VERSION 5.8 ;
BUSBITCHARS "[]" ;
DIVIDERCHAR "/" ;
UNITS
    DATABASE MICRONS 1000 ;
END UNITS

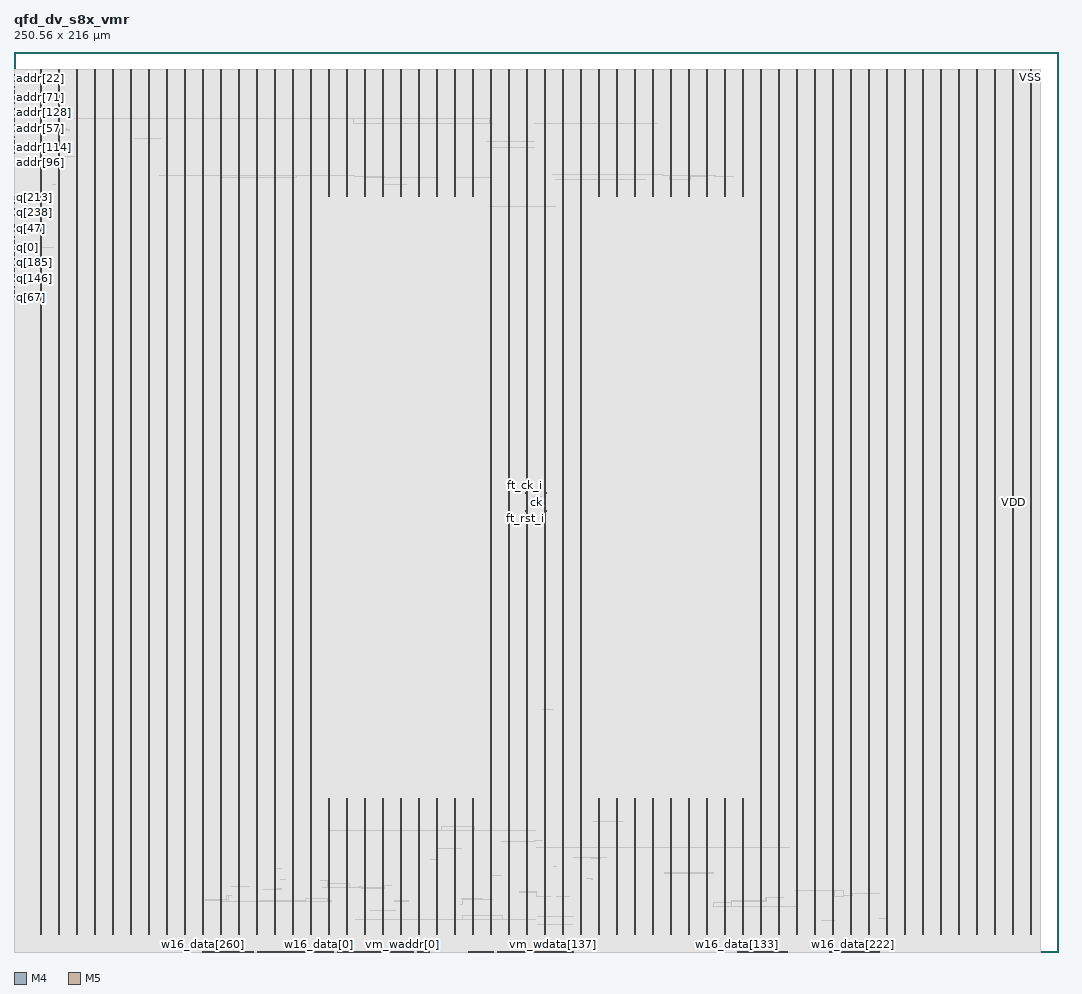
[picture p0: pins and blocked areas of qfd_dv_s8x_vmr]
MACRO qfd_dv_s8x_vmr
  FOREIGN qfd_dv_s8x_vmr 0 0 ;
  CLASS BLOCK ;
  SIZE 250.56 BY 216 ;
  PIN addr[0]
    DIRECTION INPUT ;
    USE SIGNAL ;
    PORT
      LAYER M4 ;
        RECT  0 207.504 0.084 207.528 ;
    END
  END addr[0]
  PIN addr[100]
    DIRECTION INPUT ;
    USE SIGNAL ;
    PORT
      LAYER M4 ;
        RECT  0 191.76 0.084 191.784 ;
    END
  END addr[100]
  PIN addr[101]
    DIRECTION INPUT ;
    USE SIGNAL ;
    PORT
      LAYER M4 ;
        RECT  0 191.856 0.084 191.88 ;
    END
  END addr[101]
  PIN addr[102]
    DIRECTION INPUT ;
    USE SIGNAL ;
    PORT
      LAYER M4 ;
        RECT  0 191.952 0.084 191.976 ;
    END
  END addr[102]
  PIN addr[103]
    DIRECTION INPUT ;
    USE SIGNAL ;
    PORT
      LAYER M4 ;
        RECT  0 192.048 0.084 192.072 ;
    END
  END addr[103]
  PIN addr[104]
    DIRECTION INPUT ;
    USE SIGNAL ;
    PORT
      LAYER M4 ;
        RECT  0 192.144 0.084 192.168 ;
    END
  END addr[104]
  PIN addr[105]
    DIRECTION INPUT ;
    USE SIGNAL ;
    PORT
      LAYER M4 ;
        RECT  0 192.24 0.084 192.264 ;
    END
  END addr[105]
  PIN addr[106]
    DIRECTION INPUT ;
    USE SIGNAL ;
    PORT
      LAYER M4 ;
        RECT  0 192.336 0.084 192.36 ;
    END
  END addr[106]
  PIN addr[107]
    DIRECTION INPUT ;
    USE SIGNAL ;
    PORT
      LAYER M4 ;
        RECT  0 192.432 0.084 192.456 ;
    END
  END addr[107]
  PIN addr[108]
    DIRECTION INPUT ;
    USE SIGNAL ;
    PORT
      LAYER M4 ;
        RECT  0 192.528 0.084 192.552 ;
    END
  END addr[108]
  PIN addr[109]
    DIRECTION INPUT ;
    USE SIGNAL ;
    PORT
      LAYER M4 ;
        RECT  0 192.624 0.084 192.648 ;
    END
  END addr[109]
  PIN addr[10]
    DIRECTION INPUT ;
    USE SIGNAL ;
    PORT
      LAYER M4 ;
        RECT  0 208.464 0.084 208.488 ;
    END
  END addr[10]
  PIN addr[110]
    DIRECTION INPUT ;
    USE SIGNAL ;
    PORT
      LAYER M4 ;
        RECT  0 192.72 0.084 192.744 ;
    END
  END addr[110]
  PIN addr[111]
    DIRECTION INPUT ;
    USE SIGNAL ;
    PORT
      LAYER M4 ;
        RECT  0 192.816 0.084 192.84 ;
    END
  END addr[111]
  PIN addr[112]
    DIRECTION INPUT ;
    USE SIGNAL ;
    PORT
      LAYER M4 ;
        RECT  0 192.912 0.084 192.936 ;
    END
  END addr[112]
  PIN addr[113]
    DIRECTION INPUT ;
    USE SIGNAL ;
    PORT
      LAYER M4 ;
        RECT  0 193.008 0.084 193.032 ;
    END
  END addr[113]
  PIN addr[114]
    DIRECTION INPUT ;
    USE SIGNAL ;
    PORT
      LAYER M4 ;
        RECT  0 193.104 0.084 193.128 ;
    END
  END addr[114]
  PIN addr[115]
    DIRECTION INPUT ;
    USE SIGNAL ;
    PORT
      LAYER M4 ;
        RECT  0 193.2 0.084 193.224 ;
    END
  END addr[115]
  PIN addr[116]
    DIRECTION INPUT ;
    USE SIGNAL ;
    PORT
      LAYER M4 ;
        RECT  0 193.296 0.084 193.32 ;
    END
  END addr[116]
  PIN addr[117]
    DIRECTION INPUT ;
    USE SIGNAL ;
    PORT
      LAYER M4 ;
        RECT  0 193.392 0.084 193.416 ;
    END
  END addr[117]
  PIN addr[118]
    DIRECTION INPUT ;
    USE SIGNAL ;
    PORT
      LAYER M4 ;
        RECT  0 193.488 0.084 193.512 ;
    END
  END addr[118]
  PIN addr[119]
    DIRECTION INPUT ;
    USE SIGNAL ;
    PORT
      LAYER M4 ;
        RECT  0 193.584 0.084 193.608 ;
    END
  END addr[119]
  PIN addr[11]
    DIRECTION INPUT ;
    USE SIGNAL ;
    PORT
      LAYER M4 ;
        RECT  0 208.56 0.084 208.584 ;
    END
  END addr[11]
  PIN addr[120]
    DIRECTION INPUT ;
    USE SIGNAL ;
    PORT
      LAYER M4 ;
        RECT  0 193.68 0.084 193.704 ;
    END
  END addr[120]
  PIN addr[121]
    DIRECTION INPUT ;
    USE SIGNAL ;
    PORT
      LAYER M4 ;
        RECT  0 193.776 0.084 193.8 ;
    END
  END addr[121]
  PIN addr[122]
    DIRECTION INPUT ;
    USE SIGNAL ;
    PORT
      LAYER M4 ;
        RECT  0 193.872 0.084 193.896 ;
    END
  END addr[122]
  PIN addr[123]
    DIRECTION INPUT ;
    USE SIGNAL ;
    PORT
      LAYER M4 ;
        RECT  0 193.968 0.084 193.992 ;
    END
  END addr[123]
  PIN addr[124]
    DIRECTION INPUT ;
    USE SIGNAL ;
    PORT
      LAYER M4 ;
        RECT  0 194.064 0.084 194.088 ;
    END
  END addr[124]
  PIN addr[125]
    DIRECTION INPUT ;
    USE SIGNAL ;
    PORT
      LAYER M4 ;
        RECT  0 194.16 0.084 194.184 ;
    END
  END addr[125]
  PIN addr[126]
    DIRECTION INPUT ;
    USE SIGNAL ;
    PORT
      LAYER M4 ;
        RECT  0 194.256 0.084 194.28 ;
    END
  END addr[126]
  PIN addr[127]
    DIRECTION INPUT ;
    USE SIGNAL ;
    PORT
      LAYER M4 ;
        RECT  0 194.352 0.084 194.376 ;
    END
  END addr[127]
  PIN addr[128]
    DIRECTION INPUT ;
    USE SIGNAL ;
    PORT
      LAYER M4 ;
        RECT  0 201.36 0.084 201.384 ;
    END
  END addr[128]
  PIN addr[129]
    DIRECTION INPUT ;
    USE SIGNAL ;
    PORT
      LAYER M4 ;
        RECT  0 201.456 0.084 201.48 ;
    END
  END addr[129]
  PIN addr[12]
    DIRECTION INPUT ;
    USE SIGNAL ;
    PORT
      LAYER M4 ;
        RECT  0 208.656 0.084 208.68 ;
    END
  END addr[12]
  PIN addr[130]
    DIRECTION INPUT ;
    USE SIGNAL ;
    PORT
      LAYER M4 ;
        RECT  0 201.552 0.084 201.576 ;
    END
  END addr[130]
  PIN addr[131]
    DIRECTION INPUT ;
    USE SIGNAL ;
    PORT
      LAYER M4 ;
        RECT  0 201.648 0.084 201.672 ;
    END
  END addr[131]
  PIN addr[132]
    DIRECTION INPUT ;
    USE SIGNAL ;
    PORT
      LAYER M4 ;
        RECT  0 201.744 0.084 201.768 ;
    END
  END addr[132]
  PIN addr[133]
    DIRECTION INPUT ;
    USE SIGNAL ;
    PORT
      LAYER M4 ;
        RECT  0 201.84 0.084 201.864 ;
    END
  END addr[133]
  PIN addr[134]
    DIRECTION INPUT ;
    USE SIGNAL ;
    PORT
      LAYER M4 ;
        RECT  0 201.936 0.084 201.96 ;
    END
  END addr[134]
  PIN addr[135]
    DIRECTION INPUT ;
    USE SIGNAL ;
    PORT
      LAYER M4 ;
        RECT  0 202.032 0.084 202.056 ;
    END
  END addr[135]
  PIN addr[136]
    DIRECTION INPUT ;
    USE SIGNAL ;
    PORT
      LAYER M4 ;
        RECT  0 202.128 0.084 202.152 ;
    END
  END addr[136]
  PIN addr[137]
    DIRECTION INPUT ;
    USE SIGNAL ;
    PORT
      LAYER M4 ;
        RECT  0 202.224 0.084 202.248 ;
    END
  END addr[137]
  PIN addr[138]
    DIRECTION INPUT ;
    USE SIGNAL ;
    PORT
      LAYER M4 ;
        RECT  0 202.32 0.084 202.344 ;
    END
  END addr[138]
  PIN addr[139]
    DIRECTION INPUT ;
    USE SIGNAL ;
    PORT
      LAYER M4 ;
        RECT  0 202.416 0.084 202.44 ;
    END
  END addr[139]
  PIN addr[13]
    DIRECTION INPUT ;
    USE SIGNAL ;
    PORT
      LAYER M4 ;
        RECT  0 208.752 0.084 208.776 ;
    END
  END addr[13]
  PIN addr[140]
    DIRECTION INPUT ;
    USE SIGNAL ;
    PORT
      LAYER M4 ;
        RECT  0 202.512 0.084 202.536 ;
    END
  END addr[140]
  PIN addr[141]
    DIRECTION INPUT ;
    USE SIGNAL ;
    PORT
      LAYER M4 ;
        RECT  0 202.608 0.084 202.632 ;
    END
  END addr[141]
  PIN addr[142]
    DIRECTION INPUT ;
    USE SIGNAL ;
    PORT
      LAYER M4 ;
        RECT  0 202.704 0.084 202.728 ;
    END
  END addr[142]
  PIN addr[143]
    DIRECTION INPUT ;
    USE SIGNAL ;
    PORT
      LAYER M4 ;
        RECT  0 202.8 0.084 202.824 ;
    END
  END addr[143]
  PIN addr[144]
    DIRECTION INPUT ;
    USE SIGNAL ;
    PORT
      LAYER M4 ;
        RECT  0 202.896 0.084 202.92 ;
    END
  END addr[144]
  PIN addr[145]
    DIRECTION INPUT ;
    USE SIGNAL ;
    PORT
      LAYER M4 ;
        RECT  0 202.992 0.084 203.016 ;
    END
  END addr[145]
  PIN addr[146]
    DIRECTION INPUT ;
    USE SIGNAL ;
    PORT
      LAYER M4 ;
        RECT  0 203.088 0.084 203.112 ;
    END
  END addr[146]
  PIN addr[147]
    DIRECTION INPUT ;
    USE SIGNAL ;
    PORT
      LAYER M4 ;
        RECT  0 203.184 0.084 203.208 ;
    END
  END addr[147]
  PIN addr[148]
    DIRECTION INPUT ;
    USE SIGNAL ;
    PORT
      LAYER M4 ;
        RECT  0 203.28 0.084 203.304 ;
    END
  END addr[148]
  PIN addr[149]
    DIRECTION INPUT ;
    USE SIGNAL ;
    PORT
      LAYER M4 ;
        RECT  0 203.376 0.084 203.4 ;
    END
  END addr[149]
  PIN addr[14]
    DIRECTION INPUT ;
    USE SIGNAL ;
    PORT
      LAYER M4 ;
        RECT  0 208.848 0.084 208.872 ;
    END
  END addr[14]
  PIN addr[150]
    DIRECTION INPUT ;
    USE SIGNAL ;
    PORT
      LAYER M4 ;
        RECT  0 203.472 0.084 203.496 ;
    END
  END addr[150]
  PIN addr[151]
    DIRECTION INPUT ;
    USE SIGNAL ;
    PORT
      LAYER M4 ;
        RECT  0 203.568 0.084 203.592 ;
    END
  END addr[151]
  PIN addr[152]
    DIRECTION INPUT ;
    USE SIGNAL ;
    PORT
      LAYER M4 ;
        RECT  0 203.664 0.084 203.688 ;
    END
  END addr[152]
  PIN addr[153]
    DIRECTION INPUT ;
    USE SIGNAL ;
    PORT
      LAYER M4 ;
        RECT  0 203.76 0.084 203.784 ;
    END
  END addr[153]
  PIN addr[154]
    DIRECTION INPUT ;
    USE SIGNAL ;
    PORT
      LAYER M4 ;
        RECT  0 203.856 0.084 203.88 ;
    END
  END addr[154]
  PIN addr[155]
    DIRECTION INPUT ;
    USE SIGNAL ;
    PORT
      LAYER M4 ;
        RECT  0 203.952 0.084 203.976 ;
    END
  END addr[155]
  PIN addr[156]
    DIRECTION INPUT ;
    USE SIGNAL ;
    PORT
      LAYER M4 ;
        RECT  0 204.048 0.084 204.072 ;
    END
  END addr[156]
  PIN addr[157]
    DIRECTION INPUT ;
    USE SIGNAL ;
    PORT
      LAYER M4 ;
        RECT  0 204.144 0.084 204.168 ;
    END
  END addr[157]
  PIN addr[158]
    DIRECTION INPUT ;
    USE SIGNAL ;
    PORT
      LAYER M4 ;
        RECT  0 204.24 0.084 204.264 ;
    END
  END addr[158]
  PIN addr[159]
    DIRECTION INPUT ;
    USE SIGNAL ;
    PORT
      LAYER M4 ;
        RECT  0 204.336 0.084 204.36 ;
    END
  END addr[159]
  PIN addr[15]
    DIRECTION INPUT ;
    USE SIGNAL ;
    PORT
      LAYER M4 ;
        RECT  0 208.944 0.084 208.968 ;
    END
  END addr[15]
  PIN addr[160]
    DIRECTION INPUT ;
    USE SIGNAL ;
    PORT
      LAYER M4 ;
        RECT  0 198.288 0.084 198.312 ;
    END
  END addr[160]
  PIN addr[161]
    DIRECTION INPUT ;
    USE SIGNAL ;
    PORT
      LAYER M4 ;
        RECT  0 198.384 0.084 198.408 ;
    END
  END addr[161]
  PIN addr[162]
    DIRECTION INPUT ;
    USE SIGNAL ;
    PORT
      LAYER M4 ;
        RECT  0 198.48 0.084 198.504 ;
    END
  END addr[162]
  PIN addr[163]
    DIRECTION INPUT ;
    USE SIGNAL ;
    PORT
      LAYER M4 ;
        RECT  0 198.576 0.084 198.6 ;
    END
  END addr[163]
  PIN addr[164]
    DIRECTION INPUT ;
    USE SIGNAL ;
    PORT
      LAYER M4 ;
        RECT  0 198.672 0.084 198.696 ;
    END
  END addr[164]
  PIN addr[165]
    DIRECTION INPUT ;
    USE SIGNAL ;
    PORT
      LAYER M4 ;
        RECT  0 198.768 0.084 198.792 ;
    END
  END addr[165]
  PIN addr[166]
    DIRECTION INPUT ;
    USE SIGNAL ;
    PORT
      LAYER M4 ;
        RECT  0 198.864 0.084 198.888 ;
    END
  END addr[166]
  PIN addr[167]
    DIRECTION INPUT ;
    USE SIGNAL ;
    PORT
      LAYER M4 ;
        RECT  0 198.96 0.084 198.984 ;
    END
  END addr[167]
  PIN addr[168]
    DIRECTION INPUT ;
    USE SIGNAL ;
    PORT
      LAYER M4 ;
        RECT  0 199.056 0.084 199.08 ;
    END
  END addr[168]
  PIN addr[169]
    DIRECTION INPUT ;
    USE SIGNAL ;
    PORT
      LAYER M4 ;
        RECT  0 199.152 0.084 199.176 ;
    END
  END addr[169]
  PIN addr[16]
    DIRECTION INPUT ;
    USE SIGNAL ;
    PORT
      LAYER M4 ;
        RECT  0 209.04 0.084 209.064 ;
    END
  END addr[16]
  PIN addr[170]
    DIRECTION INPUT ;
    USE SIGNAL ;
    PORT
      LAYER M4 ;
        RECT  0 199.248 0.084 199.272 ;
    END
  END addr[170]
  PIN addr[171]
    DIRECTION INPUT ;
    USE SIGNAL ;
    PORT
      LAYER M4 ;
        RECT  0 199.344 0.084 199.368 ;
    END
  END addr[171]
  PIN addr[172]
    DIRECTION INPUT ;
    USE SIGNAL ;
    PORT
      LAYER M4 ;
        RECT  0 199.44 0.084 199.464 ;
    END
  END addr[172]
  PIN addr[173]
    DIRECTION INPUT ;
    USE SIGNAL ;
    PORT
      LAYER M4 ;
        RECT  0 199.536 0.084 199.56 ;
    END
  END addr[173]
  PIN addr[174]
    DIRECTION INPUT ;
    USE SIGNAL ;
    PORT
      LAYER M4 ;
        RECT  0 199.632 0.084 199.656 ;
    END
  END addr[174]
  PIN addr[175]
    DIRECTION INPUT ;
    USE SIGNAL ;
    PORT
      LAYER M4 ;
        RECT  0 199.728 0.084 199.752 ;
    END
  END addr[175]
  PIN addr[176]
    DIRECTION INPUT ;
    USE SIGNAL ;
    PORT
      LAYER M4 ;
        RECT  0 199.824 0.084 199.848 ;
    END
  END addr[176]
  PIN addr[177]
    DIRECTION INPUT ;
    USE SIGNAL ;
    PORT
      LAYER M4 ;
        RECT  0 199.92 0.084 199.944 ;
    END
  END addr[177]
  PIN addr[178]
    DIRECTION INPUT ;
    USE SIGNAL ;
    PORT
      LAYER M4 ;
        RECT  0 200.016 0.084 200.04 ;
    END
  END addr[178]
  PIN addr[179]
    DIRECTION INPUT ;
    USE SIGNAL ;
    PORT
      LAYER M4 ;
        RECT  0 200.112 0.084 200.136 ;
    END
  END addr[179]
  PIN addr[17]
    DIRECTION INPUT ;
    USE SIGNAL ;
    PORT
      LAYER M4 ;
        RECT  0 209.136 0.084 209.16 ;
    END
  END addr[17]
  PIN addr[180]
    DIRECTION INPUT ;
    USE SIGNAL ;
    PORT
      LAYER M4 ;
        RECT  0 200.208 0.084 200.232 ;
    END
  END addr[180]
  PIN addr[181]
    DIRECTION INPUT ;
    USE SIGNAL ;
    PORT
      LAYER M4 ;
        RECT  0 200.304 0.084 200.328 ;
    END
  END addr[181]
  PIN addr[182]
    DIRECTION INPUT ;
    USE SIGNAL ;
    PORT
      LAYER M4 ;
        RECT  0 200.4 0.084 200.424 ;
    END
  END addr[182]
  PIN addr[183]
    DIRECTION INPUT ;
    USE SIGNAL ;
    PORT
      LAYER M4 ;
        RECT  0 200.496 0.084 200.52 ;
    END
  END addr[183]
  PIN addr[184]
    DIRECTION INPUT ;
    USE SIGNAL ;
    PORT
      LAYER M4 ;
        RECT  0 200.592 0.084 200.616 ;
    END
  END addr[184]
  PIN addr[185]
    DIRECTION INPUT ;
    USE SIGNAL ;
    PORT
      LAYER M4 ;
        RECT  0 200.688 0.084 200.712 ;
    END
  END addr[185]
  PIN addr[186]
    DIRECTION INPUT ;
    USE SIGNAL ;
    PORT
      LAYER M4 ;
        RECT  0 200.784 0.084 200.808 ;
    END
  END addr[186]
  PIN addr[187]
    DIRECTION INPUT ;
    USE SIGNAL ;
    PORT
      LAYER M4 ;
        RECT  0 200.88 0.084 200.904 ;
    END
  END addr[187]
  PIN addr[188]
    DIRECTION INPUT ;
    USE SIGNAL ;
    PORT
      LAYER M4 ;
        RECT  0 200.976 0.084 201 ;
    END
  END addr[188]
  PIN addr[189]
    DIRECTION INPUT ;
    USE SIGNAL ;
    PORT
      LAYER M4 ;
        RECT  0 201.072 0.084 201.096 ;
    END
  END addr[189]
  PIN addr[18]
    DIRECTION INPUT ;
    USE SIGNAL ;
    PORT
      LAYER M4 ;
        RECT  0 209.232 0.084 209.256 ;
    END
  END addr[18]
  PIN addr[190]
    DIRECTION INPUT ;
    USE SIGNAL ;
    PORT
      LAYER M4 ;
        RECT  0 201.168 0.084 201.192 ;
    END
  END addr[190]
  PIN addr[191]
    DIRECTION INPUT ;
    USE SIGNAL ;
    PORT
      LAYER M4 ;
        RECT  0 201.264 0.084 201.288 ;
    END
  END addr[191]
  PIN addr[19]
    DIRECTION INPUT ;
    USE SIGNAL ;
    PORT
      LAYER M4 ;
        RECT  0 209.328 0.084 209.352 ;
    END
  END addr[19]
  PIN addr[1]
    DIRECTION INPUT ;
    USE SIGNAL ;
    PORT
      LAYER M4 ;
        RECT  0 207.6 0.084 207.624 ;
    END
  END addr[1]
  PIN addr[20]
    DIRECTION INPUT ;
    USE SIGNAL ;
    PORT
      LAYER M4 ;
        RECT  0 209.424 0.084 209.448 ;
    END
  END addr[20]
  PIN addr[21]
    DIRECTION INPUT ;
    USE SIGNAL ;
    PORT
      LAYER M4 ;
        RECT  0 209.52 0.084 209.544 ;
    END
  END addr[21]
  PIN addr[22]
    DIRECTION INPUT ;
    USE SIGNAL ;
    PORT
      LAYER M4 ;
        RECT  0 209.616 0.084 209.64 ;
    END
  END addr[22]
  PIN addr[23]
    DIRECTION INPUT ;
    USE SIGNAL ;
    PORT
      LAYER M4 ;
        RECT  0 209.712 0.084 209.736 ;
    END
  END addr[23]
  PIN addr[24]
    DIRECTION INPUT ;
    USE SIGNAL ;
    PORT
      LAYER M4 ;
        RECT  0 209.808 0.084 209.832 ;
    END
  END addr[24]
  PIN addr[25]
    DIRECTION INPUT ;
    USE SIGNAL ;
    PORT
      LAYER M4 ;
        RECT  0 209.904 0.084 209.928 ;
    END
  END addr[25]
  PIN addr[26]
    DIRECTION INPUT ;
    USE SIGNAL ;
    PORT
      LAYER M4 ;
        RECT  0 210 0.084 210.024 ;
    END
  END addr[26]
  PIN addr[27]
    DIRECTION INPUT ;
    USE SIGNAL ;
    PORT
      LAYER M4 ;
        RECT  0 210.096 0.084 210.12 ;
    END
  END addr[27]
  PIN addr[28]
    DIRECTION INPUT ;
    USE SIGNAL ;
    PORT
      LAYER M4 ;
        RECT  0 210.192 0.084 210.216 ;
    END
  END addr[28]
  PIN addr[29]
    DIRECTION INPUT ;
    USE SIGNAL ;
    PORT
      LAYER M4 ;
        RECT  0 210.288 0.084 210.312 ;
    END
  END addr[29]
  PIN addr[2]
    DIRECTION INPUT ;
    USE SIGNAL ;
    PORT
      LAYER M4 ;
        RECT  0 207.696 0.084 207.72 ;
    END
  END addr[2]
  PIN addr[30]
    DIRECTION INPUT ;
    USE SIGNAL ;
    PORT
      LAYER M4 ;
        RECT  0 210.384 0.084 210.408 ;
    END
  END addr[30]
  PIN addr[31]
    DIRECTION INPUT ;
    USE SIGNAL ;
    PORT
      LAYER M4 ;
        RECT  0 210.48 0.084 210.504 ;
    END
  END addr[31]
  PIN addr[32]
    DIRECTION INPUT ;
    USE SIGNAL ;
    PORT
      LAYER M4 ;
        RECT  0 195.216 0.084 195.24 ;
    END
  END addr[32]
  PIN addr[33]
    DIRECTION INPUT ;
    USE SIGNAL ;
    PORT
      LAYER M4 ;
        RECT  0 195.312 0.084 195.336 ;
    END
  END addr[33]
  PIN addr[34]
    DIRECTION INPUT ;
    USE SIGNAL ;
    PORT
      LAYER M4 ;
        RECT  0 195.408 0.084 195.432 ;
    END
  END addr[34]
  PIN addr[35]
    DIRECTION INPUT ;
    USE SIGNAL ;
    PORT
      LAYER M4 ;
        RECT  0 195.504 0.084 195.528 ;
    END
  END addr[35]
  PIN addr[36]
    DIRECTION INPUT ;
    USE SIGNAL ;
    PORT
      LAYER M4 ;
        RECT  0 195.6 0.084 195.624 ;
    END
  END addr[36]
  PIN addr[37]
    DIRECTION INPUT ;
    USE SIGNAL ;
    PORT
      LAYER M4 ;
        RECT  0 195.696 0.084 195.72 ;
    END
  END addr[37]
  PIN addr[38]
    DIRECTION INPUT ;
    USE SIGNAL ;
    PORT
      LAYER M4 ;
        RECT  0 195.792 0.084 195.816 ;
    END
  END addr[38]
  PIN addr[39]
    DIRECTION INPUT ;
    USE SIGNAL ;
    PORT
      LAYER M4 ;
        RECT  0 195.888 0.084 195.912 ;
    END
  END addr[39]
  PIN addr[3]
    DIRECTION INPUT ;
    USE SIGNAL ;
    PORT
      LAYER M4 ;
        RECT  0 207.792 0.084 207.816 ;
    END
  END addr[3]
  PIN addr[40]
    DIRECTION INPUT ;
    USE SIGNAL ;
    PORT
      LAYER M4 ;
        RECT  0 195.984 0.084 196.008 ;
    END
  END addr[40]
  PIN addr[41]
    DIRECTION INPUT ;
    USE SIGNAL ;
    PORT
      LAYER M4 ;
        RECT  0 196.08 0.084 196.104 ;
    END
  END addr[41]
  PIN addr[42]
    DIRECTION INPUT ;
    USE SIGNAL ;
    PORT
      LAYER M4 ;
        RECT  0 196.176 0.084 196.2 ;
    END
  END addr[42]
  PIN addr[43]
    DIRECTION INPUT ;
    USE SIGNAL ;
    PORT
      LAYER M4 ;
        RECT  0 196.272 0.084 196.296 ;
    END
  END addr[43]
  PIN addr[44]
    DIRECTION INPUT ;
    USE SIGNAL ;
    PORT
      LAYER M4 ;
        RECT  0 196.368 0.084 196.392 ;
    END
  END addr[44]
  PIN addr[45]
    DIRECTION INPUT ;
    USE SIGNAL ;
    PORT
      LAYER M4 ;
        RECT  0 196.464 0.084 196.488 ;
    END
  END addr[45]
  PIN addr[46]
    DIRECTION INPUT ;
    USE SIGNAL ;
    PORT
      LAYER M4 ;
        RECT  0 196.56 0.084 196.584 ;
    END
  END addr[46]
  PIN addr[47]
    DIRECTION INPUT ;
    USE SIGNAL ;
    PORT
      LAYER M4 ;
        RECT  0 196.656 0.084 196.68 ;
    END
  END addr[47]
  PIN addr[48]
    DIRECTION INPUT ;
    USE SIGNAL ;
    PORT
      LAYER M4 ;
        RECT  0 196.752 0.084 196.776 ;
    END
  END addr[48]
  PIN addr[49]
    DIRECTION INPUT ;
    USE SIGNAL ;
    PORT
      LAYER M4 ;
        RECT  0 196.848 0.084 196.872 ;
    END
  END addr[49]
  PIN addr[4]
    DIRECTION INPUT ;
    USE SIGNAL ;
    PORT
      LAYER M4 ;
        RECT  0 207.888 0.084 207.912 ;
    END
  END addr[4]
  PIN addr[50]
    DIRECTION INPUT ;
    USE SIGNAL ;
    PORT
      LAYER M4 ;
        RECT  0 196.944 0.084 196.968 ;
    END
  END addr[50]
  PIN addr[51]
    DIRECTION INPUT ;
    USE SIGNAL ;
    PORT
      LAYER M4 ;
        RECT  0 197.04 0.084 197.064 ;
    END
  END addr[51]
  PIN addr[52]
    DIRECTION INPUT ;
    USE SIGNAL ;
    PORT
      LAYER M4 ;
        RECT  0 197.136 0.084 197.16 ;
    END
  END addr[52]
  PIN addr[53]
    DIRECTION INPUT ;
    USE SIGNAL ;
    PORT
      LAYER M4 ;
        RECT  0 197.232 0.084 197.256 ;
    END
  END addr[53]
  PIN addr[54]
    DIRECTION INPUT ;
    USE SIGNAL ;
    PORT
      LAYER M4 ;
        RECT  0 197.328 0.084 197.352 ;
    END
  END addr[54]
  PIN addr[55]
    DIRECTION INPUT ;
    USE SIGNAL ;
    PORT
      LAYER M4 ;
        RECT  0 197.424 0.084 197.448 ;
    END
  END addr[55]
  PIN addr[56]
    DIRECTION INPUT ;
    USE SIGNAL ;
    PORT
      LAYER M4 ;
        RECT  0 197.52 0.084 197.544 ;
    END
  END addr[56]
  PIN addr[57]
    DIRECTION INPUT ;
    USE SIGNAL ;
    PORT
      LAYER M4 ;
        RECT  0 197.616 0.084 197.64 ;
    END
  END addr[57]
  PIN addr[58]
    DIRECTION INPUT ;
    USE SIGNAL ;
    PORT
      LAYER M4 ;
        RECT  0 197.712 0.084 197.736 ;
    END
  END addr[58]
  PIN addr[59]
    DIRECTION INPUT ;
    USE SIGNAL ;
    PORT
      LAYER M4 ;
        RECT  0 197.808 0.084 197.832 ;
    END
  END addr[59]
  PIN addr[5]
    DIRECTION INPUT ;
    USE SIGNAL ;
    PORT
      LAYER M4 ;
        RECT  0 207.984 0.084 208.008 ;
    END
  END addr[5]
  PIN addr[60]
    DIRECTION INPUT ;
    USE SIGNAL ;
    PORT
      LAYER M4 ;
        RECT  0 197.904 0.084 197.928 ;
    END
  END addr[60]
  PIN addr[61]
    DIRECTION INPUT ;
    USE SIGNAL ;
    PORT
      LAYER M4 ;
        RECT  0 198 0.084 198.024 ;
    END
  END addr[61]
  PIN addr[62]
    DIRECTION INPUT ;
    USE SIGNAL ;
    PORT
      LAYER M4 ;
        RECT  0 198.096 0.084 198.12 ;
    END
  END addr[62]
  PIN addr[63]
    DIRECTION INPUT ;
    USE SIGNAL ;
    PORT
      LAYER M4 ;
        RECT  0 198.192 0.084 198.216 ;
    END
  END addr[63]
  PIN addr[64]
    DIRECTION INPUT ;
    USE SIGNAL ;
    PORT
      LAYER M4 ;
        RECT  0 204.432 0.084 204.456 ;
    END
  END addr[64]
  PIN addr[65]
    DIRECTION INPUT ;
    USE SIGNAL ;
    PORT
      LAYER M4 ;
        RECT  0 204.528 0.084 204.552 ;
    END
  END addr[65]
  PIN addr[66]
    DIRECTION INPUT ;
    USE SIGNAL ;
    PORT
      LAYER M4 ;
        RECT  0 204.624 0.084 204.648 ;
    END
  END addr[66]
  PIN addr[67]
    DIRECTION INPUT ;
    USE SIGNAL ;
    PORT
      LAYER M4 ;
        RECT  0 204.72 0.084 204.744 ;
    END
  END addr[67]
  PIN addr[68]
    DIRECTION INPUT ;
    USE SIGNAL ;
    PORT
      LAYER M4 ;
        RECT  0 204.816 0.084 204.84 ;
    END
  END addr[68]
  PIN addr[69]
    DIRECTION INPUT ;
    USE SIGNAL ;
    PORT
      LAYER M4 ;
        RECT  0 204.912 0.084 204.936 ;
    END
  END addr[69]
  PIN addr[6]
    DIRECTION INPUT ;
    USE SIGNAL ;
    PORT
      LAYER M4 ;
        RECT  0 208.08 0.084 208.104 ;
    END
  END addr[6]
  PIN addr[70]
    DIRECTION INPUT ;
    USE SIGNAL ;
    PORT
      LAYER M4 ;
        RECT  0 205.008 0.084 205.032 ;
    END
  END addr[70]
  PIN addr[71]
    DIRECTION INPUT ;
    USE SIGNAL ;
    PORT
      LAYER M4 ;
        RECT  0 205.104 0.084 205.128 ;
    END
  END addr[71]
  PIN addr[72]
    DIRECTION INPUT ;
    USE SIGNAL ;
    PORT
      LAYER M4 ;
        RECT  0 205.2 0.084 205.224 ;
    END
  END addr[72]
  PIN addr[73]
    DIRECTION INPUT ;
    USE SIGNAL ;
    PORT
      LAYER M4 ;
        RECT  0 205.296 0.084 205.32 ;
    END
  END addr[73]
  PIN addr[74]
    DIRECTION INPUT ;
    USE SIGNAL ;
    PORT
      LAYER M4 ;
        RECT  0 205.392 0.084 205.416 ;
    END
  END addr[74]
  PIN addr[75]
    DIRECTION INPUT ;
    USE SIGNAL ;
    PORT
      LAYER M4 ;
        RECT  0 205.488 0.084 205.512 ;
    END
  END addr[75]
  PIN addr[76]
    DIRECTION INPUT ;
    USE SIGNAL ;
    PORT
      LAYER M4 ;
        RECT  0 205.584 0.084 205.608 ;
    END
  END addr[76]
  PIN addr[77]
    DIRECTION INPUT ;
    USE SIGNAL ;
    PORT
      LAYER M4 ;
        RECT  0 205.68 0.084 205.704 ;
    END
  END addr[77]
  PIN addr[78]
    DIRECTION INPUT ;
    USE SIGNAL ;
    PORT
      LAYER M4 ;
        RECT  0 205.776 0.084 205.8 ;
    END
  END addr[78]
  PIN addr[79]
    DIRECTION INPUT ;
    USE SIGNAL ;
    PORT
      LAYER M4 ;
        RECT  0 205.872 0.084 205.896 ;
    END
  END addr[79]
  PIN addr[7]
    DIRECTION INPUT ;
    USE SIGNAL ;
    PORT
      LAYER M4 ;
        RECT  0 208.176 0.084 208.2 ;
    END
  END addr[7]
  PIN addr[80]
    DIRECTION INPUT ;
    USE SIGNAL ;
    PORT
      LAYER M4 ;
        RECT  0 205.968 0.084 205.992 ;
    END
  END addr[80]
  PIN addr[81]
    DIRECTION INPUT ;
    USE SIGNAL ;
    PORT
      LAYER M4 ;
        RECT  0 206.064 0.084 206.088 ;
    END
  END addr[81]
  PIN addr[82]
    DIRECTION INPUT ;
    USE SIGNAL ;
    PORT
      LAYER M4 ;
        RECT  0 206.16 0.084 206.184 ;
    END
  END addr[82]
  PIN addr[83]
    DIRECTION INPUT ;
    USE SIGNAL ;
    PORT
      LAYER M4 ;
        RECT  0 206.256 0.084 206.28 ;
    END
  END addr[83]
  PIN addr[84]
    DIRECTION INPUT ;
    USE SIGNAL ;
    PORT
      LAYER M4 ;
        RECT  0 206.352 0.084 206.376 ;
    END
  END addr[84]
  PIN addr[85]
    DIRECTION INPUT ;
    USE SIGNAL ;
    PORT
      LAYER M4 ;
        RECT  0 206.448 0.084 206.472 ;
    END
  END addr[85]
  PIN addr[86]
    DIRECTION INPUT ;
    USE SIGNAL ;
    PORT
      LAYER M4 ;
        RECT  0 206.544 0.084 206.568 ;
    END
  END addr[86]
  PIN addr[87]
    DIRECTION INPUT ;
    USE SIGNAL ;
    PORT
      LAYER M4 ;
        RECT  0 206.64 0.084 206.664 ;
    END
  END addr[87]
  PIN addr[88]
    DIRECTION INPUT ;
    USE SIGNAL ;
    PORT
      LAYER M4 ;
        RECT  0 206.736 0.084 206.76 ;
    END
  END addr[88]
  PIN addr[89]
    DIRECTION INPUT ;
    USE SIGNAL ;
    PORT
      LAYER M4 ;
        RECT  0 206.832 0.084 206.856 ;
    END
  END addr[89]
  PIN addr[8]
    DIRECTION INPUT ;
    USE SIGNAL ;
    PORT
      LAYER M4 ;
        RECT  0 208.272 0.084 208.296 ;
    END
  END addr[8]
  PIN addr[90]
    DIRECTION INPUT ;
    USE SIGNAL ;
    PORT
      LAYER M4 ;
        RECT  0 206.928 0.084 206.952 ;
    END
  END addr[90]
  PIN addr[91]
    DIRECTION INPUT ;
    USE SIGNAL ;
    PORT
      LAYER M4 ;
        RECT  0 207.024 0.084 207.048 ;
    END
  END addr[91]
  PIN addr[92]
    DIRECTION INPUT ;
    USE SIGNAL ;
    PORT
      LAYER M4 ;
        RECT  0 207.12 0.084 207.144 ;
    END
  END addr[92]
  PIN addr[93]
    DIRECTION INPUT ;
    USE SIGNAL ;
    PORT
      LAYER M4 ;
        RECT  0 207.216 0.084 207.24 ;
    END
  END addr[93]
  PIN addr[94]
    DIRECTION INPUT ;
    USE SIGNAL ;
    PORT
      LAYER M4 ;
        RECT  0 207.312 0.084 207.336 ;
    END
  END addr[94]
  PIN addr[95]
    DIRECTION INPUT ;
    USE SIGNAL ;
    PORT
      LAYER M4 ;
        RECT  0 207.408 0.084 207.432 ;
    END
  END addr[95]
  PIN addr[96]
    DIRECTION INPUT ;
    USE SIGNAL ;
    PORT
      LAYER M4 ;
        RECT  0 191.376 0.084 191.4 ;
    END
  END addr[96]
  PIN addr[97]
    DIRECTION INPUT ;
    USE SIGNAL ;
    PORT
      LAYER M4 ;
        RECT  0 191.472 0.084 191.496 ;
    END
  END addr[97]
  PIN addr[98]
    DIRECTION INPUT ;
    USE SIGNAL ;
    PORT
      LAYER M4 ;
        RECT  0 191.568 0.084 191.592 ;
    END
  END addr[98]
  PIN addr[99]
    DIRECTION INPUT ;
    USE SIGNAL ;
    PORT
      LAYER M4 ;
        RECT  0 191.664 0.084 191.688 ;
    END
  END addr[99]
  PIN addr[9]
    DIRECTION INPUT ;
    USE SIGNAL ;
    PORT
      LAYER M4 ;
        RECT  0 208.368 0.084 208.392 ;
    END
  END addr[9]
  PIN ck
    DIRECTION INPUT ;
    USE SIGNAL ;
    PORT
      LAYER M5 ;
        RECT  125.28 107.808 125.304 108.192 ;
    END
  END ck
  PIN fault
    DIRECTION OUTPUT ;
    USE SIGNAL ;
    PORT
      LAYER M5 ;
        RECT  92.976 0 93 0.084 ;
    END
  END fault
  PIN q[0]
    DIRECTION OUTPUT ;
    USE SIGNAL ;
    PORT
      LAYER M4 ;
        RECT  0 169.104 0.084 169.128 ;
    END
  END q[0]
  PIN q[100]
    DIRECTION OUTPUT ;
    USE SIGNAL ;
    PORT
      LAYER M4 ;
        RECT  0 166.416 0.084 166.44 ;
    END
  END q[100]
  PIN q[101]
    DIRECTION OUTPUT ;
    USE SIGNAL ;
    PORT
      LAYER M4 ;
        RECT  0 166.512 0.084 166.536 ;
    END
  END q[101]
  PIN q[102]
    DIRECTION OUTPUT ;
    USE SIGNAL ;
    PORT
      LAYER M4 ;
        RECT  0 166.608 0.084 166.632 ;
    END
  END q[102]
  PIN q[103]
    DIRECTION OUTPUT ;
    USE SIGNAL ;
    PORT
      LAYER M4 ;
        RECT  0 166.704 0.084 166.728 ;
    END
  END q[103]
  PIN q[104]
    DIRECTION OUTPUT ;
    USE SIGNAL ;
    PORT
      LAYER M4 ;
        RECT  0 166.8 0.084 166.824 ;
    END
  END q[104]
  PIN q[105]
    DIRECTION OUTPUT ;
    USE SIGNAL ;
    PORT
      LAYER M4 ;
        RECT  0 166.896 0.084 166.92 ;
    END
  END q[105]
  PIN q[106]
    DIRECTION OUTPUT ;
    USE SIGNAL ;
    PORT
      LAYER M4 ;
        RECT  0 166.992 0.084 167.016 ;
    END
  END q[106]
  PIN q[107]
    DIRECTION OUTPUT ;
    USE SIGNAL ;
    PORT
      LAYER M4 ;
        RECT  0 167.088 0.084 167.112 ;
    END
  END q[107]
  PIN q[108]
    DIRECTION OUTPUT ;
    USE SIGNAL ;
    PORT
      LAYER M4 ;
        RECT  0 167.184 0.084 167.208 ;
    END
  END q[108]
  PIN q[109]
    DIRECTION OUTPUT ;
    USE SIGNAL ;
    PORT
      LAYER M4 ;
        RECT  0 167.28 0.084 167.304 ;
    END
  END q[109]
  PIN q[10]
    DIRECTION OUTPUT ;
    USE SIGNAL ;
    PORT
      LAYER M4 ;
        RECT  0 170.064 0.084 170.088 ;
    END
  END q[10]
  PIN q[110]
    DIRECTION OUTPUT ;
    USE SIGNAL ;
    PORT
      LAYER M4 ;
        RECT  0 167.376 0.084 167.4 ;
    END
  END q[110]
  PIN q[111]
    DIRECTION OUTPUT ;
    USE SIGNAL ;
    PORT
      LAYER M4 ;
        RECT  0 167.472 0.084 167.496 ;
    END
  END q[111]
  PIN q[112]
    DIRECTION OUTPUT ;
    USE SIGNAL ;
    PORT
      LAYER M4 ;
        RECT  0 167.568 0.084 167.592 ;
    END
  END q[112]
  PIN q[113]
    DIRECTION OUTPUT ;
    USE SIGNAL ;
    PORT
      LAYER M4 ;
        RECT  0 167.664 0.084 167.688 ;
    END
  END q[113]
  PIN q[114]
    DIRECTION OUTPUT ;
    USE SIGNAL ;
    PORT
      LAYER M4 ;
        RECT  0 167.76 0.084 167.784 ;
    END
  END q[114]
  PIN q[115]
    DIRECTION OUTPUT ;
    USE SIGNAL ;
    PORT
      LAYER M4 ;
        RECT  0 167.856 0.084 167.88 ;
    END
  END q[115]
  PIN q[116]
    DIRECTION OUTPUT ;
    USE SIGNAL ;
    PORT
      LAYER M4 ;
        RECT  0 167.952 0.084 167.976 ;
    END
  END q[116]
  PIN q[117]
    DIRECTION OUTPUT ;
    USE SIGNAL ;
    PORT
      LAYER M4 ;
        RECT  0 168.048 0.084 168.072 ;
    END
  END q[117]
  PIN q[118]
    DIRECTION OUTPUT ;
    USE SIGNAL ;
    PORT
      LAYER M4 ;
        RECT  0 168.144 0.084 168.168 ;
    END
  END q[118]
  PIN q[119]
    DIRECTION OUTPUT ;
    USE SIGNAL ;
    PORT
      LAYER M4 ;
        RECT  0 168.24 0.084 168.264 ;
    END
  END q[119]
  PIN q[11]
    DIRECTION OUTPUT ;
    USE SIGNAL ;
    PORT
      LAYER M4 ;
        RECT  0 170.16 0.084 170.184 ;
    END
  END q[11]
  PIN q[120]
    DIRECTION OUTPUT ;
    USE SIGNAL ;
    PORT
      LAYER M4 ;
        RECT  0 168.336 0.084 168.36 ;
    END
  END q[120]
  PIN q[121]
    DIRECTION OUTPUT ;
    USE SIGNAL ;
    PORT
      LAYER M4 ;
        RECT  0 168.432 0.084 168.456 ;
    END
  END q[121]
  PIN q[122]
    DIRECTION OUTPUT ;
    USE SIGNAL ;
    PORT
      LAYER M4 ;
        RECT  0 168.528 0.084 168.552 ;
    END
  END q[122]
  PIN q[123]
    DIRECTION OUTPUT ;
    USE SIGNAL ;
    PORT
      LAYER M4 ;
        RECT  0 168.624 0.084 168.648 ;
    END
  END q[123]
  PIN q[124]
    DIRECTION OUTPUT ;
    USE SIGNAL ;
    PORT
      LAYER M4 ;
        RECT  0 168.72 0.084 168.744 ;
    END
  END q[124]
  PIN q[125]
    DIRECTION OUTPUT ;
    USE SIGNAL ;
    PORT
      LAYER M4 ;
        RECT  0 168.816 0.084 168.84 ;
    END
  END q[125]
  PIN q[126]
    DIRECTION OUTPUT ;
    USE SIGNAL ;
    PORT
      LAYER M4 ;
        RECT  0 168.912 0.084 168.936 ;
    END
  END q[126]
  PIN q[127]
    DIRECTION OUTPUT ;
    USE SIGNAL ;
    PORT
      LAYER M4 ;
        RECT  0 169.008 0.084 169.032 ;
    END
  END q[127]
  PIN q[128]
    DIRECTION OUTPUT ;
    USE SIGNAL ;
    PORT
      LAYER M4 ;
        RECT  0 159.888 0.084 159.912 ;
    END
  END q[128]
  PIN q[129]
    DIRECTION OUTPUT ;
    USE SIGNAL ;
    PORT
      LAYER M4 ;
        RECT  0 159.984 0.084 160.008 ;
    END
  END q[129]
  PIN q[12]
    DIRECTION OUTPUT ;
    USE SIGNAL ;
    PORT
      LAYER M4 ;
        RECT  0 170.256 0.084 170.28 ;
    END
  END q[12]
  PIN q[130]
    DIRECTION OUTPUT ;
    USE SIGNAL ;
    PORT
      LAYER M4 ;
        RECT  0 160.08 0.084 160.104 ;
    END
  END q[130]
  PIN q[131]
    DIRECTION OUTPUT ;
    USE SIGNAL ;
    PORT
      LAYER M4 ;
        RECT  0 160.176 0.084 160.2 ;
    END
  END q[131]
  PIN q[132]
    DIRECTION OUTPUT ;
    USE SIGNAL ;
    PORT
      LAYER M4 ;
        RECT  0 160.272 0.084 160.296 ;
    END
  END q[132]
  PIN q[133]
    DIRECTION OUTPUT ;
    USE SIGNAL ;
    PORT
      LAYER M4 ;
        RECT  0 160.368 0.084 160.392 ;
    END
  END q[133]
  PIN q[134]
    DIRECTION OUTPUT ;
    USE SIGNAL ;
    PORT
      LAYER M4 ;
        RECT  0 160.464 0.084 160.488 ;
    END
  END q[134]
  PIN q[135]
    DIRECTION OUTPUT ;
    USE SIGNAL ;
    PORT
      LAYER M4 ;
        RECT  0 160.56 0.084 160.584 ;
    END
  END q[135]
  PIN q[136]
    DIRECTION OUTPUT ;
    USE SIGNAL ;
    PORT
      LAYER M4 ;
        RECT  0 160.656 0.084 160.68 ;
    END
  END q[136]
  PIN q[137]
    DIRECTION OUTPUT ;
    USE SIGNAL ;
    PORT
      LAYER M4 ;
        RECT  0 160.752 0.084 160.776 ;
    END
  END q[137]
  PIN q[138]
    DIRECTION OUTPUT ;
    USE SIGNAL ;
    PORT
      LAYER M4 ;
        RECT  0 160.848 0.084 160.872 ;
    END
  END q[138]
  PIN q[139]
    DIRECTION OUTPUT ;
    USE SIGNAL ;
    PORT
      LAYER M4 ;
        RECT  0 160.944 0.084 160.968 ;
    END
  END q[139]
  PIN q[13]
    DIRECTION OUTPUT ;
    USE SIGNAL ;
    PORT
      LAYER M4 ;
        RECT  0 170.352 0.084 170.376 ;
    END
  END q[13]
  PIN q[140]
    DIRECTION OUTPUT ;
    USE SIGNAL ;
    PORT
      LAYER M4 ;
        RECT  0 161.04 0.084 161.064 ;
    END
  END q[140]
  PIN q[141]
    DIRECTION OUTPUT ;
    USE SIGNAL ;
    PORT
      LAYER M4 ;
        RECT  0 161.136 0.084 161.16 ;
    END
  END q[141]
  PIN q[142]
    DIRECTION OUTPUT ;
    USE SIGNAL ;
    PORT
      LAYER M4 ;
        RECT  0 161.232 0.084 161.256 ;
    END
  END q[142]
  PIN q[143]
    DIRECTION OUTPUT ;
    USE SIGNAL ;
    PORT
      LAYER M4 ;
        RECT  0 161.328 0.084 161.352 ;
    END
  END q[143]
  PIN q[144]
    DIRECTION OUTPUT ;
    USE SIGNAL ;
    PORT
      LAYER M4 ;
        RECT  0 161.424 0.084 161.448 ;
    END
  END q[144]
  PIN q[145]
    DIRECTION OUTPUT ;
    USE SIGNAL ;
    PORT
      LAYER M4 ;
        RECT  0 161.52 0.084 161.544 ;
    END
  END q[145]
  PIN q[146]
    DIRECTION OUTPUT ;
    USE SIGNAL ;
    PORT
      LAYER M4 ;
        RECT  0 161.616 0.084 161.64 ;
    END
  END q[146]
  PIN q[147]
    DIRECTION OUTPUT ;
    USE SIGNAL ;
    PORT
      LAYER M4 ;
        RECT  0 161.712 0.084 161.736 ;
    END
  END q[147]
  PIN q[148]
    DIRECTION OUTPUT ;
    USE SIGNAL ;
    PORT
      LAYER M4 ;
        RECT  0 161.808 0.084 161.832 ;
    END
  END q[148]
  PIN q[149]
    DIRECTION OUTPUT ;
    USE SIGNAL ;
    PORT
      LAYER M4 ;
        RECT  0 161.904 0.084 161.928 ;
    END
  END q[149]
  PIN q[14]
    DIRECTION OUTPUT ;
    USE SIGNAL ;
    PORT
      LAYER M4 ;
        RECT  0 170.448 0.084 170.472 ;
    END
  END q[14]
  PIN q[150]
    DIRECTION OUTPUT ;
    USE SIGNAL ;
    PORT
      LAYER M4 ;
        RECT  0 162 0.084 162.024 ;
    END
  END q[150]
  PIN q[151]
    DIRECTION OUTPUT ;
    USE SIGNAL ;
    PORT
      LAYER M4 ;
        RECT  0 162.096 0.084 162.12 ;
    END
  END q[151]
  PIN q[152]
    DIRECTION OUTPUT ;
    USE SIGNAL ;
    PORT
      LAYER M4 ;
        RECT  0 162.192 0.084 162.216 ;
    END
  END q[152]
  PIN q[153]
    DIRECTION OUTPUT ;
    USE SIGNAL ;
    PORT
      LAYER M4 ;
        RECT  0 162.288 0.084 162.312 ;
    END
  END q[153]
  PIN q[154]
    DIRECTION OUTPUT ;
    USE SIGNAL ;
    PORT
      LAYER M4 ;
        RECT  0 162.384 0.084 162.408 ;
    END
  END q[154]
  PIN q[155]
    DIRECTION OUTPUT ;
    USE SIGNAL ;
    PORT
      LAYER M4 ;
        RECT  0 162.48 0.084 162.504 ;
    END
  END q[155]
  PIN q[156]
    DIRECTION OUTPUT ;
    USE SIGNAL ;
    PORT
      LAYER M4 ;
        RECT  0 162.576 0.084 162.6 ;
    END
  END q[156]
  PIN q[157]
    DIRECTION OUTPUT ;
    USE SIGNAL ;
    PORT
      LAYER M4 ;
        RECT  0 162.672 0.084 162.696 ;
    END
  END q[157]
  PIN q[158]
    DIRECTION OUTPUT ;
    USE SIGNAL ;
    PORT
      LAYER M4 ;
        RECT  0 162.768 0.084 162.792 ;
    END
  END q[158]
  PIN q[159]
    DIRECTION OUTPUT ;
    USE SIGNAL ;
    PORT
      LAYER M4 ;
        RECT  0 162.864 0.084 162.888 ;
    END
  END q[159]
  PIN q[15]
    DIRECTION OUTPUT ;
    USE SIGNAL ;
    PORT
      LAYER M4 ;
        RECT  0 170.544 0.084 170.568 ;
    END
  END q[15]
  PIN q[160]
    DIRECTION OUTPUT ;
    USE SIGNAL ;
    PORT
      LAYER M4 ;
        RECT  0 162.96 0.084 162.984 ;
    END
  END q[160]
  PIN q[161]
    DIRECTION OUTPUT ;
    USE SIGNAL ;
    PORT
      LAYER M4 ;
        RECT  0 163.056 0.084 163.08 ;
    END
  END q[161]
  PIN q[162]
    DIRECTION OUTPUT ;
    USE SIGNAL ;
    PORT
      LAYER M4 ;
        RECT  0 163.152 0.084 163.176 ;
    END
  END q[162]
  PIN q[163]
    DIRECTION OUTPUT ;
    USE SIGNAL ;
    PORT
      LAYER M4 ;
        RECT  0 163.248 0.084 163.272 ;
    END
  END q[163]
  PIN q[164]
    DIRECTION OUTPUT ;
    USE SIGNAL ;
    PORT
      LAYER M4 ;
        RECT  0 163.344 0.084 163.368 ;
    END
  END q[164]
  PIN q[165]
    DIRECTION OUTPUT ;
    USE SIGNAL ;
    PORT
      LAYER M4 ;
        RECT  0 163.44 0.084 163.464 ;
    END
  END q[165]
  PIN q[166]
    DIRECTION OUTPUT ;
    USE SIGNAL ;
    PORT
      LAYER M4 ;
        RECT  0 163.536 0.084 163.56 ;
    END
  END q[166]
  PIN q[167]
    DIRECTION OUTPUT ;
    USE SIGNAL ;
    PORT
      LAYER M4 ;
        RECT  0 163.632 0.084 163.656 ;
    END
  END q[167]
  PIN q[168]
    DIRECTION OUTPUT ;
    USE SIGNAL ;
    PORT
      LAYER M4 ;
        RECT  0 163.728 0.084 163.752 ;
    END
  END q[168]
  PIN q[169]
    DIRECTION OUTPUT ;
    USE SIGNAL ;
    PORT
      LAYER M4 ;
        RECT  0 163.824 0.084 163.848 ;
    END
  END q[169]
  PIN q[16]
    DIRECTION OUTPUT ;
    USE SIGNAL ;
    PORT
      LAYER M4 ;
        RECT  0 170.64 0.084 170.664 ;
    END
  END q[16]
  PIN q[170]
    DIRECTION OUTPUT ;
    USE SIGNAL ;
    PORT
      LAYER M4 ;
        RECT  0 163.92 0.084 163.944 ;
    END
  END q[170]
  PIN q[171]
    DIRECTION OUTPUT ;
    USE SIGNAL ;
    PORT
      LAYER M4 ;
        RECT  0 164.016 0.084 164.04 ;
    END
  END q[171]
  PIN q[172]
    DIRECTION OUTPUT ;
    USE SIGNAL ;
    PORT
      LAYER M4 ;
        RECT  0 164.112 0.084 164.136 ;
    END
  END q[172]
  PIN q[173]
    DIRECTION OUTPUT ;
    USE SIGNAL ;
    PORT
      LAYER M4 ;
        RECT  0 164.208 0.084 164.232 ;
    END
  END q[173]
  PIN q[174]
    DIRECTION OUTPUT ;
    USE SIGNAL ;
    PORT
      LAYER M4 ;
        RECT  0 164.304 0.084 164.328 ;
    END
  END q[174]
  PIN q[175]
    DIRECTION OUTPUT ;
    USE SIGNAL ;
    PORT
      LAYER M4 ;
        RECT  0 164.4 0.084 164.424 ;
    END
  END q[175]
  PIN q[176]
    DIRECTION OUTPUT ;
    USE SIGNAL ;
    PORT
      LAYER M4 ;
        RECT  0 164.496 0.084 164.52 ;
    END
  END q[176]
  PIN q[177]
    DIRECTION OUTPUT ;
    USE SIGNAL ;
    PORT
      LAYER M4 ;
        RECT  0 164.592 0.084 164.616 ;
    END
  END q[177]
  PIN q[178]
    DIRECTION OUTPUT ;
    USE SIGNAL ;
    PORT
      LAYER M4 ;
        RECT  0 164.688 0.084 164.712 ;
    END
  END q[178]
  PIN q[179]
    DIRECTION OUTPUT ;
    USE SIGNAL ;
    PORT
      LAYER M4 ;
        RECT  0 164.784 0.084 164.808 ;
    END
  END q[179]
  PIN q[17]
    DIRECTION OUTPUT ;
    USE SIGNAL ;
    PORT
      LAYER M4 ;
        RECT  0 170.736 0.084 170.76 ;
    END
  END q[17]
  PIN q[180]
    DIRECTION OUTPUT ;
    USE SIGNAL ;
    PORT
      LAYER M4 ;
        RECT  0 164.88 0.084 164.904 ;
    END
  END q[180]
  PIN q[181]
    DIRECTION OUTPUT ;
    USE SIGNAL ;
    PORT
      LAYER M4 ;
        RECT  0 164.976 0.084 165 ;
    END
  END q[181]
  PIN q[182]
    DIRECTION OUTPUT ;
    USE SIGNAL ;
    PORT
      LAYER M4 ;
        RECT  0 165.072 0.084 165.096 ;
    END
  END q[182]
  PIN q[183]
    DIRECTION OUTPUT ;
    USE SIGNAL ;
    PORT
      LAYER M4 ;
        RECT  0 165.168 0.084 165.192 ;
    END
  END q[183]
  PIN q[184]
    DIRECTION OUTPUT ;
    USE SIGNAL ;
    PORT
      LAYER M4 ;
        RECT  0 165.264 0.084 165.288 ;
    END
  END q[184]
  PIN q[185]
    DIRECTION OUTPUT ;
    USE SIGNAL ;
    PORT
      LAYER M4 ;
        RECT  0 165.36 0.084 165.384 ;
    END
  END q[185]
  PIN q[186]
    DIRECTION OUTPUT ;
    USE SIGNAL ;
    PORT
      LAYER M4 ;
        RECT  0 165.456 0.084 165.48 ;
    END
  END q[186]
  PIN q[187]
    DIRECTION OUTPUT ;
    USE SIGNAL ;
    PORT
      LAYER M4 ;
        RECT  0 165.552 0.084 165.576 ;
    END
  END q[187]
  PIN q[188]
    DIRECTION OUTPUT ;
    USE SIGNAL ;
    PORT
      LAYER M4 ;
        RECT  0 165.648 0.084 165.672 ;
    END
  END q[188]
  PIN q[189]
    DIRECTION OUTPUT ;
    USE SIGNAL ;
    PORT
      LAYER M4 ;
        RECT  0 165.744 0.084 165.768 ;
    END
  END q[189]
  PIN q[18]
    DIRECTION OUTPUT ;
    USE SIGNAL ;
    PORT
      LAYER M4 ;
        RECT  0 170.832 0.084 170.856 ;
    END
  END q[18]
  PIN q[190]
    DIRECTION OUTPUT ;
    USE SIGNAL ;
    PORT
      LAYER M4 ;
        RECT  0 165.84 0.084 165.864 ;
    END
  END q[190]
  PIN q[191]
    DIRECTION OUTPUT ;
    USE SIGNAL ;
    PORT
      LAYER M4 ;
        RECT  0 165.936 0.084 165.96 ;
    END
  END q[191]
  PIN q[192]
    DIRECTION OUTPUT ;
    USE SIGNAL ;
    PORT
      LAYER M4 ;
        RECT  0 179.088 0.084 179.112 ;
    END
  END q[192]
  PIN q[193]
    DIRECTION OUTPUT ;
    USE SIGNAL ;
    PORT
      LAYER M4 ;
        RECT  0 179.184 0.084 179.208 ;
    END
  END q[193]
  PIN q[194]
    DIRECTION OUTPUT ;
    USE SIGNAL ;
    PORT
      LAYER M4 ;
        RECT  0 179.28 0.084 179.304 ;
    END
  END q[194]
  PIN q[195]
    DIRECTION OUTPUT ;
    USE SIGNAL ;
    PORT
      LAYER M4 ;
        RECT  0 179.376 0.084 179.4 ;
    END
  END q[195]
  PIN q[196]
    DIRECTION OUTPUT ;
    USE SIGNAL ;
    PORT
      LAYER M4 ;
        RECT  0 179.472 0.084 179.496 ;
    END
  END q[196]
  PIN q[197]
    DIRECTION OUTPUT ;
    USE SIGNAL ;
    PORT
      LAYER M4 ;
        RECT  0 179.568 0.084 179.592 ;
    END
  END q[197]
  PIN q[198]
    DIRECTION OUTPUT ;
    USE SIGNAL ;
    PORT
      LAYER M4 ;
        RECT  0 179.664 0.084 179.688 ;
    END
  END q[198]
  PIN q[199]
    DIRECTION OUTPUT ;
    USE SIGNAL ;
    PORT
      LAYER M4 ;
        RECT  0 179.76 0.084 179.784 ;
    END
  END q[199]
  PIN q[19]
    DIRECTION OUTPUT ;
    USE SIGNAL ;
    PORT
      LAYER M4 ;
        RECT  0 170.928 0.084 170.952 ;
    END
  END q[19]
  PIN q[1]
    DIRECTION OUTPUT ;
    USE SIGNAL ;
    PORT
      LAYER M4 ;
        RECT  0 169.2 0.084 169.224 ;
    END
  END q[1]
  PIN q[200]
    DIRECTION OUTPUT ;
    USE SIGNAL ;
    PORT
      LAYER M4 ;
        RECT  0 179.856 0.084 179.88 ;
    END
  END q[200]
  PIN q[201]
    DIRECTION OUTPUT ;
    USE SIGNAL ;
    PORT
      LAYER M4 ;
        RECT  0 179.952 0.084 179.976 ;
    END
  END q[201]
  PIN q[202]
    DIRECTION OUTPUT ;
    USE SIGNAL ;
    PORT
      LAYER M4 ;
        RECT  0 180.048 0.084 180.072 ;
    END
  END q[202]
  PIN q[203]
    DIRECTION OUTPUT ;
    USE SIGNAL ;
    PORT
      LAYER M4 ;
        RECT  0 180.144 0.084 180.168 ;
    END
  END q[203]
  PIN q[204]
    DIRECTION OUTPUT ;
    USE SIGNAL ;
    PORT
      LAYER M4 ;
        RECT  0 180.24 0.084 180.264 ;
    END
  END q[204]
  PIN q[205]
    DIRECTION OUTPUT ;
    USE SIGNAL ;
    PORT
      LAYER M4 ;
        RECT  0 180.336 0.084 180.36 ;
    END
  END q[205]
  PIN q[206]
    DIRECTION OUTPUT ;
    USE SIGNAL ;
    PORT
      LAYER M4 ;
        RECT  0 180.432 0.084 180.456 ;
    END
  END q[206]
  PIN q[207]
    DIRECTION OUTPUT ;
    USE SIGNAL ;
    PORT
      LAYER M4 ;
        RECT  0 180.528 0.084 180.552 ;
    END
  END q[207]
  PIN q[208]
    DIRECTION OUTPUT ;
    USE SIGNAL ;
    PORT
      LAYER M4 ;
        RECT  0 180.624 0.084 180.648 ;
    END
  END q[208]
  PIN q[209]
    DIRECTION OUTPUT ;
    USE SIGNAL ;
    PORT
      LAYER M4 ;
        RECT  0 180.72 0.084 180.744 ;
    END
  END q[209]
  PIN q[20]
    DIRECTION OUTPUT ;
    USE SIGNAL ;
    PORT
      LAYER M4 ;
        RECT  0 171.024 0.084 171.048 ;
    END
  END q[20]
  PIN q[210]
    DIRECTION OUTPUT ;
    USE SIGNAL ;
    PORT
      LAYER M4 ;
        RECT  0 180.816 0.084 180.84 ;
    END
  END q[210]
  PIN q[211]
    DIRECTION OUTPUT ;
    USE SIGNAL ;
    PORT
      LAYER M4 ;
        RECT  0 180.912 0.084 180.936 ;
    END
  END q[211]
  PIN q[212]
    DIRECTION OUTPUT ;
    USE SIGNAL ;
    PORT
      LAYER M4 ;
        RECT  0 181.008 0.084 181.032 ;
    END
  END q[212]
  PIN q[213]
    DIRECTION OUTPUT ;
    USE SIGNAL ;
    PORT
      LAYER M4 ;
        RECT  0 181.104 0.084 181.128 ;
    END
  END q[213]
  PIN q[214]
    DIRECTION OUTPUT ;
    USE SIGNAL ;
    PORT
      LAYER M4 ;
        RECT  0 181.2 0.084 181.224 ;
    END
  END q[214]
  PIN q[215]
    DIRECTION OUTPUT ;
    USE SIGNAL ;
    PORT
      LAYER M4 ;
        RECT  0 181.296 0.084 181.32 ;
    END
  END q[215]
  PIN q[216]
    DIRECTION OUTPUT ;
    USE SIGNAL ;
    PORT
      LAYER M4 ;
        RECT  0 181.392 0.084 181.416 ;
    END
  END q[216]
  PIN q[217]
    DIRECTION OUTPUT ;
    USE SIGNAL ;
    PORT
      LAYER M4 ;
        RECT  0 181.488 0.084 181.512 ;
    END
  END q[217]
  PIN q[218]
    DIRECTION OUTPUT ;
    USE SIGNAL ;
    PORT
      LAYER M4 ;
        RECT  0 181.584 0.084 181.608 ;
    END
  END q[218]
  PIN q[219]
    DIRECTION OUTPUT ;
    USE SIGNAL ;
    PORT
      LAYER M4 ;
        RECT  0 181.68 0.084 181.704 ;
    END
  END q[219]
  PIN q[21]
    DIRECTION OUTPUT ;
    USE SIGNAL ;
    PORT
      LAYER M4 ;
        RECT  0 171.12 0.084 171.144 ;
    END
  END q[21]
  PIN q[220]
    DIRECTION OUTPUT ;
    USE SIGNAL ;
    PORT
      LAYER M4 ;
        RECT  0 181.776 0.084 181.8 ;
    END
  END q[220]
  PIN q[221]
    DIRECTION OUTPUT ;
    USE SIGNAL ;
    PORT
      LAYER M4 ;
        RECT  0 181.872 0.084 181.896 ;
    END
  END q[221]
  PIN q[222]
    DIRECTION OUTPUT ;
    USE SIGNAL ;
    PORT
      LAYER M4 ;
        RECT  0 181.968 0.084 181.992 ;
    END
  END q[222]
  PIN q[223]
    DIRECTION OUTPUT ;
    USE SIGNAL ;
    PORT
      LAYER M4 ;
        RECT  0 182.064 0.084 182.088 ;
    END
  END q[223]
  PIN q[224]
    DIRECTION OUTPUT ;
    USE SIGNAL ;
    PORT
      LAYER M4 ;
        RECT  0 176.016 0.084 176.04 ;
    END
  END q[224]
  PIN q[225]
    DIRECTION OUTPUT ;
    USE SIGNAL ;
    PORT
      LAYER M4 ;
        RECT  0 176.112 0.084 176.136 ;
    END
  END q[225]
  PIN q[226]
    DIRECTION OUTPUT ;
    USE SIGNAL ;
    PORT
      LAYER M4 ;
        RECT  0 176.208 0.084 176.232 ;
    END
  END q[226]
  PIN q[227]
    DIRECTION OUTPUT ;
    USE SIGNAL ;
    PORT
      LAYER M4 ;
        RECT  0 176.304 0.084 176.328 ;
    END
  END q[227]
  PIN q[228]
    DIRECTION OUTPUT ;
    USE SIGNAL ;
    PORT
      LAYER M4 ;
        RECT  0 176.4 0.084 176.424 ;
    END
  END q[228]
  PIN q[229]
    DIRECTION OUTPUT ;
    USE SIGNAL ;
    PORT
      LAYER M4 ;
        RECT  0 176.496 0.084 176.52 ;
    END
  END q[229]
  PIN q[22]
    DIRECTION OUTPUT ;
    USE SIGNAL ;
    PORT
      LAYER M4 ;
        RECT  0 171.216 0.084 171.24 ;
    END
  END q[22]
  PIN q[230]
    DIRECTION OUTPUT ;
    USE SIGNAL ;
    PORT
      LAYER M4 ;
        RECT  0 176.592 0.084 176.616 ;
    END
  END q[230]
  PIN q[231]
    DIRECTION OUTPUT ;
    USE SIGNAL ;
    PORT
      LAYER M4 ;
        RECT  0 176.688 0.084 176.712 ;
    END
  END q[231]
  PIN q[232]
    DIRECTION OUTPUT ;
    USE SIGNAL ;
    PORT
      LAYER M4 ;
        RECT  0 176.784 0.084 176.808 ;
    END
  END q[232]
  PIN q[233]
    DIRECTION OUTPUT ;
    USE SIGNAL ;
    PORT
      LAYER M4 ;
        RECT  0 176.88 0.084 176.904 ;
    END
  END q[233]
  PIN q[234]
    DIRECTION OUTPUT ;
    USE SIGNAL ;
    PORT
      LAYER M4 ;
        RECT  0 176.976 0.084 177 ;
    END
  END q[234]
  PIN q[235]
    DIRECTION OUTPUT ;
    USE SIGNAL ;
    PORT
      LAYER M4 ;
        RECT  0 177.072 0.084 177.096 ;
    END
  END q[235]
  PIN q[236]
    DIRECTION OUTPUT ;
    USE SIGNAL ;
    PORT
      LAYER M4 ;
        RECT  0 177.168 0.084 177.192 ;
    END
  END q[236]
  PIN q[237]
    DIRECTION OUTPUT ;
    USE SIGNAL ;
    PORT
      LAYER M4 ;
        RECT  0 177.264 0.084 177.288 ;
    END
  END q[237]
  PIN q[238]
    DIRECTION OUTPUT ;
    USE SIGNAL ;
    PORT
      LAYER M4 ;
        RECT  0 177.36 0.084 177.384 ;
    END
  END q[238]
  PIN q[239]
    DIRECTION OUTPUT ;
    USE SIGNAL ;
    PORT
      LAYER M4 ;
        RECT  0 177.456 0.084 177.48 ;
    END
  END q[239]
  PIN q[23]
    DIRECTION OUTPUT ;
    USE SIGNAL ;
    PORT
      LAYER M4 ;
        RECT  0 171.312 0.084 171.336 ;
    END
  END q[23]
  PIN q[240]
    DIRECTION OUTPUT ;
    USE SIGNAL ;
    PORT
      LAYER M4 ;
        RECT  0 177.552 0.084 177.576 ;
    END
  END q[240]
  PIN q[241]
    DIRECTION OUTPUT ;
    USE SIGNAL ;
    PORT
      LAYER M4 ;
        RECT  0 177.648 0.084 177.672 ;
    END
  END q[241]
  PIN q[242]
    DIRECTION OUTPUT ;
    USE SIGNAL ;
    PORT
      LAYER M4 ;
        RECT  0 177.744 0.084 177.768 ;
    END
  END q[242]
  PIN q[243]
    DIRECTION OUTPUT ;
    USE SIGNAL ;
    PORT
      LAYER M4 ;
        RECT  0 177.84 0.084 177.864 ;
    END
  END q[243]
  PIN q[244]
    DIRECTION OUTPUT ;
    USE SIGNAL ;
    PORT
      LAYER M4 ;
        RECT  0 177.936 0.084 177.96 ;
    END
  END q[244]
  PIN q[245]
    DIRECTION OUTPUT ;
    USE SIGNAL ;
    PORT
      LAYER M4 ;
        RECT  0 178.032 0.084 178.056 ;
    END
  END q[245]
  PIN q[246]
    DIRECTION OUTPUT ;
    USE SIGNAL ;
    PORT
      LAYER M4 ;
        RECT  0 178.128 0.084 178.152 ;
    END
  END q[246]
  PIN q[247]
    DIRECTION OUTPUT ;
    USE SIGNAL ;
    PORT
      LAYER M4 ;
        RECT  0 178.224 0.084 178.248 ;
    END
  END q[247]
  PIN q[248]
    DIRECTION OUTPUT ;
    USE SIGNAL ;
    PORT
      LAYER M4 ;
        RECT  0 178.32 0.084 178.344 ;
    END
  END q[248]
  PIN q[249]
    DIRECTION OUTPUT ;
    USE SIGNAL ;
    PORT
      LAYER M4 ;
        RECT  0 178.416 0.084 178.44 ;
    END
  END q[249]
  PIN q[24]
    DIRECTION OUTPUT ;
    USE SIGNAL ;
    PORT
      LAYER M4 ;
        RECT  0 171.408 0.084 171.432 ;
    END
  END q[24]
  PIN q[250]
    DIRECTION OUTPUT ;
    USE SIGNAL ;
    PORT
      LAYER M4 ;
        RECT  0 178.512 0.084 178.536 ;
    END
  END q[250]
  PIN q[251]
    DIRECTION OUTPUT ;
    USE SIGNAL ;
    PORT
      LAYER M4 ;
        RECT  0 178.608 0.084 178.632 ;
    END
  END q[251]
  PIN q[252]
    DIRECTION OUTPUT ;
    USE SIGNAL ;
    PORT
      LAYER M4 ;
        RECT  0 178.704 0.084 178.728 ;
    END
  END q[252]
  PIN q[253]
    DIRECTION OUTPUT ;
    USE SIGNAL ;
    PORT
      LAYER M4 ;
        RECT  0 178.8 0.084 178.824 ;
    END
  END q[253]
  PIN q[254]
    DIRECTION OUTPUT ;
    USE SIGNAL ;
    PORT
      LAYER M4 ;
        RECT  0 178.896 0.084 178.92 ;
    END
  END q[254]
  PIN q[255]
    DIRECTION OUTPUT ;
    USE SIGNAL ;
    PORT
      LAYER M4 ;
        RECT  0 178.992 0.084 179.016 ;
    END
  END q[255]
  PIN q[25]
    DIRECTION OUTPUT ;
    USE SIGNAL ;
    PORT
      LAYER M4 ;
        RECT  0 171.504 0.084 171.528 ;
    END
  END q[25]
  PIN q[26]
    DIRECTION OUTPUT ;
    USE SIGNAL ;
    PORT
      LAYER M4 ;
        RECT  0 171.6 0.084 171.624 ;
    END
  END q[26]
  PIN q[27]
    DIRECTION OUTPUT ;
    USE SIGNAL ;
    PORT
      LAYER M4 ;
        RECT  0 171.696 0.084 171.72 ;
    END
  END q[27]
  PIN q[28]
    DIRECTION OUTPUT ;
    USE SIGNAL ;
    PORT
      LAYER M4 ;
        RECT  0 171.792 0.084 171.816 ;
    END
  END q[28]
  PIN q[29]
    DIRECTION OUTPUT ;
    USE SIGNAL ;
    PORT
      LAYER M4 ;
        RECT  0 171.888 0.084 171.912 ;
    END
  END q[29]
  PIN q[2]
    DIRECTION OUTPUT ;
    USE SIGNAL ;
    PORT
      LAYER M4 ;
        RECT  0 169.296 0.084 169.32 ;
    END
  END q[2]
  PIN q[30]
    DIRECTION OUTPUT ;
    USE SIGNAL ;
    PORT
      LAYER M4 ;
        RECT  0 171.984 0.084 172.008 ;
    END
  END q[30]
  PIN q[31]
    DIRECTION OUTPUT ;
    USE SIGNAL ;
    PORT
      LAYER M4 ;
        RECT  0 172.08 0.084 172.104 ;
    END
  END q[31]
  PIN q[32]
    DIRECTION OUTPUT ;
    USE SIGNAL ;
    PORT
      LAYER M4 ;
        RECT  0 172.176 0.084 172.2 ;
    END
  END q[32]
  PIN q[33]
    DIRECTION OUTPUT ;
    USE SIGNAL ;
    PORT
      LAYER M4 ;
        RECT  0 172.272 0.084 172.296 ;
    END
  END q[33]
  PIN q[34]
    DIRECTION OUTPUT ;
    USE SIGNAL ;
    PORT
      LAYER M4 ;
        RECT  0 172.368 0.084 172.392 ;
    END
  END q[34]
  PIN q[35]
    DIRECTION OUTPUT ;
    USE SIGNAL ;
    PORT
      LAYER M4 ;
        RECT  0 172.464 0.084 172.488 ;
    END
  END q[35]
  PIN q[36]
    DIRECTION OUTPUT ;
    USE SIGNAL ;
    PORT
      LAYER M4 ;
        RECT  0 172.56 0.084 172.584 ;
    END
  END q[36]
  PIN q[37]
    DIRECTION OUTPUT ;
    USE SIGNAL ;
    PORT
      LAYER M4 ;
        RECT  0 172.656 0.084 172.68 ;
    END
  END q[37]
  PIN q[38]
    DIRECTION OUTPUT ;
    USE SIGNAL ;
    PORT
      LAYER M4 ;
        RECT  0 172.752 0.084 172.776 ;
    END
  END q[38]
  PIN q[39]
    DIRECTION OUTPUT ;
    USE SIGNAL ;
    PORT
      LAYER M4 ;
        RECT  0 172.848 0.084 172.872 ;
    END
  END q[39]
  PIN q[3]
    DIRECTION OUTPUT ;
    USE SIGNAL ;
    PORT
      LAYER M4 ;
        RECT  0 169.392 0.084 169.416 ;
    END
  END q[3]
  PIN q[40]
    DIRECTION OUTPUT ;
    USE SIGNAL ;
    PORT
      LAYER M4 ;
        RECT  0 172.944 0.084 172.968 ;
    END
  END q[40]
  PIN q[41]
    DIRECTION OUTPUT ;
    USE SIGNAL ;
    PORT
      LAYER M4 ;
        RECT  0 173.04 0.084 173.064 ;
    END
  END q[41]
  PIN q[42]
    DIRECTION OUTPUT ;
    USE SIGNAL ;
    PORT
      LAYER M4 ;
        RECT  0 173.136 0.084 173.16 ;
    END
  END q[42]
  PIN q[43]
    DIRECTION OUTPUT ;
    USE SIGNAL ;
    PORT
      LAYER M4 ;
        RECT  0 173.232 0.084 173.256 ;
    END
  END q[43]
  PIN q[44]
    DIRECTION OUTPUT ;
    USE SIGNAL ;
    PORT
      LAYER M4 ;
        RECT  0 173.328 0.084 173.352 ;
    END
  END q[44]
  PIN q[45]
    DIRECTION OUTPUT ;
    USE SIGNAL ;
    PORT
      LAYER M4 ;
        RECT  0 173.424 0.084 173.448 ;
    END
  END q[45]
  PIN q[46]
    DIRECTION OUTPUT ;
    USE SIGNAL ;
    PORT
      LAYER M4 ;
        RECT  0 173.52 0.084 173.544 ;
    END
  END q[46]
  PIN q[47]
    DIRECTION OUTPUT ;
    USE SIGNAL ;
    PORT
      LAYER M4 ;
        RECT  0 173.616 0.084 173.64 ;
    END
  END q[47]
  PIN q[48]
    DIRECTION OUTPUT ;
    USE SIGNAL ;
    PORT
      LAYER M4 ;
        RECT  0 173.712 0.084 173.736 ;
    END
  END q[48]
  PIN q[49]
    DIRECTION OUTPUT ;
    USE SIGNAL ;
    PORT
      LAYER M4 ;
        RECT  0 173.808 0.084 173.832 ;
    END
  END q[49]
  PIN q[4]
    DIRECTION OUTPUT ;
    USE SIGNAL ;
    PORT
      LAYER M4 ;
        RECT  0 169.488 0.084 169.512 ;
    END
  END q[4]
  PIN q[50]
    DIRECTION OUTPUT ;
    USE SIGNAL ;
    PORT
      LAYER M4 ;
        RECT  0 173.904 0.084 173.928 ;
    END
  END q[50]
  PIN q[51]
    DIRECTION OUTPUT ;
    USE SIGNAL ;
    PORT
      LAYER M4 ;
        RECT  0 174 0.084 174.024 ;
    END
  END q[51]
  PIN q[52]
    DIRECTION OUTPUT ;
    USE SIGNAL ;
    PORT
      LAYER M4 ;
        RECT  0 174.096 0.084 174.12 ;
    END
  END q[52]
  PIN q[53]
    DIRECTION OUTPUT ;
    USE SIGNAL ;
    PORT
      LAYER M4 ;
        RECT  0 174.192 0.084 174.216 ;
    END
  END q[53]
  PIN q[54]
    DIRECTION OUTPUT ;
    USE SIGNAL ;
    PORT
      LAYER M4 ;
        RECT  0 174.288 0.084 174.312 ;
    END
  END q[54]
  PIN q[55]
    DIRECTION OUTPUT ;
    USE SIGNAL ;
    PORT
      LAYER M4 ;
        RECT  0 174.384 0.084 174.408 ;
    END
  END q[55]
  PIN q[56]
    DIRECTION OUTPUT ;
    USE SIGNAL ;
    PORT
      LAYER M4 ;
        RECT  0 174.48 0.084 174.504 ;
    END
  END q[56]
  PIN q[57]
    DIRECTION OUTPUT ;
    USE SIGNAL ;
    PORT
      LAYER M4 ;
        RECT  0 174.576 0.084 174.6 ;
    END
  END q[57]
  PIN q[58]
    DIRECTION OUTPUT ;
    USE SIGNAL ;
    PORT
      LAYER M4 ;
        RECT  0 174.672 0.084 174.696 ;
    END
  END q[58]
  PIN q[59]
    DIRECTION OUTPUT ;
    USE SIGNAL ;
    PORT
      LAYER M4 ;
        RECT  0 174.768 0.084 174.792 ;
    END
  END q[59]
  PIN q[5]
    DIRECTION OUTPUT ;
    USE SIGNAL ;
    PORT
      LAYER M4 ;
        RECT  0 169.584 0.084 169.608 ;
    END
  END q[5]
  PIN q[60]
    DIRECTION OUTPUT ;
    USE SIGNAL ;
    PORT
      LAYER M4 ;
        RECT  0 174.864 0.084 174.888 ;
    END
  END q[60]
  PIN q[61]
    DIRECTION OUTPUT ;
    USE SIGNAL ;
    PORT
      LAYER M4 ;
        RECT  0 174.96 0.084 174.984 ;
    END
  END q[61]
  PIN q[62]
    DIRECTION OUTPUT ;
    USE SIGNAL ;
    PORT
      LAYER M4 ;
        RECT  0 175.056 0.084 175.08 ;
    END
  END q[62]
  PIN q[63]
    DIRECTION OUTPUT ;
    USE SIGNAL ;
    PORT
      LAYER M4 ;
        RECT  0 175.152 0.084 175.176 ;
    END
  END q[63]
  PIN q[64]
    DIRECTION OUTPUT ;
    USE SIGNAL ;
    PORT
      LAYER M4 ;
        RECT  0 156.816 0.084 156.84 ;
    END
  END q[64]
  PIN q[65]
    DIRECTION OUTPUT ;
    USE SIGNAL ;
    PORT
      LAYER M4 ;
        RECT  0 156.912 0.084 156.936 ;
    END
  END q[65]
  PIN q[66]
    DIRECTION OUTPUT ;
    USE SIGNAL ;
    PORT
      LAYER M4 ;
        RECT  0 157.008 0.084 157.032 ;
    END
  END q[66]
  PIN q[67]
    DIRECTION OUTPUT ;
    USE SIGNAL ;
    PORT
      LAYER M4 ;
        RECT  0 157.104 0.084 157.128 ;
    END
  END q[67]
  PIN q[68]
    DIRECTION OUTPUT ;
    USE SIGNAL ;
    PORT
      LAYER M4 ;
        RECT  0 157.2 0.084 157.224 ;
    END
  END q[68]
  PIN q[69]
    DIRECTION OUTPUT ;
    USE SIGNAL ;
    PORT
      LAYER M4 ;
        RECT  0 157.296 0.084 157.32 ;
    END
  END q[69]
  PIN q[6]
    DIRECTION OUTPUT ;
    USE SIGNAL ;
    PORT
      LAYER M4 ;
        RECT  0 169.68 0.084 169.704 ;
    END
  END q[6]
  PIN q[70]
    DIRECTION OUTPUT ;
    USE SIGNAL ;
    PORT
      LAYER M4 ;
        RECT  0 157.392 0.084 157.416 ;
    END
  END q[70]
  PIN q[71]
    DIRECTION OUTPUT ;
    USE SIGNAL ;
    PORT
      LAYER M4 ;
        RECT  0 157.488 0.084 157.512 ;
    END
  END q[71]
  PIN q[72]
    DIRECTION OUTPUT ;
    USE SIGNAL ;
    PORT
      LAYER M4 ;
        RECT  0 157.584 0.084 157.608 ;
    END
  END q[72]
  PIN q[73]
    DIRECTION OUTPUT ;
    USE SIGNAL ;
    PORT
      LAYER M4 ;
        RECT  0 157.68 0.084 157.704 ;
    END
  END q[73]
  PIN q[74]
    DIRECTION OUTPUT ;
    USE SIGNAL ;
    PORT
      LAYER M4 ;
        RECT  0 157.776 0.084 157.8 ;
    END
  END q[74]
  PIN q[75]
    DIRECTION OUTPUT ;
    USE SIGNAL ;
    PORT
      LAYER M4 ;
        RECT  0 157.872 0.084 157.896 ;
    END
  END q[75]
  PIN q[76]
    DIRECTION OUTPUT ;
    USE SIGNAL ;
    PORT
      LAYER M4 ;
        RECT  0 157.968 0.084 157.992 ;
    END
  END q[76]
  PIN q[77]
    DIRECTION OUTPUT ;
    USE SIGNAL ;
    PORT
      LAYER M4 ;
        RECT  0 158.064 0.084 158.088 ;
    END
  END q[77]
  PIN q[78]
    DIRECTION OUTPUT ;
    USE SIGNAL ;
    PORT
      LAYER M4 ;
        RECT  0 158.16 0.084 158.184 ;
    END
  END q[78]
  PIN q[79]
    DIRECTION OUTPUT ;
    USE SIGNAL ;
    PORT
      LAYER M4 ;
        RECT  0 158.256 0.084 158.28 ;
    END
  END q[79]
  PIN q[7]
    DIRECTION OUTPUT ;
    USE SIGNAL ;
    PORT
      LAYER M4 ;
        RECT  0 169.776 0.084 169.8 ;
    END
  END q[7]
  PIN q[80]
    DIRECTION OUTPUT ;
    USE SIGNAL ;
    PORT
      LAYER M4 ;
        RECT  0 158.352 0.084 158.376 ;
    END
  END q[80]
  PIN q[81]
    DIRECTION OUTPUT ;
    USE SIGNAL ;
    PORT
      LAYER M4 ;
        RECT  0 158.448 0.084 158.472 ;
    END
  END q[81]
  PIN q[82]
    DIRECTION OUTPUT ;
    USE SIGNAL ;
    PORT
      LAYER M4 ;
        RECT  0 158.544 0.084 158.568 ;
    END
  END q[82]
  PIN q[83]
    DIRECTION OUTPUT ;
    USE SIGNAL ;
    PORT
      LAYER M4 ;
        RECT  0 158.64 0.084 158.664 ;
    END
  END q[83]
  PIN q[84]
    DIRECTION OUTPUT ;
    USE SIGNAL ;
    PORT
      LAYER M4 ;
        RECT  0 158.736 0.084 158.76 ;
    END
  END q[84]
  PIN q[85]
    DIRECTION OUTPUT ;
    USE SIGNAL ;
    PORT
      LAYER M4 ;
        RECT  0 158.832 0.084 158.856 ;
    END
  END q[85]
  PIN q[86]
    DIRECTION OUTPUT ;
    USE SIGNAL ;
    PORT
      LAYER M4 ;
        RECT  0 158.928 0.084 158.952 ;
    END
  END q[86]
  PIN q[87]
    DIRECTION OUTPUT ;
    USE SIGNAL ;
    PORT
      LAYER M4 ;
        RECT  0 159.024 0.084 159.048 ;
    END
  END q[87]
  PIN q[88]
    DIRECTION OUTPUT ;
    USE SIGNAL ;
    PORT
      LAYER M4 ;
        RECT  0 159.12 0.084 159.144 ;
    END
  END q[88]
  PIN q[89]
    DIRECTION OUTPUT ;
    USE SIGNAL ;
    PORT
      LAYER M4 ;
        RECT  0 159.216 0.084 159.24 ;
    END
  END q[89]
  PIN q[8]
    DIRECTION OUTPUT ;
    USE SIGNAL ;
    PORT
      LAYER M4 ;
        RECT  0 169.872 0.084 169.896 ;
    END
  END q[8]
  PIN q[90]
    DIRECTION OUTPUT ;
    USE SIGNAL ;
    PORT
      LAYER M4 ;
        RECT  0 159.312 0.084 159.336 ;
    END
  END q[90]
  PIN q[91]
    DIRECTION OUTPUT ;
    USE SIGNAL ;
    PORT
      LAYER M4 ;
        RECT  0 159.408 0.084 159.432 ;
    END
  END q[91]
  PIN q[92]
    DIRECTION OUTPUT ;
    USE SIGNAL ;
    PORT
      LAYER M4 ;
        RECT  0 159.504 0.084 159.528 ;
    END
  END q[92]
  PIN q[93]
    DIRECTION OUTPUT ;
    USE SIGNAL ;
    PORT
      LAYER M4 ;
        RECT  0 159.6 0.084 159.624 ;
    END
  END q[93]
  PIN q[94]
    DIRECTION OUTPUT ;
    USE SIGNAL ;
    PORT
      LAYER M4 ;
        RECT  0 159.696 0.084 159.72 ;
    END
  END q[94]
  PIN q[95]
    DIRECTION OUTPUT ;
    USE SIGNAL ;
    PORT
      LAYER M4 ;
        RECT  0 159.792 0.084 159.816 ;
    END
  END q[95]
  PIN q[96]
    DIRECTION OUTPUT ;
    USE SIGNAL ;
    PORT
      LAYER M4 ;
        RECT  0 166.032 0.084 166.056 ;
    END
  END q[96]
  PIN q[97]
    DIRECTION OUTPUT ;
    USE SIGNAL ;
    PORT
      LAYER M4 ;
        RECT  0 166.128 0.084 166.152 ;
    END
  END q[97]
  PIN q[98]
    DIRECTION OUTPUT ;
    USE SIGNAL ;
    PORT
      LAYER M4 ;
        RECT  0 166.224 0.084 166.248 ;
    END
  END q[98]
  PIN q[99]
    DIRECTION OUTPUT ;
    USE SIGNAL ;
    PORT
      LAYER M4 ;
        RECT  0 166.32 0.084 166.344 ;
    END
  END q[99]
  PIN q[9]
    DIRECTION OUTPUT ;
    USE SIGNAL ;
    PORT
      LAYER M4 ;
        RECT  0 169.968 0.084 169.992 ;
    END
  END q[9]
  PIN re[0]
    DIRECTION INPUT ;
    USE SIGNAL ;
    PORT
      LAYER M4 ;
        RECT  0 194.448 0.084 194.472 ;
    END
  END re[0]
  PIN re[1]
    DIRECTION INPUT ;
    USE SIGNAL ;
    PORT
      LAYER M4 ;
        RECT  0 194.544 0.084 194.568 ;
    END
  END re[1]
  PIN re[2]
    DIRECTION INPUT ;
    USE SIGNAL ;
    PORT
      LAYER M4 ;
        RECT  0 194.64 0.084 194.664 ;
    END
  END re[2]
  PIN re[3]
    DIRECTION INPUT ;
    USE SIGNAL ;
    PORT
      LAYER M4 ;
        RECT  0 194.736 0.084 194.76 ;
    END
  END re[3]
  PIN re[4]
    DIRECTION INPUT ;
    USE SIGNAL ;
    PORT
      LAYER M4 ;
        RECT  0 194.832 0.084 194.856 ;
    END
  END re[4]
  PIN re[5]
    DIRECTION INPUT ;
    USE SIGNAL ;
    PORT
      LAYER M4 ;
        RECT  0 194.928 0.084 194.952 ;
    END
  END re[5]
  PIN re[6]
    DIRECTION INPUT ;
    USE SIGNAL ;
    PORT
      LAYER M4 ;
        RECT  0 195.024 0.084 195.048 ;
    END
  END re[6]
  PIN re[7]
    DIRECTION INPUT ;
    USE SIGNAL ;
    PORT
      LAYER M4 ;
        RECT  0 195.12 0.084 195.144 ;
    END
  END re[7]
  PIN rst_n
    DIRECTION INPUT ;
    USE SIGNAL ;
    PORT
      LAYER M5 ;
        RECT  93.072 0 93.096 0.084 ;
    END
  END rst_n
  PIN vm_waddr[0]
    DIRECTION INPUT ;
    USE SIGNAL ;
    PORT
      LAYER M5 ;
        RECT  93.168 0 93.192 0.084 ;
    END
  END vm_waddr[0]
  PIN vm_waddr[100]
    DIRECTION INPUT ;
    USE SIGNAL ;
    PORT
      LAYER M5 ;
        RECT  90.48 0 90.504 0.084 ;
    END
  END vm_waddr[100]
  PIN vm_waddr[101]
    DIRECTION INPUT ;
    USE SIGNAL ;
    PORT
      LAYER M5 ;
        RECT  90.576 0 90.6 0.084 ;
    END
  END vm_waddr[101]
  PIN vm_waddr[102]
    DIRECTION INPUT ;
    USE SIGNAL ;
    PORT
      LAYER M5 ;
        RECT  90.672 0 90.696 0.084 ;
    END
  END vm_waddr[102]
  PIN vm_waddr[103]
    DIRECTION INPUT ;
    USE SIGNAL ;
    PORT
      LAYER M5 ;
        RECT  90.768 0 90.792 0.084 ;
    END
  END vm_waddr[103]
  PIN vm_waddr[104]
    DIRECTION INPUT ;
    USE SIGNAL ;
    PORT
      LAYER M5 ;
        RECT  90.864 0 90.888 0.084 ;
    END
  END vm_waddr[104]
  PIN vm_waddr[105]
    DIRECTION INPUT ;
    USE SIGNAL ;
    PORT
      LAYER M5 ;
        RECT  90.96 0 90.984 0.084 ;
    END
  END vm_waddr[105]
  PIN vm_waddr[106]
    DIRECTION INPUT ;
    USE SIGNAL ;
    PORT
      LAYER M5 ;
        RECT  91.056 0 91.08 0.084 ;
    END
  END vm_waddr[106]
  PIN vm_waddr[107]
    DIRECTION INPUT ;
    USE SIGNAL ;
    PORT
      LAYER M5 ;
        RECT  91.152 0 91.176 0.084 ;
    END
  END vm_waddr[107]
  PIN vm_waddr[108]
    DIRECTION INPUT ;
    USE SIGNAL ;
    PORT
      LAYER M5 ;
        RECT  91.248 0 91.272 0.084 ;
    END
  END vm_waddr[108]
  PIN vm_waddr[109]
    DIRECTION INPUT ;
    USE SIGNAL ;
    PORT
      LAYER M5 ;
        RECT  91.344 0 91.368 0.084 ;
    END
  END vm_waddr[109]
  PIN vm_waddr[10]
    DIRECTION INPUT ;
    USE SIGNAL ;
    PORT
      LAYER M5 ;
        RECT  94.128 0 94.152 0.084 ;
    END
  END vm_waddr[10]
  PIN vm_waddr[110]
    DIRECTION INPUT ;
    USE SIGNAL ;
    PORT
      LAYER M5 ;
        RECT  91.44 0 91.464 0.084 ;
    END
  END vm_waddr[110]
  PIN vm_waddr[111]
    DIRECTION INPUT ;
    USE SIGNAL ;
    PORT
      LAYER M5 ;
        RECT  91.536 0 91.56 0.084 ;
    END
  END vm_waddr[111]
  PIN vm_waddr[112]
    DIRECTION INPUT ;
    USE SIGNAL ;
    PORT
      LAYER M5 ;
        RECT  91.632 0 91.656 0.084 ;
    END
  END vm_waddr[112]
  PIN vm_waddr[113]
    DIRECTION INPUT ;
    USE SIGNAL ;
    PORT
      LAYER M5 ;
        RECT  91.728 0 91.752 0.084 ;
    END
  END vm_waddr[113]
  PIN vm_waddr[114]
    DIRECTION INPUT ;
    USE SIGNAL ;
    PORT
      LAYER M5 ;
        RECT  91.824 0 91.848 0.084 ;
    END
  END vm_waddr[114]
  PIN vm_waddr[115]
    DIRECTION INPUT ;
    USE SIGNAL ;
    PORT
      LAYER M5 ;
        RECT  91.92 0 91.944 0.084 ;
    END
  END vm_waddr[115]
  PIN vm_waddr[116]
    DIRECTION INPUT ;
    USE SIGNAL ;
    PORT
      LAYER M5 ;
        RECT  92.016 0 92.04 0.084 ;
    END
  END vm_waddr[116]
  PIN vm_waddr[117]
    DIRECTION INPUT ;
    USE SIGNAL ;
    PORT
      LAYER M5 ;
        RECT  92.112 0 92.136 0.084 ;
    END
  END vm_waddr[117]
  PIN vm_waddr[118]
    DIRECTION INPUT ;
    USE SIGNAL ;
    PORT
      LAYER M5 ;
        RECT  92.208 0 92.232 0.084 ;
    END
  END vm_waddr[118]
  PIN vm_waddr[119]
    DIRECTION INPUT ;
    USE SIGNAL ;
    PORT
      LAYER M5 ;
        RECT  92.304 0 92.328 0.084 ;
    END
  END vm_waddr[119]
  PIN vm_waddr[11]
    DIRECTION INPUT ;
    USE SIGNAL ;
    PORT
      LAYER M5 ;
        RECT  94.224 0 94.248 0.084 ;
    END
  END vm_waddr[11]
  PIN vm_waddr[120]
    DIRECTION INPUT ;
    USE SIGNAL ;
    PORT
      LAYER M5 ;
        RECT  92.4 0 92.424 0.084 ;
    END
  END vm_waddr[120]
  PIN vm_waddr[121]
    DIRECTION INPUT ;
    USE SIGNAL ;
    PORT
      LAYER M5 ;
        RECT  92.496 0 92.52 0.084 ;
    END
  END vm_waddr[121]
  PIN vm_waddr[122]
    DIRECTION INPUT ;
    USE SIGNAL ;
    PORT
      LAYER M5 ;
        RECT  92.592 0 92.616 0.084 ;
    END
  END vm_waddr[122]
  PIN vm_waddr[123]
    DIRECTION INPUT ;
    USE SIGNAL ;
    PORT
      LAYER M5 ;
        RECT  92.688 0 92.712 0.084 ;
    END
  END vm_waddr[123]
  PIN vm_waddr[124]
    DIRECTION INPUT ;
    USE SIGNAL ;
    PORT
      LAYER M5 ;
        RECT  92.784 0 92.808 0.084 ;
    END
  END vm_waddr[124]
  PIN vm_waddr[125]
    DIRECTION INPUT ;
    USE SIGNAL ;
    PORT
      LAYER M5 ;
        RECT  86.736 0 86.76 0.084 ;
    END
  END vm_waddr[125]
  PIN vm_waddr[126]
    DIRECTION INPUT ;
    USE SIGNAL ;
    PORT
      LAYER M5 ;
        RECT  86.832 0 86.856 0.084 ;
    END
  END vm_waddr[126]
  PIN vm_waddr[127]
    DIRECTION INPUT ;
    USE SIGNAL ;
    PORT
      LAYER M5 ;
        RECT  86.928 0 86.952 0.084 ;
    END
  END vm_waddr[127]
  PIN vm_waddr[128]
    DIRECTION INPUT ;
    USE SIGNAL ;
    PORT
      LAYER M5 ;
        RECT  87.024 0 87.048 0.084 ;
    END
  END vm_waddr[128]
  PIN vm_waddr[129]
    DIRECTION INPUT ;
    USE SIGNAL ;
    PORT
      LAYER M5 ;
        RECT  87.12 0 87.144 0.084 ;
    END
  END vm_waddr[129]
  PIN vm_waddr[12]
    DIRECTION INPUT ;
    USE SIGNAL ;
    PORT
      LAYER M5 ;
        RECT  94.32 0 94.344 0.084 ;
    END
  END vm_waddr[12]
  PIN vm_waddr[130]
    DIRECTION INPUT ;
    USE SIGNAL ;
    PORT
      LAYER M5 ;
        RECT  87.216 0 87.24 0.084 ;
    END
  END vm_waddr[130]
  PIN vm_waddr[131]
    DIRECTION INPUT ;
    USE SIGNAL ;
    PORT
      LAYER M5 ;
        RECT  87.312 0 87.336 0.084 ;
    END
  END vm_waddr[131]
  PIN vm_waddr[132]
    DIRECTION INPUT ;
    USE SIGNAL ;
    PORT
      LAYER M5 ;
        RECT  87.408 0 87.432 0.084 ;
    END
  END vm_waddr[132]
  PIN vm_waddr[133]
    DIRECTION INPUT ;
    USE SIGNAL ;
    PORT
      LAYER M5 ;
        RECT  87.504 0 87.528 0.084 ;
    END
  END vm_waddr[133]
  PIN vm_waddr[134]
    DIRECTION INPUT ;
    USE SIGNAL ;
    PORT
      LAYER M5 ;
        RECT  87.6 0 87.624 0.084 ;
    END
  END vm_waddr[134]
  PIN vm_waddr[135]
    DIRECTION INPUT ;
    USE SIGNAL ;
    PORT
      LAYER M5 ;
        RECT  87.696 0 87.72 0.084 ;
    END
  END vm_waddr[135]
  PIN vm_waddr[136]
    DIRECTION INPUT ;
    USE SIGNAL ;
    PORT
      LAYER M5 ;
        RECT  87.792 0 87.816 0.084 ;
    END
  END vm_waddr[136]
  PIN vm_waddr[137]
    DIRECTION INPUT ;
    USE SIGNAL ;
    PORT
      LAYER M5 ;
        RECT  87.888 0 87.912 0.084 ;
    END
  END vm_waddr[137]
  PIN vm_waddr[138]
    DIRECTION INPUT ;
    USE SIGNAL ;
    PORT
      LAYER M5 ;
        RECT  87.984 0 88.008 0.084 ;
    END
  END vm_waddr[138]
  PIN vm_waddr[139]
    DIRECTION INPUT ;
    USE SIGNAL ;
    PORT
      LAYER M5 ;
        RECT  88.08 0 88.104 0.084 ;
    END
  END vm_waddr[139]
  PIN vm_waddr[13]
    DIRECTION INPUT ;
    USE SIGNAL ;
    PORT
      LAYER M5 ;
        RECT  94.416 0 94.44 0.084 ;
    END
  END vm_waddr[13]
  PIN vm_waddr[140]
    DIRECTION INPUT ;
    USE SIGNAL ;
    PORT
      LAYER M5 ;
        RECT  88.176 0 88.2 0.084 ;
    END
  END vm_waddr[140]
  PIN vm_waddr[141]
    DIRECTION INPUT ;
    USE SIGNAL ;
    PORT
      LAYER M5 ;
        RECT  88.272 0 88.296 0.084 ;
    END
  END vm_waddr[141]
  PIN vm_waddr[142]
    DIRECTION INPUT ;
    USE SIGNAL ;
    PORT
      LAYER M5 ;
        RECT  88.368 0 88.392 0.084 ;
    END
  END vm_waddr[142]
  PIN vm_waddr[143]
    DIRECTION INPUT ;
    USE SIGNAL ;
    PORT
      LAYER M5 ;
        RECT  88.464 0 88.488 0.084 ;
    END
  END vm_waddr[143]
  PIN vm_waddr[144]
    DIRECTION INPUT ;
    USE SIGNAL ;
    PORT
      LAYER M5 ;
        RECT  88.56 0 88.584 0.084 ;
    END
  END vm_waddr[144]
  PIN vm_waddr[145]
    DIRECTION INPUT ;
    USE SIGNAL ;
    PORT
      LAYER M5 ;
        RECT  88.656 0 88.68 0.084 ;
    END
  END vm_waddr[145]
  PIN vm_waddr[146]
    DIRECTION INPUT ;
    USE SIGNAL ;
    PORT
      LAYER M5 ;
        RECT  88.752 0 88.776 0.084 ;
    END
  END vm_waddr[146]
  PIN vm_waddr[147]
    DIRECTION INPUT ;
    USE SIGNAL ;
    PORT
      LAYER M5 ;
        RECT  88.848 0 88.872 0.084 ;
    END
  END vm_waddr[147]
  PIN vm_waddr[148]
    DIRECTION INPUT ;
    USE SIGNAL ;
    PORT
      LAYER M5 ;
        RECT  88.944 0 88.968 0.084 ;
    END
  END vm_waddr[148]
  PIN vm_waddr[149]
    DIRECTION INPUT ;
    USE SIGNAL ;
    PORT
      LAYER M5 ;
        RECT  89.04 0 89.064 0.084 ;
    END
  END vm_waddr[149]
  PIN vm_waddr[14]
    DIRECTION INPUT ;
    USE SIGNAL ;
    PORT
      LAYER M5 ;
        RECT  94.512 0 94.536 0.084 ;
    END
  END vm_waddr[14]
  PIN vm_waddr[150]
    DIRECTION INPUT ;
    USE SIGNAL ;
    PORT
      LAYER M5 ;
        RECT  89.136 0 89.16 0.084 ;
    END
  END vm_waddr[150]
  PIN vm_waddr[151]
    DIRECTION INPUT ;
    USE SIGNAL ;
    PORT
      LAYER M5 ;
        RECT  89.232 0 89.256 0.084 ;
    END
  END vm_waddr[151]
  PIN vm_waddr[152]
    DIRECTION INPUT ;
    USE SIGNAL ;
    PORT
      LAYER M5 ;
        RECT  89.328 0 89.352 0.084 ;
    END
  END vm_waddr[152]
  PIN vm_waddr[153]
    DIRECTION INPUT ;
    USE SIGNAL ;
    PORT
      LAYER M5 ;
        RECT  89.424 0 89.448 0.084 ;
    END
  END vm_waddr[153]
  PIN vm_waddr[154]
    DIRECTION INPUT ;
    USE SIGNAL ;
    PORT
      LAYER M5 ;
        RECT  89.52 0 89.544 0.084 ;
    END
  END vm_waddr[154]
  PIN vm_waddr[155]
    DIRECTION INPUT ;
    USE SIGNAL ;
    PORT
      LAYER M5 ;
        RECT  89.616 0 89.64 0.084 ;
    END
  END vm_waddr[155]
  PIN vm_waddr[156]
    DIRECTION INPUT ;
    USE SIGNAL ;
    PORT
      LAYER M5 ;
        RECT  89.712 0 89.736 0.084 ;
    END
  END vm_waddr[156]
  PIN vm_waddr[157]
    DIRECTION INPUT ;
    USE SIGNAL ;
    PORT
      LAYER M5 ;
        RECT  77.52 0 77.544 0.084 ;
    END
  END vm_waddr[157]
  PIN vm_waddr[158]
    DIRECTION INPUT ;
    USE SIGNAL ;
    PORT
      LAYER M5 ;
        RECT  77.616 0 77.64 0.084 ;
    END
  END vm_waddr[158]
  PIN vm_waddr[159]
    DIRECTION INPUT ;
    USE SIGNAL ;
    PORT
      LAYER M5 ;
        RECT  77.712 0 77.736 0.084 ;
    END
  END vm_waddr[159]
  PIN vm_waddr[15]
    DIRECTION INPUT ;
    USE SIGNAL ;
    PORT
      LAYER M5 ;
        RECT  94.608 0 94.632 0.084 ;
    END
  END vm_waddr[15]
  PIN vm_waddr[160]
    DIRECTION INPUT ;
    USE SIGNAL ;
    PORT
      LAYER M5 ;
        RECT  77.808 0 77.832 0.084 ;
    END
  END vm_waddr[160]
  PIN vm_waddr[161]
    DIRECTION INPUT ;
    USE SIGNAL ;
    PORT
      LAYER M5 ;
        RECT  77.904 0 77.928 0.084 ;
    END
  END vm_waddr[161]
  PIN vm_waddr[162]
    DIRECTION INPUT ;
    USE SIGNAL ;
    PORT
      LAYER M5 ;
        RECT  78 0 78.024 0.084 ;
    END
  END vm_waddr[162]
  PIN vm_waddr[163]
    DIRECTION INPUT ;
    USE SIGNAL ;
    PORT
      LAYER M5 ;
        RECT  78.096 0 78.12 0.084 ;
    END
  END vm_waddr[163]
  PIN vm_waddr[164]
    DIRECTION INPUT ;
    USE SIGNAL ;
    PORT
      LAYER M5 ;
        RECT  78.192 0 78.216 0.084 ;
    END
  END vm_waddr[164]
  PIN vm_waddr[165]
    DIRECTION INPUT ;
    USE SIGNAL ;
    PORT
      LAYER M5 ;
        RECT  78.288 0 78.312 0.084 ;
    END
  END vm_waddr[165]
  PIN vm_waddr[166]
    DIRECTION INPUT ;
    USE SIGNAL ;
    PORT
      LAYER M5 ;
        RECT  78.384 0 78.408 0.084 ;
    END
  END vm_waddr[166]
  PIN vm_waddr[167]
    DIRECTION INPUT ;
    USE SIGNAL ;
    PORT
      LAYER M5 ;
        RECT  78.48 0 78.504 0.084 ;
    END
  END vm_waddr[167]
  PIN vm_waddr[168]
    DIRECTION INPUT ;
    USE SIGNAL ;
    PORT
      LAYER M5 ;
        RECT  78.576 0 78.6 0.084 ;
    END
  END vm_waddr[168]
  PIN vm_waddr[169]
    DIRECTION INPUT ;
    USE SIGNAL ;
    PORT
      LAYER M5 ;
        RECT  78.672 0 78.696 0.084 ;
    END
  END vm_waddr[169]
  PIN vm_waddr[16]
    DIRECTION INPUT ;
    USE SIGNAL ;
    PORT
      LAYER M5 ;
        RECT  94.704 0 94.728 0.084 ;
    END
  END vm_waddr[16]
  PIN vm_waddr[170]
    DIRECTION INPUT ;
    USE SIGNAL ;
    PORT
      LAYER M5 ;
        RECT  78.768 0 78.792 0.084 ;
    END
  END vm_waddr[170]
  PIN vm_waddr[171]
    DIRECTION INPUT ;
    USE SIGNAL ;
    PORT
      LAYER M5 ;
        RECT  78.864 0 78.888 0.084 ;
    END
  END vm_waddr[171]
  PIN vm_waddr[172]
    DIRECTION INPUT ;
    USE SIGNAL ;
    PORT
      LAYER M5 ;
        RECT  78.96 0 78.984 0.084 ;
    END
  END vm_waddr[172]
  PIN vm_waddr[173]
    DIRECTION INPUT ;
    USE SIGNAL ;
    PORT
      LAYER M5 ;
        RECT  79.056 0 79.08 0.084 ;
    END
  END vm_waddr[173]
  PIN vm_waddr[174]
    DIRECTION INPUT ;
    USE SIGNAL ;
    PORT
      LAYER M5 ;
        RECT  79.152 0 79.176 0.084 ;
    END
  END vm_waddr[174]
  PIN vm_waddr[175]
    DIRECTION INPUT ;
    USE SIGNAL ;
    PORT
      LAYER M5 ;
        RECT  79.248 0 79.272 0.084 ;
    END
  END vm_waddr[175]
  PIN vm_waddr[176]
    DIRECTION INPUT ;
    USE SIGNAL ;
    PORT
      LAYER M5 ;
        RECT  79.344 0 79.368 0.084 ;
    END
  END vm_waddr[176]
  PIN vm_waddr[177]
    DIRECTION INPUT ;
    USE SIGNAL ;
    PORT
      LAYER M5 ;
        RECT  79.44 0 79.464 0.084 ;
    END
  END vm_waddr[177]
  PIN vm_waddr[178]
    DIRECTION INPUT ;
    USE SIGNAL ;
    PORT
      LAYER M5 ;
        RECT  79.536 0 79.56 0.084 ;
    END
  END vm_waddr[178]
  PIN vm_waddr[179]
    DIRECTION INPUT ;
    USE SIGNAL ;
    PORT
      LAYER M5 ;
        RECT  79.632 0 79.656 0.084 ;
    END
  END vm_waddr[179]
  PIN vm_waddr[17]
    DIRECTION INPUT ;
    USE SIGNAL ;
    PORT
      LAYER M5 ;
        RECT  94.8 0 94.824 0.084 ;
    END
  END vm_waddr[17]
  PIN vm_waddr[180]
    DIRECTION INPUT ;
    USE SIGNAL ;
    PORT
      LAYER M5 ;
        RECT  79.728 0 79.752 0.084 ;
    END
  END vm_waddr[180]
  PIN vm_waddr[181]
    DIRECTION INPUT ;
    USE SIGNAL ;
    PORT
      LAYER M5 ;
        RECT  79.824 0 79.848 0.084 ;
    END
  END vm_waddr[181]
  PIN vm_waddr[182]
    DIRECTION INPUT ;
    USE SIGNAL ;
    PORT
      LAYER M5 ;
        RECT  79.92 0 79.944 0.084 ;
    END
  END vm_waddr[182]
  PIN vm_waddr[183]
    DIRECTION INPUT ;
    USE SIGNAL ;
    PORT
      LAYER M5 ;
        RECT  80.016 0 80.04 0.084 ;
    END
  END vm_waddr[183]
  PIN vm_waddr[184]
    DIRECTION INPUT ;
    USE SIGNAL ;
    PORT
      LAYER M5 ;
        RECT  80.112 0 80.136 0.084 ;
    END
  END vm_waddr[184]
  PIN vm_waddr[185]
    DIRECTION INPUT ;
    USE SIGNAL ;
    PORT
      LAYER M5 ;
        RECT  80.208 0 80.232 0.084 ;
    END
  END vm_waddr[185]
  PIN vm_waddr[186]
    DIRECTION INPUT ;
    USE SIGNAL ;
    PORT
      LAYER M5 ;
        RECT  80.304 0 80.328 0.084 ;
    END
  END vm_waddr[186]
  PIN vm_waddr[187]
    DIRECTION INPUT ;
    USE SIGNAL ;
    PORT
      LAYER M5 ;
        RECT  80.4 0 80.424 0.084 ;
    END
  END vm_waddr[187]
  PIN vm_waddr[188]
    DIRECTION INPUT ;
    USE SIGNAL ;
    PORT
      LAYER M5 ;
        RECT  80.496 0 80.52 0.084 ;
    END
  END vm_waddr[188]
  PIN vm_waddr[189]
    DIRECTION INPUT ;
    USE SIGNAL ;
    PORT
      LAYER M5 ;
        RECT  115.92 0 115.944 0.084 ;
    END
  END vm_waddr[189]
  PIN vm_waddr[18]
    DIRECTION INPUT ;
    USE SIGNAL ;
    PORT
      LAYER M5 ;
        RECT  94.896 0 94.92 0.084 ;
    END
  END vm_waddr[18]
  PIN vm_waddr[190]
    DIRECTION INPUT ;
    USE SIGNAL ;
    PORT
      LAYER M5 ;
        RECT  116.016 0 116.04 0.084 ;
    END
  END vm_waddr[190]
  PIN vm_waddr[191]
    DIRECTION INPUT ;
    USE SIGNAL ;
    PORT
      LAYER M5 ;
        RECT  116.112 0 116.136 0.084 ;
    END
  END vm_waddr[191]
  PIN vm_waddr[19]
    DIRECTION INPUT ;
    USE SIGNAL ;
    PORT
      LAYER M5 ;
        RECT  94.992 0 95.016 0.084 ;
    END
  END vm_waddr[19]
  PIN vm_waddr[1]
    DIRECTION INPUT ;
    USE SIGNAL ;
    PORT
      LAYER M5 ;
        RECT  93.264 0 93.288 0.084 ;
    END
  END vm_waddr[1]
  PIN vm_waddr[20]
    DIRECTION INPUT ;
    USE SIGNAL ;
    PORT
      LAYER M5 ;
        RECT  95.088 0 95.112 0.084 ;
    END
  END vm_waddr[20]
  PIN vm_waddr[21]
    DIRECTION INPUT ;
    USE SIGNAL ;
    PORT
      LAYER M5 ;
        RECT  95.184 0 95.208 0.084 ;
    END
  END vm_waddr[21]
  PIN vm_waddr[22]
    DIRECTION INPUT ;
    USE SIGNAL ;
    PORT
      LAYER M5 ;
        RECT  95.28 0 95.304 0.084 ;
    END
  END vm_waddr[22]
  PIN vm_waddr[23]
    DIRECTION INPUT ;
    USE SIGNAL ;
    PORT
      LAYER M5 ;
        RECT  95.376 0 95.4 0.084 ;
    END
  END vm_waddr[23]
  PIN vm_waddr[24]
    DIRECTION INPUT ;
    USE SIGNAL ;
    PORT
      LAYER M5 ;
        RECT  95.472 0 95.496 0.084 ;
    END
  END vm_waddr[24]
  PIN vm_waddr[25]
    DIRECTION INPUT ;
    USE SIGNAL ;
    PORT
      LAYER M5 ;
        RECT  95.568 0 95.592 0.084 ;
    END
  END vm_waddr[25]
  PIN vm_waddr[26]
    DIRECTION INPUT ;
    USE SIGNAL ;
    PORT
      LAYER M5 ;
        RECT  95.664 0 95.688 0.084 ;
    END
  END vm_waddr[26]
  PIN vm_waddr[27]
    DIRECTION INPUT ;
    USE SIGNAL ;
    PORT
      LAYER M5 ;
        RECT  95.76 0 95.784 0.084 ;
    END
  END vm_waddr[27]
  PIN vm_waddr[28]
    DIRECTION INPUT ;
    USE SIGNAL ;
    PORT
      LAYER M5 ;
        RECT  95.856 0 95.88 0.084 ;
    END
  END vm_waddr[28]
  PIN vm_waddr[29]
    DIRECTION INPUT ;
    USE SIGNAL ;
    PORT
      LAYER M5 ;
        RECT  83.664 0 83.688 0.084 ;
    END
  END vm_waddr[29]
  PIN vm_waddr[2]
    DIRECTION INPUT ;
    USE SIGNAL ;
    PORT
      LAYER M5 ;
        RECT  93.36 0 93.384 0.084 ;
    END
  END vm_waddr[2]
  PIN vm_waddr[30]
    DIRECTION INPUT ;
    USE SIGNAL ;
    PORT
      LAYER M5 ;
        RECT  83.76 0 83.784 0.084 ;
    END
  END vm_waddr[30]
  PIN vm_waddr[31]
    DIRECTION INPUT ;
    USE SIGNAL ;
    PORT
      LAYER M5 ;
        RECT  83.856 0 83.88 0.084 ;
    END
  END vm_waddr[31]
  PIN vm_waddr[32]
    DIRECTION INPUT ;
    USE SIGNAL ;
    PORT
      LAYER M5 ;
        RECT  83.952 0 83.976 0.084 ;
    END
  END vm_waddr[32]
  PIN vm_waddr[33]
    DIRECTION INPUT ;
    USE SIGNAL ;
    PORT
      LAYER M5 ;
        RECT  84.048 0 84.072 0.084 ;
    END
  END vm_waddr[33]
  PIN vm_waddr[34]
    DIRECTION INPUT ;
    USE SIGNAL ;
    PORT
      LAYER M5 ;
        RECT  84.144 0 84.168 0.084 ;
    END
  END vm_waddr[34]
  PIN vm_waddr[35]
    DIRECTION INPUT ;
    USE SIGNAL ;
    PORT
      LAYER M5 ;
        RECT  84.24 0 84.264 0.084 ;
    END
  END vm_waddr[35]
  PIN vm_waddr[36]
    DIRECTION INPUT ;
    USE SIGNAL ;
    PORT
      LAYER M5 ;
        RECT  84.336 0 84.36 0.084 ;
    END
  END vm_waddr[36]
  PIN vm_waddr[37]
    DIRECTION INPUT ;
    USE SIGNAL ;
    PORT
      LAYER M5 ;
        RECT  84.432 0 84.456 0.084 ;
    END
  END vm_waddr[37]
  PIN vm_waddr[38]
    DIRECTION INPUT ;
    USE SIGNAL ;
    PORT
      LAYER M5 ;
        RECT  84.528 0 84.552 0.084 ;
    END
  END vm_waddr[38]
  PIN vm_waddr[39]
    DIRECTION INPUT ;
    USE SIGNAL ;
    PORT
      LAYER M5 ;
        RECT  84.624 0 84.648 0.084 ;
    END
  END vm_waddr[39]
  PIN vm_waddr[3]
    DIRECTION INPUT ;
    USE SIGNAL ;
    PORT
      LAYER M5 ;
        RECT  93.456 0 93.48 0.084 ;
    END
  END vm_waddr[3]
  PIN vm_waddr[40]
    DIRECTION INPUT ;
    USE SIGNAL ;
    PORT
      LAYER M5 ;
        RECT  84.72 0 84.744 0.084 ;
    END
  END vm_waddr[40]
  PIN vm_waddr[41]
    DIRECTION INPUT ;
    USE SIGNAL ;
    PORT
      LAYER M5 ;
        RECT  84.816 0 84.84 0.084 ;
    END
  END vm_waddr[41]
  PIN vm_waddr[42]
    DIRECTION INPUT ;
    USE SIGNAL ;
    PORT
      LAYER M5 ;
        RECT  84.912 0 84.936 0.084 ;
    END
  END vm_waddr[42]
  PIN vm_waddr[43]
    DIRECTION INPUT ;
    USE SIGNAL ;
    PORT
      LAYER M5 ;
        RECT  85.008 0 85.032 0.084 ;
    END
  END vm_waddr[43]
  PIN vm_waddr[44]
    DIRECTION INPUT ;
    USE SIGNAL ;
    PORT
      LAYER M5 ;
        RECT  85.104 0 85.128 0.084 ;
    END
  END vm_waddr[44]
  PIN vm_waddr[45]
    DIRECTION INPUT ;
    USE SIGNAL ;
    PORT
      LAYER M5 ;
        RECT  85.2 0 85.224 0.084 ;
    END
  END vm_waddr[45]
  PIN vm_waddr[46]
    DIRECTION INPUT ;
    USE SIGNAL ;
    PORT
      LAYER M5 ;
        RECT  85.296 0 85.32 0.084 ;
    END
  END vm_waddr[46]
  PIN vm_waddr[47]
    DIRECTION INPUT ;
    USE SIGNAL ;
    PORT
      LAYER M5 ;
        RECT  85.392 0 85.416 0.084 ;
    END
  END vm_waddr[47]
  PIN vm_waddr[48]
    DIRECTION INPUT ;
    USE SIGNAL ;
    PORT
      LAYER M5 ;
        RECT  85.488 0 85.512 0.084 ;
    END
  END vm_waddr[48]
  PIN vm_waddr[49]
    DIRECTION INPUT ;
    USE SIGNAL ;
    PORT
      LAYER M5 ;
        RECT  85.584 0 85.608 0.084 ;
    END
  END vm_waddr[49]
  PIN vm_waddr[4]
    DIRECTION INPUT ;
    USE SIGNAL ;
    PORT
      LAYER M5 ;
        RECT  93.552 0 93.576 0.084 ;
    END
  END vm_waddr[4]
  PIN vm_waddr[50]
    DIRECTION INPUT ;
    USE SIGNAL ;
    PORT
      LAYER M5 ;
        RECT  85.68 0 85.704 0.084 ;
    END
  END vm_waddr[50]
  PIN vm_waddr[51]
    DIRECTION INPUT ;
    USE SIGNAL ;
    PORT
      LAYER M5 ;
        RECT  85.776 0 85.8 0.084 ;
    END
  END vm_waddr[51]
  PIN vm_waddr[52]
    DIRECTION INPUT ;
    USE SIGNAL ;
    PORT
      LAYER M5 ;
        RECT  85.872 0 85.896 0.084 ;
    END
  END vm_waddr[52]
  PIN vm_waddr[53]
    DIRECTION INPUT ;
    USE SIGNAL ;
    PORT
      LAYER M5 ;
        RECT  85.968 0 85.992 0.084 ;
    END
  END vm_waddr[53]
  PIN vm_waddr[54]
    DIRECTION INPUT ;
    USE SIGNAL ;
    PORT
      LAYER M5 ;
        RECT  86.064 0 86.088 0.084 ;
    END
  END vm_waddr[54]
  PIN vm_waddr[55]
    DIRECTION INPUT ;
    USE SIGNAL ;
    PORT
      LAYER M5 ;
        RECT  86.16 0 86.184 0.084 ;
    END
  END vm_waddr[55]
  PIN vm_waddr[56]
    DIRECTION INPUT ;
    USE SIGNAL ;
    PORT
      LAYER M5 ;
        RECT  86.256 0 86.28 0.084 ;
    END
  END vm_waddr[56]
  PIN vm_waddr[57]
    DIRECTION INPUT ;
    USE SIGNAL ;
    PORT
      LAYER M5 ;
        RECT  86.352 0 86.376 0.084 ;
    END
  END vm_waddr[57]
  PIN vm_waddr[58]
    DIRECTION INPUT ;
    USE SIGNAL ;
    PORT
      LAYER M5 ;
        RECT  86.448 0 86.472 0.084 ;
    END
  END vm_waddr[58]
  PIN vm_waddr[59]
    DIRECTION INPUT ;
    USE SIGNAL ;
    PORT
      LAYER M5 ;
        RECT  86.544 0 86.568 0.084 ;
    END
  END vm_waddr[59]
  PIN vm_waddr[5]
    DIRECTION INPUT ;
    USE SIGNAL ;
    PORT
      LAYER M5 ;
        RECT  93.648 0 93.672 0.084 ;
    END
  END vm_waddr[5]
  PIN vm_waddr[60]
    DIRECTION INPUT ;
    USE SIGNAL ;
    PORT
      LAYER M5 ;
        RECT  86.64 0 86.664 0.084 ;
    END
  END vm_waddr[60]
  PIN vm_waddr[61]
    DIRECTION INPUT ;
    USE SIGNAL ;
    PORT
      LAYER M5 ;
        RECT  80.592 0 80.616 0.084 ;
    END
  END vm_waddr[61]
  PIN vm_waddr[62]
    DIRECTION INPUT ;
    USE SIGNAL ;
    PORT
      LAYER M5 ;
        RECT  80.688 0 80.712 0.084 ;
    END
  END vm_waddr[62]
  PIN vm_waddr[63]
    DIRECTION INPUT ;
    USE SIGNAL ;
    PORT
      LAYER M5 ;
        RECT  80.784 0 80.808 0.084 ;
    END
  END vm_waddr[63]
  PIN vm_waddr[64]
    DIRECTION INPUT ;
    USE SIGNAL ;
    PORT
      LAYER M5 ;
        RECT  80.88 0 80.904 0.084 ;
    END
  END vm_waddr[64]
  PIN vm_waddr[65]
    DIRECTION INPUT ;
    USE SIGNAL ;
    PORT
      LAYER M5 ;
        RECT  80.976 0 81 0.084 ;
    END
  END vm_waddr[65]
  PIN vm_waddr[66]
    DIRECTION INPUT ;
    USE SIGNAL ;
    PORT
      LAYER M5 ;
        RECT  81.072 0 81.096 0.084 ;
    END
  END vm_waddr[66]
  PIN vm_waddr[67]
    DIRECTION INPUT ;
    USE SIGNAL ;
    PORT
      LAYER M5 ;
        RECT  81.168 0 81.192 0.084 ;
    END
  END vm_waddr[67]
  PIN vm_waddr[68]
    DIRECTION INPUT ;
    USE SIGNAL ;
    PORT
      LAYER M5 ;
        RECT  81.264 0 81.288 0.084 ;
    END
  END vm_waddr[68]
  PIN vm_waddr[69]
    DIRECTION INPUT ;
    USE SIGNAL ;
    PORT
      LAYER M5 ;
        RECT  81.36 0 81.384 0.084 ;
    END
  END vm_waddr[69]
  PIN vm_waddr[6]
    DIRECTION INPUT ;
    USE SIGNAL ;
    PORT
      LAYER M5 ;
        RECT  93.744 0 93.768 0.084 ;
    END
  END vm_waddr[6]
  PIN vm_waddr[70]
    DIRECTION INPUT ;
    USE SIGNAL ;
    PORT
      LAYER M5 ;
        RECT  81.456 0 81.48 0.084 ;
    END
  END vm_waddr[70]
  PIN vm_waddr[71]
    DIRECTION INPUT ;
    USE SIGNAL ;
    PORT
      LAYER M5 ;
        RECT  81.552 0 81.576 0.084 ;
    END
  END vm_waddr[71]
  PIN vm_waddr[72]
    DIRECTION INPUT ;
    USE SIGNAL ;
    PORT
      LAYER M5 ;
        RECT  81.648 0 81.672 0.084 ;
    END
  END vm_waddr[72]
  PIN vm_waddr[73]
    DIRECTION INPUT ;
    USE SIGNAL ;
    PORT
      LAYER M5 ;
        RECT  81.744 0 81.768 0.084 ;
    END
  END vm_waddr[73]
  PIN vm_waddr[74]
    DIRECTION INPUT ;
    USE SIGNAL ;
    PORT
      LAYER M5 ;
        RECT  81.84 0 81.864 0.084 ;
    END
  END vm_waddr[74]
  PIN vm_waddr[75]
    DIRECTION INPUT ;
    USE SIGNAL ;
    PORT
      LAYER M5 ;
        RECT  81.936 0 81.96 0.084 ;
    END
  END vm_waddr[75]
  PIN vm_waddr[76]
    DIRECTION INPUT ;
    USE SIGNAL ;
    PORT
      LAYER M5 ;
        RECT  82.032 0 82.056 0.084 ;
    END
  END vm_waddr[76]
  PIN vm_waddr[77]
    DIRECTION INPUT ;
    USE SIGNAL ;
    PORT
      LAYER M5 ;
        RECT  82.128 0 82.152 0.084 ;
    END
  END vm_waddr[77]
  PIN vm_waddr[78]
    DIRECTION INPUT ;
    USE SIGNAL ;
    PORT
      LAYER M5 ;
        RECT  82.224 0 82.248 0.084 ;
    END
  END vm_waddr[78]
  PIN vm_waddr[79]
    DIRECTION INPUT ;
    USE SIGNAL ;
    PORT
      LAYER M5 ;
        RECT  82.32 0 82.344 0.084 ;
    END
  END vm_waddr[79]
  PIN vm_waddr[7]
    DIRECTION INPUT ;
    USE SIGNAL ;
    PORT
      LAYER M5 ;
        RECT  93.84 0 93.864 0.084 ;
    END
  END vm_waddr[7]
  PIN vm_waddr[80]
    DIRECTION INPUT ;
    USE SIGNAL ;
    PORT
      LAYER M5 ;
        RECT  82.416 0 82.44 0.084 ;
    END
  END vm_waddr[80]
  PIN vm_waddr[81]
    DIRECTION INPUT ;
    USE SIGNAL ;
    PORT
      LAYER M5 ;
        RECT  82.512 0 82.536 0.084 ;
    END
  END vm_waddr[81]
  PIN vm_waddr[82]
    DIRECTION INPUT ;
    USE SIGNAL ;
    PORT
      LAYER M5 ;
        RECT  82.608 0 82.632 0.084 ;
    END
  END vm_waddr[82]
  PIN vm_waddr[83]
    DIRECTION INPUT ;
    USE SIGNAL ;
    PORT
      LAYER M5 ;
        RECT  82.704 0 82.728 0.084 ;
    END
  END vm_waddr[83]
  PIN vm_waddr[84]
    DIRECTION INPUT ;
    USE SIGNAL ;
    PORT
      LAYER M5 ;
        RECT  82.8 0 82.824 0.084 ;
    END
  END vm_waddr[84]
  PIN vm_waddr[85]
    DIRECTION INPUT ;
    USE SIGNAL ;
    PORT
      LAYER M5 ;
        RECT  82.896 0 82.92 0.084 ;
    END
  END vm_waddr[85]
  PIN vm_waddr[86]
    DIRECTION INPUT ;
    USE SIGNAL ;
    PORT
      LAYER M5 ;
        RECT  82.992 0 83.016 0.084 ;
    END
  END vm_waddr[86]
  PIN vm_waddr[87]
    DIRECTION INPUT ;
    USE SIGNAL ;
    PORT
      LAYER M5 ;
        RECT  83.088 0 83.112 0.084 ;
    END
  END vm_waddr[87]
  PIN vm_waddr[88]
    DIRECTION INPUT ;
    USE SIGNAL ;
    PORT
      LAYER M5 ;
        RECT  83.184 0 83.208 0.084 ;
    END
  END vm_waddr[88]
  PIN vm_waddr[89]
    DIRECTION INPUT ;
    USE SIGNAL ;
    PORT
      LAYER M5 ;
        RECT  83.28 0 83.304 0.084 ;
    END
  END vm_waddr[89]
  PIN vm_waddr[8]
    DIRECTION INPUT ;
    USE SIGNAL ;
    PORT
      LAYER M5 ;
        RECT  93.936 0 93.96 0.084 ;
    END
  END vm_waddr[8]
  PIN vm_waddr[90]
    DIRECTION INPUT ;
    USE SIGNAL ;
    PORT
      LAYER M5 ;
        RECT  83.376 0 83.4 0.084 ;
    END
  END vm_waddr[90]
  PIN vm_waddr[91]
    DIRECTION INPUT ;
    USE SIGNAL ;
    PORT
      LAYER M5 ;
        RECT  83.472 0 83.496 0.084 ;
    END
  END vm_waddr[91]
  PIN vm_waddr[92]
    DIRECTION INPUT ;
    USE SIGNAL ;
    PORT
      LAYER M5 ;
        RECT  83.568 0 83.592 0.084 ;
    END
  END vm_waddr[92]
  PIN vm_waddr[93]
    DIRECTION INPUT ;
    USE SIGNAL ;
    PORT
      LAYER M5 ;
        RECT  89.808 0 89.832 0.084 ;
    END
  END vm_waddr[93]
  PIN vm_waddr[94]
    DIRECTION INPUT ;
    USE SIGNAL ;
    PORT
      LAYER M5 ;
        RECT  89.904 0 89.928 0.084 ;
    END
  END vm_waddr[94]
  PIN vm_waddr[95]
    DIRECTION INPUT ;
    USE SIGNAL ;
    PORT
      LAYER M5 ;
        RECT  90 0 90.024 0.084 ;
    END
  END vm_waddr[95]
  PIN vm_waddr[96]
    DIRECTION INPUT ;
    USE SIGNAL ;
    PORT
      LAYER M5 ;
        RECT  90.096 0 90.12 0.084 ;
    END
  END vm_waddr[96]
  PIN vm_waddr[97]
    DIRECTION INPUT ;
    USE SIGNAL ;
    PORT
      LAYER M5 ;
        RECT  90.192 0 90.216 0.084 ;
    END
  END vm_waddr[97]
  PIN vm_waddr[98]
    DIRECTION INPUT ;
    USE SIGNAL ;
    PORT
      LAYER M5 ;
        RECT  90.288 0 90.312 0.084 ;
    END
  END vm_waddr[98]
  PIN vm_waddr[99]
    DIRECTION INPUT ;
    USE SIGNAL ;
    PORT
      LAYER M5 ;
        RECT  90.384 0 90.408 0.084 ;
    END
  END vm_waddr[99]
  PIN vm_waddr[9]
    DIRECTION INPUT ;
    USE SIGNAL ;
    PORT
      LAYER M5 ;
        RECT  94.032 0 94.056 0.084 ;
    END
  END vm_waddr[9]
  PIN vm_wdata[0]
    DIRECTION INPUT ;
    USE SIGNAL ;
    PORT
      LAYER M5 ;
        RECT  116.208 0 116.232 0.084 ;
    END
  END vm_wdata[0]
  PIN vm_wdata[100]
    DIRECTION INPUT ;
    USE SIGNAL ;
    PORT
      LAYER M5 ;
        RECT  125.808 0 125.832 0.084 ;
    END
  END vm_wdata[100]
  PIN vm_wdata[101]
    DIRECTION INPUT ;
    USE SIGNAL ;
    PORT
      LAYER M5 ;
        RECT  125.904 0 125.928 0.084 ;
    END
  END vm_wdata[101]
  PIN vm_wdata[102]
    DIRECTION INPUT ;
    USE SIGNAL ;
    PORT
      LAYER M5 ;
        RECT  126 0 126.024 0.084 ;
    END
  END vm_wdata[102]
  PIN vm_wdata[103]
    DIRECTION INPUT ;
    USE SIGNAL ;
    PORT
      LAYER M5 ;
        RECT  126.096 0 126.12 0.084 ;
    END
  END vm_wdata[103]
  PIN vm_wdata[104]
    DIRECTION INPUT ;
    USE SIGNAL ;
    PORT
      LAYER M5 ;
        RECT  126.192 0 126.216 0.084 ;
    END
  END vm_wdata[104]
  PIN vm_wdata[105]
    DIRECTION INPUT ;
    USE SIGNAL ;
    PORT
      LAYER M5 ;
        RECT  126.288 0 126.312 0.084 ;
    END
  END vm_wdata[105]
  PIN vm_wdata[106]
    DIRECTION INPUT ;
    USE SIGNAL ;
    PORT
      LAYER M5 ;
        RECT  126.384 0 126.408 0.084 ;
    END
  END vm_wdata[106]
  PIN vm_wdata[107]
    DIRECTION INPUT ;
    USE SIGNAL ;
    PORT
      LAYER M5 ;
        RECT  126.48 0 126.504 0.084 ;
    END
  END vm_wdata[107]
  PIN vm_wdata[108]
    DIRECTION INPUT ;
    USE SIGNAL ;
    PORT
      LAYER M5 ;
        RECT  126.576 0 126.6 0.084 ;
    END
  END vm_wdata[108]
  PIN vm_wdata[109]
    DIRECTION INPUT ;
    USE SIGNAL ;
    PORT
      LAYER M5 ;
        RECT  126.672 0 126.696 0.084 ;
    END
  END vm_wdata[109]
  PIN vm_wdata[10]
    DIRECTION INPUT ;
    USE SIGNAL ;
    PORT
      LAYER M5 ;
        RECT  117.168 0 117.192 0.084 ;
    END
  END vm_wdata[10]
  PIN vm_wdata[110]
    DIRECTION INPUT ;
    USE SIGNAL ;
    PORT
      LAYER M5 ;
        RECT  126.768 0 126.792 0.084 ;
    END
  END vm_wdata[110]
  PIN vm_wdata[111]
    DIRECTION INPUT ;
    USE SIGNAL ;
    PORT
      LAYER M5 ;
        RECT  126.864 0 126.888 0.084 ;
    END
  END vm_wdata[111]
  PIN vm_wdata[112]
    DIRECTION INPUT ;
    USE SIGNAL ;
    PORT
      LAYER M5 ;
        RECT  126.96 0 126.984 0.084 ;
    END
  END vm_wdata[112]
  PIN vm_wdata[113]
    DIRECTION INPUT ;
    USE SIGNAL ;
    PORT
      LAYER M5 ;
        RECT  127.056 0 127.08 0.084 ;
    END
  END vm_wdata[113]
  PIN vm_wdata[114]
    DIRECTION INPUT ;
    USE SIGNAL ;
    PORT
      LAYER M5 ;
        RECT  127.152 0 127.176 0.084 ;
    END
  END vm_wdata[114]
  PIN vm_wdata[115]
    DIRECTION INPUT ;
    USE SIGNAL ;
    PORT
      LAYER M5 ;
        RECT  127.248 0 127.272 0.084 ;
    END
  END vm_wdata[115]
  PIN vm_wdata[116]
    DIRECTION INPUT ;
    USE SIGNAL ;
    PORT
      LAYER M5 ;
        RECT  127.344 0 127.368 0.084 ;
    END
  END vm_wdata[116]
  PIN vm_wdata[117]
    DIRECTION INPUT ;
    USE SIGNAL ;
    PORT
      LAYER M5 ;
        RECT  127.44 0 127.464 0.084 ;
    END
  END vm_wdata[117]
  PIN vm_wdata[118]
    DIRECTION INPUT ;
    USE SIGNAL ;
    PORT
      LAYER M5 ;
        RECT  127.536 0 127.56 0.084 ;
    END
  END vm_wdata[118]
  PIN vm_wdata[119]
    DIRECTION INPUT ;
    USE SIGNAL ;
    PORT
      LAYER M5 ;
        RECT  127.632 0 127.656 0.084 ;
    END
  END vm_wdata[119]
  PIN vm_wdata[11]
    DIRECTION INPUT ;
    USE SIGNAL ;
    PORT
      LAYER M5 ;
        RECT  117.264 0 117.288 0.084 ;
    END
  END vm_wdata[11]
  PIN vm_wdata[120]
    DIRECTION INPUT ;
    USE SIGNAL ;
    PORT
      LAYER M5 ;
        RECT  127.728 0 127.752 0.084 ;
    END
  END vm_wdata[120]
  PIN vm_wdata[121]
    DIRECTION INPUT ;
    USE SIGNAL ;
    PORT
      LAYER M5 ;
        RECT  127.824 0 127.848 0.084 ;
    END
  END vm_wdata[121]
  PIN vm_wdata[122]
    DIRECTION INPUT ;
    USE SIGNAL ;
    PORT
      LAYER M5 ;
        RECT  127.92 0 127.944 0.084 ;
    END
  END vm_wdata[122]
  PIN vm_wdata[123]
    DIRECTION INPUT ;
    USE SIGNAL ;
    PORT
      LAYER M5 ;
        RECT  128.016 0 128.04 0.084 ;
    END
  END vm_wdata[123]
  PIN vm_wdata[124]
    DIRECTION INPUT ;
    USE SIGNAL ;
    PORT
      LAYER M5 ;
        RECT  128.112 0 128.136 0.084 ;
    END
  END vm_wdata[124]
  PIN vm_wdata[125]
    DIRECTION INPUT ;
    USE SIGNAL ;
    PORT
      LAYER M5 ;
        RECT  128.208 0 128.232 0.084 ;
    END
  END vm_wdata[125]
  PIN vm_wdata[126]
    DIRECTION INPUT ;
    USE SIGNAL ;
    PORT
      LAYER M5 ;
        RECT  128.304 0 128.328 0.084 ;
    END
  END vm_wdata[126]
  PIN vm_wdata[127]
    DIRECTION INPUT ;
    USE SIGNAL ;
    PORT
      LAYER M5 ;
        RECT  128.4 0 128.424 0.084 ;
    END
  END vm_wdata[127]
  PIN vm_wdata[128]
    DIRECTION INPUT ;
    USE SIGNAL ;
    PORT
      LAYER M5 ;
        RECT  128.496 0 128.52 0.084 ;
    END
  END vm_wdata[128]
  PIN vm_wdata[129]
    DIRECTION INPUT ;
    USE SIGNAL ;
    PORT
      LAYER M5 ;
        RECT  128.592 0 128.616 0.084 ;
    END
  END vm_wdata[129]
  PIN vm_wdata[12]
    DIRECTION INPUT ;
    USE SIGNAL ;
    PORT
      LAYER M5 ;
        RECT  117.36 0 117.384 0.084 ;
    END
  END vm_wdata[12]
  PIN vm_wdata[130]
    DIRECTION INPUT ;
    USE SIGNAL ;
    PORT
      LAYER M5 ;
        RECT  128.688 0 128.712 0.084 ;
    END
  END vm_wdata[130]
  PIN vm_wdata[131]
    DIRECTION INPUT ;
    USE SIGNAL ;
    PORT
      LAYER M5 ;
        RECT  128.784 0 128.808 0.084 ;
    END
  END vm_wdata[131]
  PIN vm_wdata[132]
    DIRECTION INPUT ;
    USE SIGNAL ;
    PORT
      LAYER M5 ;
        RECT  128.88 0 128.904 0.084 ;
    END
  END vm_wdata[132]
  PIN vm_wdata[133]
    DIRECTION INPUT ;
    USE SIGNAL ;
    PORT
      LAYER M5 ;
        RECT  128.976 0 129 0.084 ;
    END
  END vm_wdata[133]
  PIN vm_wdata[134]
    DIRECTION INPUT ;
    USE SIGNAL ;
    PORT
      LAYER M5 ;
        RECT  129.072 0 129.096 0.084 ;
    END
  END vm_wdata[134]
  PIN vm_wdata[135]
    DIRECTION INPUT ;
    USE SIGNAL ;
    PORT
      LAYER M5 ;
        RECT  129.168 0 129.192 0.084 ;
    END
  END vm_wdata[135]
  PIN vm_wdata[136]
    DIRECTION INPUT ;
    USE SIGNAL ;
    PORT
      LAYER M5 ;
        RECT  129.264 0 129.288 0.084 ;
    END
  END vm_wdata[136]
  PIN vm_wdata[137]
    DIRECTION INPUT ;
    USE SIGNAL ;
    PORT
      LAYER M5 ;
        RECT  129.36 0 129.384 0.084 ;
    END
  END vm_wdata[137]
  PIN vm_wdata[138]
    DIRECTION INPUT ;
    USE SIGNAL ;
    PORT
      LAYER M5 ;
        RECT  129.456 0 129.48 0.084 ;
    END
  END vm_wdata[138]
  PIN vm_wdata[139]
    DIRECTION INPUT ;
    USE SIGNAL ;
    PORT
      LAYER M5 ;
        RECT  129.552 0 129.576 0.084 ;
    END
  END vm_wdata[139]
  PIN vm_wdata[13]
    DIRECTION INPUT ;
    USE SIGNAL ;
    PORT
      LAYER M5 ;
        RECT  117.456 0 117.48 0.084 ;
    END
  END vm_wdata[13]
  PIN vm_wdata[140]
    DIRECTION INPUT ;
    USE SIGNAL ;
    PORT
      LAYER M5 ;
        RECT  129.648 0 129.672 0.084 ;
    END
  END vm_wdata[140]
  PIN vm_wdata[141]
    DIRECTION INPUT ;
    USE SIGNAL ;
    PORT
      LAYER M5 ;
        RECT  129.744 0 129.768 0.084 ;
    END
  END vm_wdata[141]
  PIN vm_wdata[142]
    DIRECTION INPUT ;
    USE SIGNAL ;
    PORT
      LAYER M5 ;
        RECT  129.84 0 129.864 0.084 ;
    END
  END vm_wdata[142]
  PIN vm_wdata[143]
    DIRECTION INPUT ;
    USE SIGNAL ;
    PORT
      LAYER M5 ;
        RECT  129.936 0 129.96 0.084 ;
    END
  END vm_wdata[143]
  PIN vm_wdata[144]
    DIRECTION INPUT ;
    USE SIGNAL ;
    PORT
      LAYER M5 ;
        RECT  130.032 0 130.056 0.084 ;
    END
  END vm_wdata[144]
  PIN vm_wdata[145]
    DIRECTION INPUT ;
    USE SIGNAL ;
    PORT
      LAYER M5 ;
        RECT  130.128 0 130.152 0.084 ;
    END
  END vm_wdata[145]
  PIN vm_wdata[146]
    DIRECTION INPUT ;
    USE SIGNAL ;
    PORT
      LAYER M5 ;
        RECT  130.224 0 130.248 0.084 ;
    END
  END vm_wdata[146]
  PIN vm_wdata[147]
    DIRECTION INPUT ;
    USE SIGNAL ;
    PORT
      LAYER M5 ;
        RECT  130.32 0 130.344 0.084 ;
    END
  END vm_wdata[147]
  PIN vm_wdata[148]
    DIRECTION INPUT ;
    USE SIGNAL ;
    PORT
      LAYER M5 ;
        RECT  130.416 0 130.44 0.084 ;
    END
  END vm_wdata[148]
  PIN vm_wdata[149]
    DIRECTION INPUT ;
    USE SIGNAL ;
    PORT
      LAYER M5 ;
        RECT  130.512 0 130.536 0.084 ;
    END
  END vm_wdata[149]
  PIN vm_wdata[14]
    DIRECTION INPUT ;
    USE SIGNAL ;
    PORT
      LAYER M5 ;
        RECT  117.552 0 117.576 0.084 ;
    END
  END vm_wdata[14]
  PIN vm_wdata[150]
    DIRECTION INPUT ;
    USE SIGNAL ;
    PORT
      LAYER M5 ;
        RECT  130.608 0 130.632 0.084 ;
    END
  END vm_wdata[150]
  PIN vm_wdata[151]
    DIRECTION INPUT ;
    USE SIGNAL ;
    PORT
      LAYER M5 ;
        RECT  130.704 0 130.728 0.084 ;
    END
  END vm_wdata[151]
  PIN vm_wdata[152]
    DIRECTION INPUT ;
    USE SIGNAL ;
    PORT
      LAYER M5 ;
        RECT  130.8 0 130.824 0.084 ;
    END
  END vm_wdata[152]
  PIN vm_wdata[153]
    DIRECTION INPUT ;
    USE SIGNAL ;
    PORT
      LAYER M5 ;
        RECT  130.896 0 130.92 0.084 ;
    END
  END vm_wdata[153]
  PIN vm_wdata[154]
    DIRECTION INPUT ;
    USE SIGNAL ;
    PORT
      LAYER M5 ;
        RECT  130.992 0 131.016 0.084 ;
    END
  END vm_wdata[154]
  PIN vm_wdata[155]
    DIRECTION INPUT ;
    USE SIGNAL ;
    PORT
      LAYER M5 ;
        RECT  131.088 0 131.112 0.084 ;
    END
  END vm_wdata[155]
  PIN vm_wdata[156]
    DIRECTION INPUT ;
    USE SIGNAL ;
    PORT
      LAYER M5 ;
        RECT  131.184 0 131.208 0.084 ;
    END
  END vm_wdata[156]
  PIN vm_wdata[157]
    DIRECTION INPUT ;
    USE SIGNAL ;
    PORT
      LAYER M5 ;
        RECT  122.064 0 122.088 0.084 ;
    END
  END vm_wdata[157]
  PIN vm_wdata[158]
    DIRECTION INPUT ;
    USE SIGNAL ;
    PORT
      LAYER M5 ;
        RECT  122.16 0 122.184 0.084 ;
    END
  END vm_wdata[158]
  PIN vm_wdata[159]
    DIRECTION INPUT ;
    USE SIGNAL ;
    PORT
      LAYER M5 ;
        RECT  122.256 0 122.28 0.084 ;
    END
  END vm_wdata[159]
  PIN vm_wdata[15]
    DIRECTION INPUT ;
    USE SIGNAL ;
    PORT
      LAYER M5 ;
        RECT  117.648 0 117.672 0.084 ;
    END
  END vm_wdata[15]
  PIN vm_wdata[160]
    DIRECTION INPUT ;
    USE SIGNAL ;
    PORT
      LAYER M5 ;
        RECT  122.352 0 122.376 0.084 ;
    END
  END vm_wdata[160]
  PIN vm_wdata[161]
    DIRECTION INPUT ;
    USE SIGNAL ;
    PORT
      LAYER M5 ;
        RECT  122.448 0 122.472 0.084 ;
    END
  END vm_wdata[161]
  PIN vm_wdata[162]
    DIRECTION INPUT ;
    USE SIGNAL ;
    PORT
      LAYER M5 ;
        RECT  122.544 0 122.568 0.084 ;
    END
  END vm_wdata[162]
  PIN vm_wdata[163]
    DIRECTION INPUT ;
    USE SIGNAL ;
    PORT
      LAYER M5 ;
        RECT  122.64 0 122.664 0.084 ;
    END
  END vm_wdata[163]
  PIN vm_wdata[164]
    DIRECTION INPUT ;
    USE SIGNAL ;
    PORT
      LAYER M5 ;
        RECT  122.736 0 122.76 0.084 ;
    END
  END vm_wdata[164]
  PIN vm_wdata[165]
    DIRECTION INPUT ;
    USE SIGNAL ;
    PORT
      LAYER M5 ;
        RECT  122.832 0 122.856 0.084 ;
    END
  END vm_wdata[165]
  PIN vm_wdata[166]
    DIRECTION INPUT ;
    USE SIGNAL ;
    PORT
      LAYER M5 ;
        RECT  122.928 0 122.952 0.084 ;
    END
  END vm_wdata[166]
  PIN vm_wdata[167]
    DIRECTION INPUT ;
    USE SIGNAL ;
    PORT
      LAYER M5 ;
        RECT  123.024 0 123.048 0.084 ;
    END
  END vm_wdata[167]
  PIN vm_wdata[168]
    DIRECTION INPUT ;
    USE SIGNAL ;
    PORT
      LAYER M5 ;
        RECT  123.12 0 123.144 0.084 ;
    END
  END vm_wdata[168]
  PIN vm_wdata[169]
    DIRECTION INPUT ;
    USE SIGNAL ;
    PORT
      LAYER M5 ;
        RECT  123.216 0 123.24 0.084 ;
    END
  END vm_wdata[169]
  PIN vm_wdata[16]
    DIRECTION INPUT ;
    USE SIGNAL ;
    PORT
      LAYER M5 ;
        RECT  117.744 0 117.768 0.084 ;
    END
  END vm_wdata[16]
  PIN vm_wdata[170]
    DIRECTION INPUT ;
    USE SIGNAL ;
    PORT
      LAYER M5 ;
        RECT  123.312 0 123.336 0.084 ;
    END
  END vm_wdata[170]
  PIN vm_wdata[171]
    DIRECTION INPUT ;
    USE SIGNAL ;
    PORT
      LAYER M5 ;
        RECT  123.408 0 123.432 0.084 ;
    END
  END vm_wdata[171]
  PIN vm_wdata[172]
    DIRECTION INPUT ;
    USE SIGNAL ;
    PORT
      LAYER M5 ;
        RECT  123.504 0 123.528 0.084 ;
    END
  END vm_wdata[172]
  PIN vm_wdata[173]
    DIRECTION INPUT ;
    USE SIGNAL ;
    PORT
      LAYER M5 ;
        RECT  123.6 0 123.624 0.084 ;
    END
  END vm_wdata[173]
  PIN vm_wdata[174]
    DIRECTION INPUT ;
    USE SIGNAL ;
    PORT
      LAYER M5 ;
        RECT  123.696 0 123.72 0.084 ;
    END
  END vm_wdata[174]
  PIN vm_wdata[175]
    DIRECTION INPUT ;
    USE SIGNAL ;
    PORT
      LAYER M5 ;
        RECT  123.792 0 123.816 0.084 ;
    END
  END vm_wdata[175]
  PIN vm_wdata[176]
    DIRECTION INPUT ;
    USE SIGNAL ;
    PORT
      LAYER M5 ;
        RECT  123.888 0 123.912 0.084 ;
    END
  END vm_wdata[176]
  PIN vm_wdata[177]
    DIRECTION INPUT ;
    USE SIGNAL ;
    PORT
      LAYER M5 ;
        RECT  123.984 0 124.008 0.084 ;
    END
  END vm_wdata[177]
  PIN vm_wdata[178]
    DIRECTION INPUT ;
    USE SIGNAL ;
    PORT
      LAYER M5 ;
        RECT  124.08 0 124.104 0.084 ;
    END
  END vm_wdata[178]
  PIN vm_wdata[179]
    DIRECTION INPUT ;
    USE SIGNAL ;
    PORT
      LAYER M5 ;
        RECT  124.176 0 124.2 0.084 ;
    END
  END vm_wdata[179]
  PIN vm_wdata[17]
    DIRECTION INPUT ;
    USE SIGNAL ;
    PORT
      LAYER M5 ;
        RECT  117.84 0 117.864 0.084 ;
    END
  END vm_wdata[17]
  PIN vm_wdata[180]
    DIRECTION INPUT ;
    USE SIGNAL ;
    PORT
      LAYER M5 ;
        RECT  124.272 0 124.296 0.084 ;
    END
  END vm_wdata[180]
  PIN vm_wdata[181]
    DIRECTION INPUT ;
    USE SIGNAL ;
    PORT
      LAYER M5 ;
        RECT  124.368 0 124.392 0.084 ;
    END
  END vm_wdata[181]
  PIN vm_wdata[182]
    DIRECTION INPUT ;
    USE SIGNAL ;
    PORT
      LAYER M5 ;
        RECT  124.464 0 124.488 0.084 ;
    END
  END vm_wdata[182]
  PIN vm_wdata[183]
    DIRECTION INPUT ;
    USE SIGNAL ;
    PORT
      LAYER M5 ;
        RECT  124.56 0 124.584 0.084 ;
    END
  END vm_wdata[183]
  PIN vm_wdata[184]
    DIRECTION INPUT ;
    USE SIGNAL ;
    PORT
      LAYER M5 ;
        RECT  124.656 0 124.68 0.084 ;
    END
  END vm_wdata[184]
  PIN vm_wdata[185]
    DIRECTION INPUT ;
    USE SIGNAL ;
    PORT
      LAYER M5 ;
        RECT  124.752 0 124.776 0.084 ;
    END
  END vm_wdata[185]
  PIN vm_wdata[186]
    DIRECTION INPUT ;
    USE SIGNAL ;
    PORT
      LAYER M5 ;
        RECT  124.848 0 124.872 0.084 ;
    END
  END vm_wdata[186]
  PIN vm_wdata[187]
    DIRECTION INPUT ;
    USE SIGNAL ;
    PORT
      LAYER M5 ;
        RECT  124.944 0 124.968 0.084 ;
    END
  END vm_wdata[187]
  PIN vm_wdata[188]
    DIRECTION INPUT ;
    USE SIGNAL ;
    PORT
      LAYER M5 ;
        RECT  125.04 0 125.064 0.084 ;
    END
  END vm_wdata[188]
  PIN vm_wdata[189]
    DIRECTION INPUT ;
    USE SIGNAL ;
    PORT
      LAYER M5 ;
        RECT  112.08 0 112.104 0.084 ;
    END
  END vm_wdata[189]
  PIN vm_wdata[18]
    DIRECTION INPUT ;
    USE SIGNAL ;
    PORT
      LAYER M5 ;
        RECT  117.936 0 117.96 0.084 ;
    END
  END vm_wdata[18]
  PIN vm_wdata[190]
    DIRECTION INPUT ;
    USE SIGNAL ;
    PORT
      LAYER M5 ;
        RECT  112.176 0 112.2 0.084 ;
    END
  END vm_wdata[190]
  PIN vm_wdata[191]
    DIRECTION INPUT ;
    USE SIGNAL ;
    PORT
      LAYER M5 ;
        RECT  112.272 0 112.296 0.084 ;
    END
  END vm_wdata[191]
  PIN vm_wdata[192]
    DIRECTION INPUT ;
    USE SIGNAL ;
    PORT
      LAYER M5 ;
        RECT  112.368 0 112.392 0.084 ;
    END
  END vm_wdata[192]
  PIN vm_wdata[193]
    DIRECTION INPUT ;
    USE SIGNAL ;
    PORT
      LAYER M5 ;
        RECT  112.464 0 112.488 0.084 ;
    END
  END vm_wdata[193]
  PIN vm_wdata[194]
    DIRECTION INPUT ;
    USE SIGNAL ;
    PORT
      LAYER M5 ;
        RECT  112.56 0 112.584 0.084 ;
    END
  END vm_wdata[194]
  PIN vm_wdata[195]
    DIRECTION INPUT ;
    USE SIGNAL ;
    PORT
      LAYER M5 ;
        RECT  112.656 0 112.68 0.084 ;
    END
  END vm_wdata[195]
  PIN vm_wdata[196]
    DIRECTION INPUT ;
    USE SIGNAL ;
    PORT
      LAYER M5 ;
        RECT  112.752 0 112.776 0.084 ;
    END
  END vm_wdata[196]
  PIN vm_wdata[197]
    DIRECTION INPUT ;
    USE SIGNAL ;
    PORT
      LAYER M5 ;
        RECT  112.848 0 112.872 0.084 ;
    END
  END vm_wdata[197]
  PIN vm_wdata[198]
    DIRECTION INPUT ;
    USE SIGNAL ;
    PORT
      LAYER M5 ;
        RECT  112.944 0 112.968 0.084 ;
    END
  END vm_wdata[198]
  PIN vm_wdata[199]
    DIRECTION INPUT ;
    USE SIGNAL ;
    PORT
      LAYER M5 ;
        RECT  113.04 0 113.064 0.084 ;
    END
  END vm_wdata[199]
  PIN vm_wdata[19]
    DIRECTION INPUT ;
    USE SIGNAL ;
    PORT
      LAYER M5 ;
        RECT  118.032 0 118.056 0.084 ;
    END
  END vm_wdata[19]
  PIN vm_wdata[1]
    DIRECTION INPUT ;
    USE SIGNAL ;
    PORT
      LAYER M5 ;
        RECT  116.304 0 116.328 0.084 ;
    END
  END vm_wdata[1]
  PIN vm_wdata[200]
    DIRECTION INPUT ;
    USE SIGNAL ;
    PORT
      LAYER M5 ;
        RECT  113.136 0 113.16 0.084 ;
    END
  END vm_wdata[200]
  PIN vm_wdata[201]
    DIRECTION INPUT ;
    USE SIGNAL ;
    PORT
      LAYER M5 ;
        RECT  113.232 0 113.256 0.084 ;
    END
  END vm_wdata[201]
  PIN vm_wdata[202]
    DIRECTION INPUT ;
    USE SIGNAL ;
    PORT
      LAYER M5 ;
        RECT  113.328 0 113.352 0.084 ;
    END
  END vm_wdata[202]
  PIN vm_wdata[203]
    DIRECTION INPUT ;
    USE SIGNAL ;
    PORT
      LAYER M5 ;
        RECT  113.424 0 113.448 0.084 ;
    END
  END vm_wdata[203]
  PIN vm_wdata[204]
    DIRECTION INPUT ;
    USE SIGNAL ;
    PORT
      LAYER M5 ;
        RECT  113.52 0 113.544 0.084 ;
    END
  END vm_wdata[204]
  PIN vm_wdata[205]
    DIRECTION INPUT ;
    USE SIGNAL ;
    PORT
      LAYER M5 ;
        RECT  113.616 0 113.64 0.084 ;
    END
  END vm_wdata[205]
  PIN vm_wdata[206]
    DIRECTION INPUT ;
    USE SIGNAL ;
    PORT
      LAYER M5 ;
        RECT  113.712 0 113.736 0.084 ;
    END
  END vm_wdata[206]
  PIN vm_wdata[207]
    DIRECTION INPUT ;
    USE SIGNAL ;
    PORT
      LAYER M5 ;
        RECT  113.808 0 113.832 0.084 ;
    END
  END vm_wdata[207]
  PIN vm_wdata[208]
    DIRECTION INPUT ;
    USE SIGNAL ;
    PORT
      LAYER M5 ;
        RECT  113.904 0 113.928 0.084 ;
    END
  END vm_wdata[208]
  PIN vm_wdata[209]
    DIRECTION INPUT ;
    USE SIGNAL ;
    PORT
      LAYER M5 ;
        RECT  114 0 114.024 0.084 ;
    END
  END vm_wdata[209]
  PIN vm_wdata[20]
    DIRECTION INPUT ;
    USE SIGNAL ;
    PORT
      LAYER M5 ;
        RECT  118.128 0 118.152 0.084 ;
    END
  END vm_wdata[20]
  PIN vm_wdata[210]
    DIRECTION INPUT ;
    USE SIGNAL ;
    PORT
      LAYER M5 ;
        RECT  114.096 0 114.12 0.084 ;
    END
  END vm_wdata[210]
  PIN vm_wdata[211]
    DIRECTION INPUT ;
    USE SIGNAL ;
    PORT
      LAYER M5 ;
        RECT  114.192 0 114.216 0.084 ;
    END
  END vm_wdata[211]
  PIN vm_wdata[212]
    DIRECTION INPUT ;
    USE SIGNAL ;
    PORT
      LAYER M5 ;
        RECT  114.288 0 114.312 0.084 ;
    END
  END vm_wdata[212]
  PIN vm_wdata[213]
    DIRECTION INPUT ;
    USE SIGNAL ;
    PORT
      LAYER M5 ;
        RECT  114.384 0 114.408 0.084 ;
    END
  END vm_wdata[213]
  PIN vm_wdata[214]
    DIRECTION INPUT ;
    USE SIGNAL ;
    PORT
      LAYER M5 ;
        RECT  114.48 0 114.504 0.084 ;
    END
  END vm_wdata[214]
  PIN vm_wdata[215]
    DIRECTION INPUT ;
    USE SIGNAL ;
    PORT
      LAYER M5 ;
        RECT  114.576 0 114.6 0.084 ;
    END
  END vm_wdata[215]
  PIN vm_wdata[216]
    DIRECTION INPUT ;
    USE SIGNAL ;
    PORT
      LAYER M5 ;
        RECT  114.672 0 114.696 0.084 ;
    END
  END vm_wdata[216]
  PIN vm_wdata[217]
    DIRECTION INPUT ;
    USE SIGNAL ;
    PORT
      LAYER M5 ;
        RECT  114.768 0 114.792 0.084 ;
    END
  END vm_wdata[217]
  PIN vm_wdata[218]
    DIRECTION INPUT ;
    USE SIGNAL ;
    PORT
      LAYER M5 ;
        RECT  114.864 0 114.888 0.084 ;
    END
  END vm_wdata[218]
  PIN vm_wdata[219]
    DIRECTION INPUT ;
    USE SIGNAL ;
    PORT
      LAYER M5 ;
        RECT  114.96 0 114.984 0.084 ;
    END
  END vm_wdata[219]
  PIN vm_wdata[21]
    DIRECTION INPUT ;
    USE SIGNAL ;
    PORT
      LAYER M5 ;
        RECT  118.224 0 118.248 0.084 ;
    END
  END vm_wdata[21]
  PIN vm_wdata[220]
    DIRECTION INPUT ;
    USE SIGNAL ;
    PORT
      LAYER M5 ;
        RECT  115.056 0 115.08 0.084 ;
    END
  END vm_wdata[220]
  PIN vm_wdata[221]
    DIRECTION INPUT ;
    USE SIGNAL ;
    PORT
      LAYER M5 ;
        RECT  109.008 0 109.032 0.084 ;
    END
  END vm_wdata[221]
  PIN vm_wdata[222]
    DIRECTION INPUT ;
    USE SIGNAL ;
    PORT
      LAYER M5 ;
        RECT  109.104 0 109.128 0.084 ;
    END
  END vm_wdata[222]
  PIN vm_wdata[223]
    DIRECTION INPUT ;
    USE SIGNAL ;
    PORT
      LAYER M5 ;
        RECT  109.2 0 109.224 0.084 ;
    END
  END vm_wdata[223]
  PIN vm_wdata[224]
    DIRECTION INPUT ;
    USE SIGNAL ;
    PORT
      LAYER M5 ;
        RECT  109.296 0 109.32 0.084 ;
    END
  END vm_wdata[224]
  PIN vm_wdata[225]
    DIRECTION INPUT ;
    USE SIGNAL ;
    PORT
      LAYER M5 ;
        RECT  109.392 0 109.416 0.084 ;
    END
  END vm_wdata[225]
  PIN vm_wdata[226]
    DIRECTION INPUT ;
    USE SIGNAL ;
    PORT
      LAYER M5 ;
        RECT  109.488 0 109.512 0.084 ;
    END
  END vm_wdata[226]
  PIN vm_wdata[227]
    DIRECTION INPUT ;
    USE SIGNAL ;
    PORT
      LAYER M5 ;
        RECT  109.584 0 109.608 0.084 ;
    END
  END vm_wdata[227]
  PIN vm_wdata[228]
    DIRECTION INPUT ;
    USE SIGNAL ;
    PORT
      LAYER M5 ;
        RECT  109.68 0 109.704 0.084 ;
    END
  END vm_wdata[228]
  PIN vm_wdata[229]
    DIRECTION INPUT ;
    USE SIGNAL ;
    PORT
      LAYER M5 ;
        RECT  109.776 0 109.8 0.084 ;
    END
  END vm_wdata[229]
  PIN vm_wdata[22]
    DIRECTION INPUT ;
    USE SIGNAL ;
    PORT
      LAYER M5 ;
        RECT  118.32 0 118.344 0.084 ;
    END
  END vm_wdata[22]
  PIN vm_wdata[230]
    DIRECTION INPUT ;
    USE SIGNAL ;
    PORT
      LAYER M5 ;
        RECT  109.872 0 109.896 0.084 ;
    END
  END vm_wdata[230]
  PIN vm_wdata[231]
    DIRECTION INPUT ;
    USE SIGNAL ;
    PORT
      LAYER M5 ;
        RECT  109.968 0 109.992 0.084 ;
    END
  END vm_wdata[231]
  PIN vm_wdata[232]
    DIRECTION INPUT ;
    USE SIGNAL ;
    PORT
      LAYER M5 ;
        RECT  110.064 0 110.088 0.084 ;
    END
  END vm_wdata[232]
  PIN vm_wdata[233]
    DIRECTION INPUT ;
    USE SIGNAL ;
    PORT
      LAYER M5 ;
        RECT  110.16 0 110.184 0.084 ;
    END
  END vm_wdata[233]
  PIN vm_wdata[234]
    DIRECTION INPUT ;
    USE SIGNAL ;
    PORT
      LAYER M5 ;
        RECT  110.256 0 110.28 0.084 ;
    END
  END vm_wdata[234]
  PIN vm_wdata[235]
    DIRECTION INPUT ;
    USE SIGNAL ;
    PORT
      LAYER M5 ;
        RECT  110.352 0 110.376 0.084 ;
    END
  END vm_wdata[235]
  PIN vm_wdata[236]
    DIRECTION INPUT ;
    USE SIGNAL ;
    PORT
      LAYER M5 ;
        RECT  110.448 0 110.472 0.084 ;
    END
  END vm_wdata[236]
  PIN vm_wdata[237]
    DIRECTION INPUT ;
    USE SIGNAL ;
    PORT
      LAYER M5 ;
        RECT  110.544 0 110.568 0.084 ;
    END
  END vm_wdata[237]
  PIN vm_wdata[238]
    DIRECTION INPUT ;
    USE SIGNAL ;
    PORT
      LAYER M5 ;
        RECT  110.64 0 110.664 0.084 ;
    END
  END vm_wdata[238]
  PIN vm_wdata[239]
    DIRECTION INPUT ;
    USE SIGNAL ;
    PORT
      LAYER M5 ;
        RECT  110.736 0 110.76 0.084 ;
    END
  END vm_wdata[239]
  PIN vm_wdata[23]
    DIRECTION INPUT ;
    USE SIGNAL ;
    PORT
      LAYER M5 ;
        RECT  118.416 0 118.44 0.084 ;
    END
  END vm_wdata[23]
  PIN vm_wdata[240]
    DIRECTION INPUT ;
    USE SIGNAL ;
    PORT
      LAYER M5 ;
        RECT  110.832 0 110.856 0.084 ;
    END
  END vm_wdata[240]
  PIN vm_wdata[241]
    DIRECTION INPUT ;
    USE SIGNAL ;
    PORT
      LAYER M5 ;
        RECT  110.928 0 110.952 0.084 ;
    END
  END vm_wdata[241]
  PIN vm_wdata[242]
    DIRECTION INPUT ;
    USE SIGNAL ;
    PORT
      LAYER M5 ;
        RECT  111.024 0 111.048 0.084 ;
    END
  END vm_wdata[242]
  PIN vm_wdata[243]
    DIRECTION INPUT ;
    USE SIGNAL ;
    PORT
      LAYER M5 ;
        RECT  111.12 0 111.144 0.084 ;
    END
  END vm_wdata[243]
  PIN vm_wdata[244]
    DIRECTION INPUT ;
    USE SIGNAL ;
    PORT
      LAYER M5 ;
        RECT  111.216 0 111.24 0.084 ;
    END
  END vm_wdata[244]
  PIN vm_wdata[245]
    DIRECTION INPUT ;
    USE SIGNAL ;
    PORT
      LAYER M5 ;
        RECT  111.312 0 111.336 0.084 ;
    END
  END vm_wdata[245]
  PIN vm_wdata[246]
    DIRECTION INPUT ;
    USE SIGNAL ;
    PORT
      LAYER M5 ;
        RECT  111.408 0 111.432 0.084 ;
    END
  END vm_wdata[246]
  PIN vm_wdata[247]
    DIRECTION INPUT ;
    USE SIGNAL ;
    PORT
      LAYER M5 ;
        RECT  111.504 0 111.528 0.084 ;
    END
  END vm_wdata[247]
  PIN vm_wdata[248]
    DIRECTION INPUT ;
    USE SIGNAL ;
    PORT
      LAYER M5 ;
        RECT  111.6 0 111.624 0.084 ;
    END
  END vm_wdata[248]
  PIN vm_wdata[249]
    DIRECTION INPUT ;
    USE SIGNAL ;
    PORT
      LAYER M5 ;
        RECT  111.696 0 111.72 0.084 ;
    END
  END vm_wdata[249]
  PIN vm_wdata[24]
    DIRECTION INPUT ;
    USE SIGNAL ;
    PORT
      LAYER M5 ;
        RECT  118.512 0 118.536 0.084 ;
    END
  END vm_wdata[24]
  PIN vm_wdata[250]
    DIRECTION INPUT ;
    USE SIGNAL ;
    PORT
      LAYER M5 ;
        RECT  111.792 0 111.816 0.084 ;
    END
  END vm_wdata[250]
  PIN vm_wdata[251]
    DIRECTION INPUT ;
    USE SIGNAL ;
    PORT
      LAYER M5 ;
        RECT  111.888 0 111.912 0.084 ;
    END
  END vm_wdata[251]
  PIN vm_wdata[252]
    DIRECTION INPUT ;
    USE SIGNAL ;
    PORT
      LAYER M5 ;
        RECT  111.984 0 112.008 0.084 ;
    END
  END vm_wdata[252]
  PIN vm_wdata[253]
    DIRECTION INPUT ;
    USE SIGNAL ;
    PORT
      LAYER M5 ;
        RECT  73.68 0 73.704 0.084 ;
    END
  END vm_wdata[253]
  PIN vm_wdata[254]
    DIRECTION INPUT ;
    USE SIGNAL ;
    PORT
      LAYER M5 ;
        RECT  73.776 0 73.8 0.084 ;
    END
  END vm_wdata[254]
  PIN vm_wdata[255]
    DIRECTION INPUT ;
    USE SIGNAL ;
    PORT
      LAYER M5 ;
        RECT  73.872 0 73.896 0.084 ;
    END
  END vm_wdata[255]
  PIN vm_wdata[25]
    DIRECTION INPUT ;
    USE SIGNAL ;
    PORT
      LAYER M5 ;
        RECT  118.608 0 118.632 0.084 ;
    END
  END vm_wdata[25]
  PIN vm_wdata[26]
    DIRECTION INPUT ;
    USE SIGNAL ;
    PORT
      LAYER M5 ;
        RECT  118.704 0 118.728 0.084 ;
    END
  END vm_wdata[26]
  PIN vm_wdata[27]
    DIRECTION INPUT ;
    USE SIGNAL ;
    PORT
      LAYER M5 ;
        RECT  118.8 0 118.824 0.084 ;
    END
  END vm_wdata[27]
  PIN vm_wdata[28]
    DIRECTION INPUT ;
    USE SIGNAL ;
    PORT
      LAYER M5 ;
        RECT  118.896 0 118.92 0.084 ;
    END
  END vm_wdata[28]
  PIN vm_wdata[29]
    DIRECTION INPUT ;
    USE SIGNAL ;
    PORT
      LAYER M5 ;
        RECT  118.992 0 119.016 0.084 ;
    END
  END vm_wdata[29]
  PIN vm_wdata[2]
    DIRECTION INPUT ;
    USE SIGNAL ;
    PORT
      LAYER M5 ;
        RECT  116.4 0 116.424 0.084 ;
    END
  END vm_wdata[2]
  PIN vm_wdata[30]
    DIRECTION INPUT ;
    USE SIGNAL ;
    PORT
      LAYER M5 ;
        RECT  119.088 0 119.112 0.084 ;
    END
  END vm_wdata[30]
  PIN vm_wdata[31]
    DIRECTION INPUT ;
    USE SIGNAL ;
    PORT
      LAYER M5 ;
        RECT  119.184 0 119.208 0.084 ;
    END
  END vm_wdata[31]
  PIN vm_wdata[32]
    DIRECTION INPUT ;
    USE SIGNAL ;
    PORT
      LAYER M5 ;
        RECT  119.28 0 119.304 0.084 ;
    END
  END vm_wdata[32]
  PIN vm_wdata[33]
    DIRECTION INPUT ;
    USE SIGNAL ;
    PORT
      LAYER M5 ;
        RECT  119.376 0 119.4 0.084 ;
    END
  END vm_wdata[33]
  PIN vm_wdata[34]
    DIRECTION INPUT ;
    USE SIGNAL ;
    PORT
      LAYER M5 ;
        RECT  119.472 0 119.496 0.084 ;
    END
  END vm_wdata[34]
  PIN vm_wdata[35]
    DIRECTION INPUT ;
    USE SIGNAL ;
    PORT
      LAYER M5 ;
        RECT  119.568 0 119.592 0.084 ;
    END
  END vm_wdata[35]
  PIN vm_wdata[36]
    DIRECTION INPUT ;
    USE SIGNAL ;
    PORT
      LAYER M5 ;
        RECT  119.664 0 119.688 0.084 ;
    END
  END vm_wdata[36]
  PIN vm_wdata[37]
    DIRECTION INPUT ;
    USE SIGNAL ;
    PORT
      LAYER M5 ;
        RECT  119.76 0 119.784 0.084 ;
    END
  END vm_wdata[37]
  PIN vm_wdata[38]
    DIRECTION INPUT ;
    USE SIGNAL ;
    PORT
      LAYER M5 ;
        RECT  119.856 0 119.88 0.084 ;
    END
  END vm_wdata[38]
  PIN vm_wdata[39]
    DIRECTION INPUT ;
    USE SIGNAL ;
    PORT
      LAYER M5 ;
        RECT  119.952 0 119.976 0.084 ;
    END
  END vm_wdata[39]
  PIN vm_wdata[3]
    DIRECTION INPUT ;
    USE SIGNAL ;
    PORT
      LAYER M5 ;
        RECT  116.496 0 116.52 0.084 ;
    END
  END vm_wdata[3]
  PIN vm_wdata[40]
    DIRECTION INPUT ;
    USE SIGNAL ;
    PORT
      LAYER M5 ;
        RECT  120.048 0 120.072 0.084 ;
    END
  END vm_wdata[40]
  PIN vm_wdata[41]
    DIRECTION INPUT ;
    USE SIGNAL ;
    PORT
      LAYER M5 ;
        RECT  120.144 0 120.168 0.084 ;
    END
  END vm_wdata[41]
  PIN vm_wdata[42]
    DIRECTION INPUT ;
    USE SIGNAL ;
    PORT
      LAYER M5 ;
        RECT  120.24 0 120.264 0.084 ;
    END
  END vm_wdata[42]
  PIN vm_wdata[43]
    DIRECTION INPUT ;
    USE SIGNAL ;
    PORT
      LAYER M5 ;
        RECT  120.336 0 120.36 0.084 ;
    END
  END vm_wdata[43]
  PIN vm_wdata[44]
    DIRECTION INPUT ;
    USE SIGNAL ;
    PORT
      LAYER M5 ;
        RECT  120.432 0 120.456 0.084 ;
    END
  END vm_wdata[44]
  PIN vm_wdata[45]
    DIRECTION INPUT ;
    USE SIGNAL ;
    PORT
      LAYER M5 ;
        RECT  120.528 0 120.552 0.084 ;
    END
  END vm_wdata[45]
  PIN vm_wdata[46]
    DIRECTION INPUT ;
    USE SIGNAL ;
    PORT
      LAYER M5 ;
        RECT  120.624 0 120.648 0.084 ;
    END
  END vm_wdata[46]
  PIN vm_wdata[47]
    DIRECTION INPUT ;
    USE SIGNAL ;
    PORT
      LAYER M5 ;
        RECT  120.72 0 120.744 0.084 ;
    END
  END vm_wdata[47]
  PIN vm_wdata[48]
    DIRECTION INPUT ;
    USE SIGNAL ;
    PORT
      LAYER M5 ;
        RECT  120.816 0 120.84 0.084 ;
    END
  END vm_wdata[48]
  PIN vm_wdata[49]
    DIRECTION INPUT ;
    USE SIGNAL ;
    PORT
      LAYER M5 ;
        RECT  120.912 0 120.936 0.084 ;
    END
  END vm_wdata[49]
  PIN vm_wdata[4]
    DIRECTION INPUT ;
    USE SIGNAL ;
    PORT
      LAYER M5 ;
        RECT  116.592 0 116.616 0.084 ;
    END
  END vm_wdata[4]
  PIN vm_wdata[50]
    DIRECTION INPUT ;
    USE SIGNAL ;
    PORT
      LAYER M5 ;
        RECT  121.008 0 121.032 0.084 ;
    END
  END vm_wdata[50]
  PIN vm_wdata[51]
    DIRECTION INPUT ;
    USE SIGNAL ;
    PORT
      LAYER M5 ;
        RECT  121.104 0 121.128 0.084 ;
    END
  END vm_wdata[51]
  PIN vm_wdata[52]
    DIRECTION INPUT ;
    USE SIGNAL ;
    PORT
      LAYER M5 ;
        RECT  121.2 0 121.224 0.084 ;
    END
  END vm_wdata[52]
  PIN vm_wdata[53]
    DIRECTION INPUT ;
    USE SIGNAL ;
    PORT
      LAYER M5 ;
        RECT  121.296 0 121.32 0.084 ;
    END
  END vm_wdata[53]
  PIN vm_wdata[54]
    DIRECTION INPUT ;
    USE SIGNAL ;
    PORT
      LAYER M5 ;
        RECT  121.392 0 121.416 0.084 ;
    END
  END vm_wdata[54]
  PIN vm_wdata[55]
    DIRECTION INPUT ;
    USE SIGNAL ;
    PORT
      LAYER M5 ;
        RECT  121.488 0 121.512 0.084 ;
    END
  END vm_wdata[55]
  PIN vm_wdata[56]
    DIRECTION INPUT ;
    USE SIGNAL ;
    PORT
      LAYER M5 ;
        RECT  121.584 0 121.608 0.084 ;
    END
  END vm_wdata[56]
  PIN vm_wdata[57]
    DIRECTION INPUT ;
    USE SIGNAL ;
    PORT
      LAYER M5 ;
        RECT  121.68 0 121.704 0.084 ;
    END
  END vm_wdata[57]
  PIN vm_wdata[58]
    DIRECTION INPUT ;
    USE SIGNAL ;
    PORT
      LAYER M5 ;
        RECT  121.776 0 121.8 0.084 ;
    END
  END vm_wdata[58]
  PIN vm_wdata[59]
    DIRECTION INPUT ;
    USE SIGNAL ;
    PORT
      LAYER M5 ;
        RECT  121.872 0 121.896 0.084 ;
    END
  END vm_wdata[59]
  PIN vm_wdata[5]
    DIRECTION INPUT ;
    USE SIGNAL ;
    PORT
      LAYER M5 ;
        RECT  116.688 0 116.712 0.084 ;
    END
  END vm_wdata[5]
  PIN vm_wdata[60]
    DIRECTION INPUT ;
    USE SIGNAL ;
    PORT
      LAYER M5 ;
        RECT  121.968 0 121.992 0.084 ;
    END
  END vm_wdata[60]
  PIN vm_wdata[61]
    DIRECTION INPUT ;
    USE SIGNAL ;
    PORT
      LAYER M5 ;
        RECT  131.28 0 131.304 0.084 ;
    END
  END vm_wdata[61]
  PIN vm_wdata[62]
    DIRECTION INPUT ;
    USE SIGNAL ;
    PORT
      LAYER M5 ;
        RECT  131.376 0 131.4 0.084 ;
    END
  END vm_wdata[62]
  PIN vm_wdata[63]
    DIRECTION INPUT ;
    USE SIGNAL ;
    PORT
      LAYER M5 ;
        RECT  131.472 0 131.496 0.084 ;
    END
  END vm_wdata[63]
  PIN vm_wdata[64]
    DIRECTION INPUT ;
    USE SIGNAL ;
    PORT
      LAYER M5 ;
        RECT  131.568 0 131.592 0.084 ;
    END
  END vm_wdata[64]
  PIN vm_wdata[65]
    DIRECTION INPUT ;
    USE SIGNAL ;
    PORT
      LAYER M5 ;
        RECT  131.664 0 131.688 0.084 ;
    END
  END vm_wdata[65]
  PIN vm_wdata[66]
    DIRECTION INPUT ;
    USE SIGNAL ;
    PORT
      LAYER M5 ;
        RECT  131.76 0 131.784 0.084 ;
    END
  END vm_wdata[66]
  PIN vm_wdata[67]
    DIRECTION INPUT ;
    USE SIGNAL ;
    PORT
      LAYER M5 ;
        RECT  131.856 0 131.88 0.084 ;
    END
  END vm_wdata[67]
  PIN vm_wdata[68]
    DIRECTION INPUT ;
    USE SIGNAL ;
    PORT
      LAYER M5 ;
        RECT  131.952 0 131.976 0.084 ;
    END
  END vm_wdata[68]
  PIN vm_wdata[69]
    DIRECTION INPUT ;
    USE SIGNAL ;
    PORT
      LAYER M5 ;
        RECT  132.048 0 132.072 0.084 ;
    END
  END vm_wdata[69]
  PIN vm_wdata[6]
    DIRECTION INPUT ;
    USE SIGNAL ;
    PORT
      LAYER M5 ;
        RECT  116.784 0 116.808 0.084 ;
    END
  END vm_wdata[6]
  PIN vm_wdata[70]
    DIRECTION INPUT ;
    USE SIGNAL ;
    PORT
      LAYER M5 ;
        RECT  132.144 0 132.168 0.084 ;
    END
  END vm_wdata[70]
  PIN vm_wdata[71]
    DIRECTION INPUT ;
    USE SIGNAL ;
    PORT
      LAYER M5 ;
        RECT  132.24 0 132.264 0.084 ;
    END
  END vm_wdata[71]
  PIN vm_wdata[72]
    DIRECTION INPUT ;
    USE SIGNAL ;
    PORT
      LAYER M5 ;
        RECT  132.336 0 132.36 0.084 ;
    END
  END vm_wdata[72]
  PIN vm_wdata[73]
    DIRECTION INPUT ;
    USE SIGNAL ;
    PORT
      LAYER M5 ;
        RECT  132.432 0 132.456 0.084 ;
    END
  END vm_wdata[73]
  PIN vm_wdata[74]
    DIRECTION INPUT ;
    USE SIGNAL ;
    PORT
      LAYER M5 ;
        RECT  132.528 0 132.552 0.084 ;
    END
  END vm_wdata[74]
  PIN vm_wdata[75]
    DIRECTION INPUT ;
    USE SIGNAL ;
    PORT
      LAYER M5 ;
        RECT  132.624 0 132.648 0.084 ;
    END
  END vm_wdata[75]
  PIN vm_wdata[76]
    DIRECTION INPUT ;
    USE SIGNAL ;
    PORT
      LAYER M5 ;
        RECT  132.72 0 132.744 0.084 ;
    END
  END vm_wdata[76]
  PIN vm_wdata[77]
    DIRECTION INPUT ;
    USE SIGNAL ;
    PORT
      LAYER M5 ;
        RECT  132.816 0 132.84 0.084 ;
    END
  END vm_wdata[77]
  PIN vm_wdata[78]
    DIRECTION INPUT ;
    USE SIGNAL ;
    PORT
      LAYER M5 ;
        RECT  132.912 0 132.936 0.084 ;
    END
  END vm_wdata[78]
  PIN vm_wdata[79]
    DIRECTION INPUT ;
    USE SIGNAL ;
    PORT
      LAYER M5 ;
        RECT  133.008 0 133.032 0.084 ;
    END
  END vm_wdata[79]
  PIN vm_wdata[7]
    DIRECTION INPUT ;
    USE SIGNAL ;
    PORT
      LAYER M5 ;
        RECT  116.88 0 116.904 0.084 ;
    END
  END vm_wdata[7]
  PIN vm_wdata[80]
    DIRECTION INPUT ;
    USE SIGNAL ;
    PORT
      LAYER M5 ;
        RECT  133.104 0 133.128 0.084 ;
    END
  END vm_wdata[80]
  PIN vm_wdata[81]
    DIRECTION INPUT ;
    USE SIGNAL ;
    PORT
      LAYER M5 ;
        RECT  133.2 0 133.224 0.084 ;
    END
  END vm_wdata[81]
  PIN vm_wdata[82]
    DIRECTION INPUT ;
    USE SIGNAL ;
    PORT
      LAYER M5 ;
        RECT  133.296 0 133.32 0.084 ;
    END
  END vm_wdata[82]
  PIN vm_wdata[83]
    DIRECTION INPUT ;
    USE SIGNAL ;
    PORT
      LAYER M5 ;
        RECT  133.392 0 133.416 0.084 ;
    END
  END vm_wdata[83]
  PIN vm_wdata[84]
    DIRECTION INPUT ;
    USE SIGNAL ;
    PORT
      LAYER M5 ;
        RECT  133.488 0 133.512 0.084 ;
    END
  END vm_wdata[84]
  PIN vm_wdata[85]
    DIRECTION INPUT ;
    USE SIGNAL ;
    PORT
      LAYER M5 ;
        RECT  133.584 0 133.608 0.084 ;
    END
  END vm_wdata[85]
  PIN vm_wdata[86]
    DIRECTION INPUT ;
    USE SIGNAL ;
    PORT
      LAYER M5 ;
        RECT  133.68 0 133.704 0.084 ;
    END
  END vm_wdata[86]
  PIN vm_wdata[87]
    DIRECTION INPUT ;
    USE SIGNAL ;
    PORT
      LAYER M5 ;
        RECT  133.776 0 133.8 0.084 ;
    END
  END vm_wdata[87]
  PIN vm_wdata[88]
    DIRECTION INPUT ;
    USE SIGNAL ;
    PORT
      LAYER M5 ;
        RECT  133.872 0 133.896 0.084 ;
    END
  END vm_wdata[88]
  PIN vm_wdata[89]
    DIRECTION INPUT ;
    USE SIGNAL ;
    PORT
      LAYER M5 ;
        RECT  133.968 0 133.992 0.084 ;
    END
  END vm_wdata[89]
  PIN vm_wdata[8]
    DIRECTION INPUT ;
    USE SIGNAL ;
    PORT
      LAYER M5 ;
        RECT  116.976 0 117 0.084 ;
    END
  END vm_wdata[8]
  PIN vm_wdata[90]
    DIRECTION INPUT ;
    USE SIGNAL ;
    PORT
      LAYER M5 ;
        RECT  134.064 0 134.088 0.084 ;
    END
  END vm_wdata[90]
  PIN vm_wdata[91]
    DIRECTION INPUT ;
    USE SIGNAL ;
    PORT
      LAYER M5 ;
        RECT  134.16 0 134.184 0.084 ;
    END
  END vm_wdata[91]
  PIN vm_wdata[92]
    DIRECTION INPUT ;
    USE SIGNAL ;
    PORT
      LAYER M5 ;
        RECT  134.256 0 134.28 0.084 ;
    END
  END vm_wdata[92]
  PIN vm_wdata[93]
    DIRECTION INPUT ;
    USE SIGNAL ;
    PORT
      LAYER M5 ;
        RECT  125.136 0 125.16 0.084 ;
    END
  END vm_wdata[93]
  PIN vm_wdata[94]
    DIRECTION INPUT ;
    USE SIGNAL ;
    PORT
      LAYER M5 ;
        RECT  125.232 0 125.256 0.084 ;
    END
  END vm_wdata[94]
  PIN vm_wdata[95]
    DIRECTION INPUT ;
    USE SIGNAL ;
    PORT
      LAYER M5 ;
        RECT  125.328 0 125.352 0.084 ;
    END
  END vm_wdata[95]
  PIN vm_wdata[96]
    DIRECTION INPUT ;
    USE SIGNAL ;
    PORT
      LAYER M5 ;
        RECT  125.424 0 125.448 0.084 ;
    END
  END vm_wdata[96]
  PIN vm_wdata[97]
    DIRECTION INPUT ;
    USE SIGNAL ;
    PORT
      LAYER M5 ;
        RECT  125.52 0 125.544 0.084 ;
    END
  END vm_wdata[97]
  PIN vm_wdata[98]
    DIRECTION INPUT ;
    USE SIGNAL ;
    PORT
      LAYER M5 ;
        RECT  125.616 0 125.64 0.084 ;
    END
  END vm_wdata[98]
  PIN vm_wdata[99]
    DIRECTION INPUT ;
    USE SIGNAL ;
    PORT
      LAYER M5 ;
        RECT  125.712 0 125.736 0.084 ;
    END
  END vm_wdata[99]
  PIN vm_wdata[9]
    DIRECTION INPUT ;
    USE SIGNAL ;
    PORT
      LAYER M5 ;
        RECT  117.072 0 117.096 0.084 ;
    END
  END vm_wdata[9]
  PIN vm_we[0]
    DIRECTION INPUT ;
    USE SIGNAL ;
    PORT
      LAYER M5 ;
        RECT  73.968 0 73.992 0.084 ;
    END
  END vm_we[0]
  PIN vm_we[1]
    DIRECTION INPUT ;
    USE SIGNAL ;
    PORT
      LAYER M5 ;
        RECT  74.064 0 74.088 0.084 ;
    END
  END vm_we[1]
  PIN vm_we[2]
    DIRECTION INPUT ;
    USE SIGNAL ;
    PORT
      LAYER M5 ;
        RECT  74.16 0 74.184 0.084 ;
    END
  END vm_we[2]
  PIN vm_we[3]
    DIRECTION INPUT ;
    USE SIGNAL ;
    PORT
      LAYER M5 ;
        RECT  74.256 0 74.28 0.084 ;
    END
  END vm_we[3]
  PIN vm_we[4]
    DIRECTION INPUT ;
    USE SIGNAL ;
    PORT
      LAYER M5 ;
        RECT  74.352 0 74.376 0.084 ;
    END
  END vm_we[4]
  PIN vm_we[5]
    DIRECTION INPUT ;
    USE SIGNAL ;
    PORT
      LAYER M5 ;
        RECT  74.448 0 74.472 0.084 ;
    END
  END vm_we[5]
  PIN vm_we[6]
    DIRECTION INPUT ;
    USE SIGNAL ;
    PORT
      LAYER M5 ;
        RECT  74.544 0 74.568 0.084 ;
    END
  END vm_we[6]
  PIN vm_we[7]
    DIRECTION INPUT ;
    USE SIGNAL ;
    PORT
      LAYER M5 ;
        RECT  74.64 0 74.664 0.084 ;
    END
  END vm_we[7]
  PIN w16_addr[0]
    DIRECTION INPUT ;
    USE SIGNAL ;
    PORT
      LAYER M5 ;
        RECT  70.992 0 71.016 0.084 ;
    END
  END w16_addr[0]
  PIN w16_addr[10]
    DIRECTION INPUT ;
    USE SIGNAL ;
    PORT
      LAYER M5 ;
        RECT  71.952 0 71.976 0.084 ;
    END
  END w16_addr[10]
  PIN w16_addr[11]
    DIRECTION INPUT ;
    USE SIGNAL ;
    PORT
      LAYER M5 ;
        RECT  72.048 0 72.072 0.084 ;
    END
  END w16_addr[11]
  PIN w16_addr[12]
    DIRECTION INPUT ;
    USE SIGNAL ;
    PORT
      LAYER M5 ;
        RECT  72.144 0 72.168 0.084 ;
    END
  END w16_addr[12]
  PIN w16_addr[13]
    DIRECTION INPUT ;
    USE SIGNAL ;
    PORT
      LAYER M5 ;
        RECT  72.24 0 72.264 0.084 ;
    END
  END w16_addr[13]
  PIN w16_addr[14]
    DIRECTION INPUT ;
    USE SIGNAL ;
    PORT
      LAYER M5 ;
        RECT  72.336 0 72.36 0.084 ;
    END
  END w16_addr[14]
  PIN w16_addr[15]
    DIRECTION INPUT ;
    USE SIGNAL ;
    PORT
      LAYER M5 ;
        RECT  72.432 0 72.456 0.084 ;
    END
  END w16_addr[15]
  PIN w16_addr[16]
    DIRECTION INPUT ;
    USE SIGNAL ;
    PORT
      LAYER M5 ;
        RECT  72.528 0 72.552 0.084 ;
    END
  END w16_addr[16]
  PIN w16_addr[17]
    DIRECTION INPUT ;
    USE SIGNAL ;
    PORT
      LAYER M5 ;
        RECT  72.624 0 72.648 0.084 ;
    END
  END w16_addr[17]
  PIN w16_addr[18]
    DIRECTION INPUT ;
    USE SIGNAL ;
    PORT
      LAYER M5 ;
        RECT  72.72 0 72.744 0.084 ;
    END
  END w16_addr[18]
  PIN w16_addr[19]
    DIRECTION INPUT ;
    USE SIGNAL ;
    PORT
      LAYER M5 ;
        RECT  72.816 0 72.84 0.084 ;
    END
  END w16_addr[19]
  PIN w16_addr[1]
    DIRECTION INPUT ;
    USE SIGNAL ;
    PORT
      LAYER M5 ;
        RECT  71.088 0 71.112 0.084 ;
    END
  END w16_addr[1]
  PIN w16_addr[20]
    DIRECTION INPUT ;
    USE SIGNAL ;
    PORT
      LAYER M5 ;
        RECT  72.912 0 72.936 0.084 ;
    END
  END w16_addr[20]
  PIN w16_addr[21]
    DIRECTION INPUT ;
    USE SIGNAL ;
    PORT
      LAYER M5 ;
        RECT  73.008 0 73.032 0.084 ;
    END
  END w16_addr[21]
  PIN w16_addr[22]
    DIRECTION INPUT ;
    USE SIGNAL ;
    PORT
      LAYER M5 ;
        RECT  73.104 0 73.128 0.084 ;
    END
  END w16_addr[22]
  PIN w16_addr[23]
    DIRECTION INPUT ;
    USE SIGNAL ;
    PORT
      LAYER M5 ;
        RECT  73.2 0 73.224 0.084 ;
    END
  END w16_addr[23]
  PIN w16_addr[2]
    DIRECTION INPUT ;
    USE SIGNAL ;
    PORT
      LAYER M5 ;
        RECT  71.184 0 71.208 0.084 ;
    END
  END w16_addr[2]
  PIN w16_addr[3]
    DIRECTION INPUT ;
    USE SIGNAL ;
    PORT
      LAYER M5 ;
        RECT  71.28 0 71.304 0.084 ;
    END
  END w16_addr[3]
  PIN w16_addr[4]
    DIRECTION INPUT ;
    USE SIGNAL ;
    PORT
      LAYER M5 ;
        RECT  71.376 0 71.4 0.084 ;
    END
  END w16_addr[4]
  PIN w16_addr[5]
    DIRECTION INPUT ;
    USE SIGNAL ;
    PORT
      LAYER M5 ;
        RECT  71.472 0 71.496 0.084 ;
    END
  END w16_addr[5]
  PIN w16_addr[6]
    DIRECTION INPUT ;
    USE SIGNAL ;
    PORT
      LAYER M5 ;
        RECT  71.568 0 71.592 0.084 ;
    END
  END w16_addr[6]
  PIN w16_addr[7]
    DIRECTION INPUT ;
    USE SIGNAL ;
    PORT
      LAYER M5 ;
        RECT  71.664 0 71.688 0.084 ;
    END
  END w16_addr[7]
  PIN w16_addr[8]
    DIRECTION INPUT ;
    USE SIGNAL ;
    PORT
      LAYER M5 ;
        RECT  71.76 0 71.784 0.084 ;
    END
  END w16_addr[8]
  PIN w16_addr[9]
    DIRECTION INPUT ;
    USE SIGNAL ;
    PORT
      LAYER M5 ;
        RECT  71.856 0 71.88 0.084 ;
    END
  END w16_addr[9]
  PIN w16_data[0]
    DIRECTION INPUT ;
    USE SIGNAL ;
    PORT
      LAYER M5 ;
        RECT  73.296 0 73.32 0.084 ;
    END
  END w16_data[0]
  PIN w16_data[100]
    DIRECTION INPUT ;
    USE SIGNAL ;
    PORT
      LAYER M5 ;
        RECT  67.536 0 67.56 0.084 ;
    END
  END w16_data[100]
  PIN w16_data[101]
    DIRECTION INPUT ;
    USE SIGNAL ;
    PORT
      LAYER M5 ;
        RECT  67.632 0 67.656 0.084 ;
    END
  END w16_data[101]
  PIN w16_data[102]
    DIRECTION INPUT ;
    USE SIGNAL ;
    PORT
      LAYER M5 ;
        RECT  67.728 0 67.752 0.084 ;
    END
  END w16_data[102]
  PIN w16_data[103]
    DIRECTION INPUT ;
    USE SIGNAL ;
    PORT
      LAYER M5 ;
        RECT  67.824 0 67.848 0.084 ;
    END
  END w16_data[103]
  PIN w16_data[104]
    DIRECTION INPUT ;
    USE SIGNAL ;
    PORT
      LAYER M5 ;
        RECT  67.92 0 67.944 0.084 ;
    END
  END w16_data[104]
  PIN w16_data[105]
    DIRECTION INPUT ;
    USE SIGNAL ;
    PORT
      LAYER M5 ;
        RECT  68.016 0 68.04 0.084 ;
    END
  END w16_data[105]
  PIN w16_data[106]
    DIRECTION INPUT ;
    USE SIGNAL ;
    PORT
      LAYER M5 ;
        RECT  68.112 0 68.136 0.084 ;
    END
  END w16_data[106]
  PIN w16_data[107]
    DIRECTION INPUT ;
    USE SIGNAL ;
    PORT
      LAYER M5 ;
        RECT  68.208 0 68.232 0.084 ;
    END
  END w16_data[107]
  PIN w16_data[108]
    DIRECTION INPUT ;
    USE SIGNAL ;
    PORT
      LAYER M5 ;
        RECT  68.304 0 68.328 0.084 ;
    END
  END w16_data[108]
  PIN w16_data[109]
    DIRECTION INPUT ;
    USE SIGNAL ;
    PORT
      LAYER M5 ;
        RECT  68.4 0 68.424 0.084 ;
    END
  END w16_data[109]
  PIN w16_data[10]
    DIRECTION INPUT ;
    USE SIGNAL ;
    PORT
      LAYER M5 ;
        RECT  65.04 0 65.064 0.084 ;
    END
  END w16_data[10]
  PIN w16_data[110]
    DIRECTION INPUT ;
    USE SIGNAL ;
    PORT
      LAYER M5 ;
        RECT  68.496 0 68.52 0.084 ;
    END
  END w16_data[110]
  PIN w16_data[111]
    DIRECTION INPUT ;
    USE SIGNAL ;
    PORT
      LAYER M5 ;
        RECT  68.592 0 68.616 0.084 ;
    END
  END w16_data[111]
  PIN w16_data[112]
    DIRECTION INPUT ;
    USE SIGNAL ;
    PORT
      LAYER M5 ;
        RECT  68.688 0 68.712 0.084 ;
    END
  END w16_data[112]
  PIN w16_data[113]
    DIRECTION INPUT ;
    USE SIGNAL ;
    PORT
      LAYER M5 ;
        RECT  68.784 0 68.808 0.084 ;
    END
  END w16_data[113]
  PIN w16_data[114]
    DIRECTION INPUT ;
    USE SIGNAL ;
    PORT
      LAYER M5 ;
        RECT  68.88 0 68.904 0.084 ;
    END
  END w16_data[114]
  PIN w16_data[115]
    DIRECTION INPUT ;
    USE SIGNAL ;
    PORT
      LAYER M5 ;
        RECT  68.976 0 69 0.084 ;
    END
  END w16_data[115]
  PIN w16_data[116]
    DIRECTION INPUT ;
    USE SIGNAL ;
    PORT
      LAYER M5 ;
        RECT  69.072 0 69.096 0.084 ;
    END
  END w16_data[116]
  PIN w16_data[117]
    DIRECTION INPUT ;
    USE SIGNAL ;
    PORT
      LAYER M5 ;
        RECT  69.168 0 69.192 0.084 ;
    END
  END w16_data[117]
  PIN w16_data[118]
    DIRECTION INPUT ;
    USE SIGNAL ;
    PORT
      LAYER M5 ;
        RECT  69.264 0 69.288 0.084 ;
    END
  END w16_data[118]
  PIN w16_data[119]
    DIRECTION INPUT ;
    USE SIGNAL ;
    PORT
      LAYER M5 ;
        RECT  69.36 0 69.384 0.084 ;
    END
  END w16_data[119]
  PIN w16_data[11]
    DIRECTION INPUT ;
    USE SIGNAL ;
    PORT
      LAYER M5 ;
        RECT  65.136 0 65.16 0.084 ;
    END
  END w16_data[11]
  PIN w16_data[120]
    DIRECTION INPUT ;
    USE SIGNAL ;
    PORT
      LAYER M5 ;
        RECT  69.456 0 69.48 0.084 ;
    END
  END w16_data[120]
  PIN w16_data[121]
    DIRECTION INPUT ;
    USE SIGNAL ;
    PORT
      LAYER M5 ;
        RECT  69.552 0 69.576 0.084 ;
    END
  END w16_data[121]
  PIN w16_data[122]
    DIRECTION INPUT ;
    USE SIGNAL ;
    PORT
      LAYER M5 ;
        RECT  69.648 0 69.672 0.084 ;
    END
  END w16_data[122]
  PIN w16_data[123]
    DIRECTION INPUT ;
    USE SIGNAL ;
    PORT
      LAYER M5 ;
        RECT  69.744 0 69.768 0.084 ;
    END
  END w16_data[123]
  PIN w16_data[124]
    DIRECTION INPUT ;
    USE SIGNAL ;
    PORT
      LAYER M5 ;
        RECT  69.84 0 69.864 0.084 ;
    END
  END w16_data[124]
  PIN w16_data[125]
    DIRECTION INPUT ;
    USE SIGNAL ;
    PORT
      LAYER M5 ;
        RECT  69.936 0 69.96 0.084 ;
    END
  END w16_data[125]
  PIN w16_data[126]
    DIRECTION INPUT ;
    USE SIGNAL ;
    PORT
      LAYER M5 ;
        RECT  70.032 0 70.056 0.084 ;
    END
  END w16_data[126]
  PIN w16_data[127]
    DIRECTION INPUT ;
    USE SIGNAL ;
    PORT
      LAYER M5 ;
        RECT  70.128 0 70.152 0.084 ;
    END
  END w16_data[127]
  PIN w16_data[128]
    DIRECTION INPUT ;
    USE SIGNAL ;
    PORT
      LAYER M5 ;
        RECT  70.224 0 70.248 0.084 ;
    END
  END w16_data[128]
  PIN w16_data[129]
    DIRECTION INPUT ;
    USE SIGNAL ;
    PORT
      LAYER M5 ;
        RECT  70.32 0 70.344 0.084 ;
    END
  END w16_data[129]
  PIN w16_data[12]
    DIRECTION INPUT ;
    USE SIGNAL ;
    PORT
      LAYER M5 ;
        RECT  65.232 0 65.256 0.084 ;
    END
  END w16_data[12]
  PIN w16_data[130]
    DIRECTION INPUT ;
    USE SIGNAL ;
    PORT
      LAYER M5 ;
        RECT  70.416 0 70.44 0.084 ;
    END
  END w16_data[130]
  PIN w16_data[131]
    DIRECTION INPUT ;
    USE SIGNAL ;
    PORT
      LAYER M5 ;
        RECT  70.512 0 70.536 0.084 ;
    END
  END w16_data[131]
  PIN w16_data[132]
    DIRECTION INPUT ;
    USE SIGNAL ;
    PORT
      LAYER M5 ;
        RECT  173.52 0 173.544 0.084 ;
    END
  END w16_data[132]
  PIN w16_data[133]
    DIRECTION INPUT ;
    USE SIGNAL ;
    PORT
      LAYER M5 ;
        RECT  173.616 0 173.64 0.084 ;
    END
  END w16_data[133]
  PIN w16_data[134]
    DIRECTION INPUT ;
    USE SIGNAL ;
    PORT
      LAYER M5 ;
        RECT  173.712 0 173.736 0.084 ;
    END
  END w16_data[134]
  PIN w16_data[135]
    DIRECTION INPUT ;
    USE SIGNAL ;
    PORT
      LAYER M5 ;
        RECT  173.808 0 173.832 0.084 ;
    END
  END w16_data[135]
  PIN w16_data[136]
    DIRECTION INPUT ;
    USE SIGNAL ;
    PORT
      LAYER M5 ;
        RECT  173.904 0 173.928 0.084 ;
    END
  END w16_data[136]
  PIN w16_data[137]
    DIRECTION INPUT ;
    USE SIGNAL ;
    PORT
      LAYER M5 ;
        RECT  174 0 174.024 0.084 ;
    END
  END w16_data[137]
  PIN w16_data[138]
    DIRECTION INPUT ;
    USE SIGNAL ;
    PORT
      LAYER M5 ;
        RECT  174.096 0 174.12 0.084 ;
    END
  END w16_data[138]
  PIN w16_data[139]
    DIRECTION INPUT ;
    USE SIGNAL ;
    PORT
      LAYER M5 ;
        RECT  174.192 0 174.216 0.084 ;
    END
  END w16_data[139]
  PIN w16_data[13]
    DIRECTION INPUT ;
    USE SIGNAL ;
    PORT
      LAYER M5 ;
        RECT  65.328 0 65.352 0.084 ;
    END
  END w16_data[13]
  PIN w16_data[140]
    DIRECTION INPUT ;
    USE SIGNAL ;
    PORT
      LAYER M5 ;
        RECT  174.288 0 174.312 0.084 ;
    END
  END w16_data[140]
  PIN w16_data[141]
    DIRECTION INPUT ;
    USE SIGNAL ;
    PORT
      LAYER M5 ;
        RECT  174.384 0 174.408 0.084 ;
    END
  END w16_data[141]
  PIN w16_data[142]
    DIRECTION INPUT ;
    USE SIGNAL ;
    PORT
      LAYER M5 ;
        RECT  174.48 0 174.504 0.084 ;
    END
  END w16_data[142]
  PIN w16_data[143]
    DIRECTION INPUT ;
    USE SIGNAL ;
    PORT
      LAYER M5 ;
        RECT  174.576 0 174.6 0.084 ;
    END
  END w16_data[143]
  PIN w16_data[144]
    DIRECTION INPUT ;
    USE SIGNAL ;
    PORT
      LAYER M5 ;
        RECT  174.672 0 174.696 0.084 ;
    END
  END w16_data[144]
  PIN w16_data[145]
    DIRECTION INPUT ;
    USE SIGNAL ;
    PORT
      LAYER M5 ;
        RECT  174.768 0 174.792 0.084 ;
    END
  END w16_data[145]
  PIN w16_data[146]
    DIRECTION INPUT ;
    USE SIGNAL ;
    PORT
      LAYER M5 ;
        RECT  174.864 0 174.888 0.084 ;
    END
  END w16_data[146]
  PIN w16_data[147]
    DIRECTION INPUT ;
    USE SIGNAL ;
    PORT
      LAYER M5 ;
        RECT  174.96 0 174.984 0.084 ;
    END
  END w16_data[147]
  PIN w16_data[148]
    DIRECTION INPUT ;
    USE SIGNAL ;
    PORT
      LAYER M5 ;
        RECT  175.056 0 175.08 0.084 ;
    END
  END w16_data[148]
  PIN w16_data[149]
    DIRECTION INPUT ;
    USE SIGNAL ;
    PORT
      LAYER M5 ;
        RECT  175.152 0 175.176 0.084 ;
    END
  END w16_data[149]
  PIN w16_data[14]
    DIRECTION INPUT ;
    USE SIGNAL ;
    PORT
      LAYER M5 ;
        RECT  65.424 0 65.448 0.084 ;
    END
  END w16_data[14]
  PIN w16_data[150]
    DIRECTION INPUT ;
    USE SIGNAL ;
    PORT
      LAYER M5 ;
        RECT  175.248 0 175.272 0.084 ;
    END
  END w16_data[150]
  PIN w16_data[151]
    DIRECTION INPUT ;
    USE SIGNAL ;
    PORT
      LAYER M5 ;
        RECT  175.344 0 175.368 0.084 ;
    END
  END w16_data[151]
  PIN w16_data[152]
    DIRECTION INPUT ;
    USE SIGNAL ;
    PORT
      LAYER M5 ;
        RECT  175.44 0 175.464 0.084 ;
    END
  END w16_data[152]
  PIN w16_data[153]
    DIRECTION INPUT ;
    USE SIGNAL ;
    PORT
      LAYER M5 ;
        RECT  175.536 0 175.56 0.084 ;
    END
  END w16_data[153]
  PIN w16_data[154]
    DIRECTION INPUT ;
    USE SIGNAL ;
    PORT
      LAYER M5 ;
        RECT  175.632 0 175.656 0.084 ;
    END
  END w16_data[154]
  PIN w16_data[155]
    DIRECTION INPUT ;
    USE SIGNAL ;
    PORT
      LAYER M5 ;
        RECT  175.728 0 175.752 0.084 ;
    END
  END w16_data[155]
  PIN w16_data[156]
    DIRECTION INPUT ;
    USE SIGNAL ;
    PORT
      LAYER M5 ;
        RECT  175.824 0 175.848 0.084 ;
    END
  END w16_data[156]
  PIN w16_data[157]
    DIRECTION INPUT ;
    USE SIGNAL ;
    PORT
      LAYER M5 ;
        RECT  175.92 0 175.944 0.084 ;
    END
  END w16_data[157]
  PIN w16_data[158]
    DIRECTION INPUT ;
    USE SIGNAL ;
    PORT
      LAYER M5 ;
        RECT  176.016 0 176.04 0.084 ;
    END
  END w16_data[158]
  PIN w16_data[159]
    DIRECTION INPUT ;
    USE SIGNAL ;
    PORT
      LAYER M5 ;
        RECT  176.112 0 176.136 0.084 ;
    END
  END w16_data[159]
  PIN w16_data[15]
    DIRECTION INPUT ;
    USE SIGNAL ;
    PORT
      LAYER M5 ;
        RECT  65.52 0 65.544 0.084 ;
    END
  END w16_data[15]
  PIN w16_data[160]
    DIRECTION INPUT ;
    USE SIGNAL ;
    PORT
      LAYER M5 ;
        RECT  176.208 0 176.232 0.084 ;
    END
  END w16_data[160]
  PIN w16_data[161]
    DIRECTION INPUT ;
    USE SIGNAL ;
    PORT
      LAYER M5 ;
        RECT  176.304 0 176.328 0.084 ;
    END
  END w16_data[161]
  PIN w16_data[162]
    DIRECTION INPUT ;
    USE SIGNAL ;
    PORT
      LAYER M5 ;
        RECT  176.4 0 176.424 0.084 ;
    END
  END w16_data[162]
  PIN w16_data[163]
    DIRECTION INPUT ;
    USE SIGNAL ;
    PORT
      LAYER M5 ;
        RECT  176.496 0 176.52 0.084 ;
    END
  END w16_data[163]
  PIN w16_data[164]
    DIRECTION INPUT ;
    USE SIGNAL ;
    PORT
      LAYER M5 ;
        RECT  179.664 0 179.688 0.084 ;
    END
  END w16_data[164]
  PIN w16_data[165]
    DIRECTION INPUT ;
    USE SIGNAL ;
    PORT
      LAYER M5 ;
        RECT  179.76 0 179.784 0.084 ;
    END
  END w16_data[165]
  PIN w16_data[166]
    DIRECTION INPUT ;
    USE SIGNAL ;
    PORT
      LAYER M5 ;
        RECT  179.856 0 179.88 0.084 ;
    END
  END w16_data[166]
  PIN w16_data[167]
    DIRECTION INPUT ;
    USE SIGNAL ;
    PORT
      LAYER M5 ;
        RECT  179.952 0 179.976 0.084 ;
    END
  END w16_data[167]
  PIN w16_data[168]
    DIRECTION INPUT ;
    USE SIGNAL ;
    PORT
      LAYER M5 ;
        RECT  180.048 0 180.072 0.084 ;
    END
  END w16_data[168]
  PIN w16_data[169]
    DIRECTION INPUT ;
    USE SIGNAL ;
    PORT
      LAYER M5 ;
        RECT  180.144 0 180.168 0.084 ;
    END
  END w16_data[169]
  PIN w16_data[16]
    DIRECTION INPUT ;
    USE SIGNAL ;
    PORT
      LAYER M5 ;
        RECT  65.616 0 65.64 0.084 ;
    END
  END w16_data[16]
  PIN w16_data[170]
    DIRECTION INPUT ;
    USE SIGNAL ;
    PORT
      LAYER M5 ;
        RECT  180.24 0 180.264 0.084 ;
    END
  END w16_data[170]
  PIN w16_data[171]
    DIRECTION INPUT ;
    USE SIGNAL ;
    PORT
      LAYER M5 ;
        RECT  180.336 0 180.36 0.084 ;
    END
  END w16_data[171]
  PIN w16_data[172]
    DIRECTION INPUT ;
    USE SIGNAL ;
    PORT
      LAYER M5 ;
        RECT  180.432 0 180.456 0.084 ;
    END
  END w16_data[172]
  PIN w16_data[173]
    DIRECTION INPUT ;
    USE SIGNAL ;
    PORT
      LAYER M5 ;
        RECT  180.528 0 180.552 0.084 ;
    END
  END w16_data[173]
  PIN w16_data[174]
    DIRECTION INPUT ;
    USE SIGNAL ;
    PORT
      LAYER M5 ;
        RECT  180.624 0 180.648 0.084 ;
    END
  END w16_data[174]
  PIN w16_data[175]
    DIRECTION INPUT ;
    USE SIGNAL ;
    PORT
      LAYER M5 ;
        RECT  180.72 0 180.744 0.084 ;
    END
  END w16_data[175]
  PIN w16_data[176]
    DIRECTION INPUT ;
    USE SIGNAL ;
    PORT
      LAYER M5 ;
        RECT  180.816 0 180.84 0.084 ;
    END
  END w16_data[176]
  PIN w16_data[177]
    DIRECTION INPUT ;
    USE SIGNAL ;
    PORT
      LAYER M5 ;
        RECT  180.912 0 180.936 0.084 ;
    END
  END w16_data[177]
  PIN w16_data[178]
    DIRECTION INPUT ;
    USE SIGNAL ;
    PORT
      LAYER M5 ;
        RECT  181.008 0 181.032 0.084 ;
    END
  END w16_data[178]
  PIN w16_data[179]
    DIRECTION INPUT ;
    USE SIGNAL ;
    PORT
      LAYER M5 ;
        RECT  181.104 0 181.128 0.084 ;
    END
  END w16_data[179]
  PIN w16_data[17]
    DIRECTION INPUT ;
    USE SIGNAL ;
    PORT
      LAYER M5 ;
        RECT  65.712 0 65.736 0.084 ;
    END
  END w16_data[17]
  PIN w16_data[180]
    DIRECTION INPUT ;
    USE SIGNAL ;
    PORT
      LAYER M5 ;
        RECT  181.2 0 181.224 0.084 ;
    END
  END w16_data[180]
  PIN w16_data[181]
    DIRECTION INPUT ;
    USE SIGNAL ;
    PORT
      LAYER M5 ;
        RECT  181.296 0 181.32 0.084 ;
    END
  END w16_data[181]
  PIN w16_data[182]
    DIRECTION INPUT ;
    USE SIGNAL ;
    PORT
      LAYER M5 ;
        RECT  181.392 0 181.416 0.084 ;
    END
  END w16_data[182]
  PIN w16_data[183]
    DIRECTION INPUT ;
    USE SIGNAL ;
    PORT
      LAYER M5 ;
        RECT  181.488 0 181.512 0.084 ;
    END
  END w16_data[183]
  PIN w16_data[184]
    DIRECTION INPUT ;
    USE SIGNAL ;
    PORT
      LAYER M5 ;
        RECT  181.584 0 181.608 0.084 ;
    END
  END w16_data[184]
  PIN w16_data[185]
    DIRECTION INPUT ;
    USE SIGNAL ;
    PORT
      LAYER M5 ;
        RECT  181.68 0 181.704 0.084 ;
    END
  END w16_data[185]
  PIN w16_data[186]
    DIRECTION INPUT ;
    USE SIGNAL ;
    PORT
      LAYER M5 ;
        RECT  181.776 0 181.8 0.084 ;
    END
  END w16_data[186]
  PIN w16_data[187]
    DIRECTION INPUT ;
    USE SIGNAL ;
    PORT
      LAYER M5 ;
        RECT  181.872 0 181.896 0.084 ;
    END
  END w16_data[187]
  PIN w16_data[188]
    DIRECTION INPUT ;
    USE SIGNAL ;
    PORT
      LAYER M5 ;
        RECT  181.968 0 181.992 0.084 ;
    END
  END w16_data[188]
  PIN w16_data[189]
    DIRECTION INPUT ;
    USE SIGNAL ;
    PORT
      LAYER M5 ;
        RECT  182.064 0 182.088 0.084 ;
    END
  END w16_data[189]
  PIN w16_data[18]
    DIRECTION INPUT ;
    USE SIGNAL ;
    PORT
      LAYER M5 ;
        RECT  65.808 0 65.832 0.084 ;
    END
  END w16_data[18]
  PIN w16_data[190]
    DIRECTION INPUT ;
    USE SIGNAL ;
    PORT
      LAYER M5 ;
        RECT  182.16 0 182.184 0.084 ;
    END
  END w16_data[190]
  PIN w16_data[191]
    DIRECTION INPUT ;
    USE SIGNAL ;
    PORT
      LAYER M5 ;
        RECT  182.256 0 182.28 0.084 ;
    END
  END w16_data[191]
  PIN w16_data[192]
    DIRECTION INPUT ;
    USE SIGNAL ;
    PORT
      LAYER M5 ;
        RECT  182.352 0 182.376 0.084 ;
    END
  END w16_data[192]
  PIN w16_data[193]
    DIRECTION INPUT ;
    USE SIGNAL ;
    PORT
      LAYER M5 ;
        RECT  182.448 0 182.472 0.084 ;
    END
  END w16_data[193]
  PIN w16_data[194]
    DIRECTION INPUT ;
    USE SIGNAL ;
    PORT
      LAYER M5 ;
        RECT  182.544 0 182.568 0.084 ;
    END
  END w16_data[194]
  PIN w16_data[195]
    DIRECTION INPUT ;
    USE SIGNAL ;
    PORT
      LAYER M5 ;
        RECT  182.64 0 182.664 0.084 ;
    END
  END w16_data[195]
  PIN w16_data[196]
    DIRECTION INPUT ;
    USE SIGNAL ;
    PORT
      LAYER M5 ;
        RECT  198.864 0 198.888 0.084 ;
    END
  END w16_data[196]
  PIN w16_data[197]
    DIRECTION INPUT ;
    USE SIGNAL ;
    PORT
      LAYER M5 ;
        RECT  198.96 0 198.984 0.084 ;
    END
  END w16_data[197]
  PIN w16_data[198]
    DIRECTION INPUT ;
    USE SIGNAL ;
    PORT
      LAYER M5 ;
        RECT  199.056 0 199.08 0.084 ;
    END
  END w16_data[198]
  PIN w16_data[199]
    DIRECTION INPUT ;
    USE SIGNAL ;
    PORT
      LAYER M5 ;
        RECT  199.152 0 199.176 0.084 ;
    END
  END w16_data[199]
  PIN w16_data[19]
    DIRECTION INPUT ;
    USE SIGNAL ;
    PORT
      LAYER M5 ;
        RECT  65.904 0 65.928 0.084 ;
    END
  END w16_data[19]
  PIN w16_data[1]
    DIRECTION INPUT ;
    USE SIGNAL ;
    PORT
      LAYER M5 ;
        RECT  73.392 0 73.416 0.084 ;
    END
  END w16_data[1]
  PIN w16_data[200]
    DIRECTION INPUT ;
    USE SIGNAL ;
    PORT
      LAYER M5 ;
        RECT  199.248 0 199.272 0.084 ;
    END
  END w16_data[200]
  PIN w16_data[201]
    DIRECTION INPUT ;
    USE SIGNAL ;
    PORT
      LAYER M5 ;
        RECT  199.344 0 199.368 0.084 ;
    END
  END w16_data[201]
  PIN w16_data[202]
    DIRECTION INPUT ;
    USE SIGNAL ;
    PORT
      LAYER M5 ;
        RECT  199.44 0 199.464 0.084 ;
    END
  END w16_data[202]
  PIN w16_data[203]
    DIRECTION INPUT ;
    USE SIGNAL ;
    PORT
      LAYER M5 ;
        RECT  199.536 0 199.56 0.084 ;
    END
  END w16_data[203]
  PIN w16_data[204]
    DIRECTION INPUT ;
    USE SIGNAL ;
    PORT
      LAYER M5 ;
        RECT  199.632 0 199.656 0.084 ;
    END
  END w16_data[204]
  PIN w16_data[205]
    DIRECTION INPUT ;
    USE SIGNAL ;
    PORT
      LAYER M5 ;
        RECT  199.728 0 199.752 0.084 ;
    END
  END w16_data[205]
  PIN w16_data[206]
    DIRECTION INPUT ;
    USE SIGNAL ;
    PORT
      LAYER M5 ;
        RECT  199.824 0 199.848 0.084 ;
    END
  END w16_data[206]
  PIN w16_data[207]
    DIRECTION INPUT ;
    USE SIGNAL ;
    PORT
      LAYER M5 ;
        RECT  199.92 0 199.944 0.084 ;
    END
  END w16_data[207]
  PIN w16_data[208]
    DIRECTION INPUT ;
    USE SIGNAL ;
    PORT
      LAYER M5 ;
        RECT  200.016 0 200.04 0.084 ;
    END
  END w16_data[208]
  PIN w16_data[209]
    DIRECTION INPUT ;
    USE SIGNAL ;
    PORT
      LAYER M5 ;
        RECT  200.112 0 200.136 0.084 ;
    END
  END w16_data[209]
  PIN w16_data[20]
    DIRECTION INPUT ;
    USE SIGNAL ;
    PORT
      LAYER M5 ;
        RECT  66 0 66.024 0.084 ;
    END
  END w16_data[20]
  PIN w16_data[210]
    DIRECTION INPUT ;
    USE SIGNAL ;
    PORT
      LAYER M5 ;
        RECT  200.208 0 200.232 0.084 ;
    END
  END w16_data[210]
  PIN w16_data[211]
    DIRECTION INPUT ;
    USE SIGNAL ;
    PORT
      LAYER M5 ;
        RECT  200.304 0 200.328 0.084 ;
    END
  END w16_data[211]
  PIN w16_data[212]
    DIRECTION INPUT ;
    USE SIGNAL ;
    PORT
      LAYER M5 ;
        RECT  200.4 0 200.424 0.084 ;
    END
  END w16_data[212]
  PIN w16_data[213]
    DIRECTION INPUT ;
    USE SIGNAL ;
    PORT
      LAYER M5 ;
        RECT  200.496 0 200.52 0.084 ;
    END
  END w16_data[213]
  PIN w16_data[214]
    DIRECTION INPUT ;
    USE SIGNAL ;
    PORT
      LAYER M5 ;
        RECT  200.592 0 200.616 0.084 ;
    END
  END w16_data[214]
  PIN w16_data[215]
    DIRECTION INPUT ;
    USE SIGNAL ;
    PORT
      LAYER M5 ;
        RECT  200.688 0 200.712 0.084 ;
    END
  END w16_data[215]
  PIN w16_data[216]
    DIRECTION INPUT ;
    USE SIGNAL ;
    PORT
      LAYER M5 ;
        RECT  200.784 0 200.808 0.084 ;
    END
  END w16_data[216]
  PIN w16_data[217]
    DIRECTION INPUT ;
    USE SIGNAL ;
    PORT
      LAYER M5 ;
        RECT  200.88 0 200.904 0.084 ;
    END
  END w16_data[217]
  PIN w16_data[218]
    DIRECTION INPUT ;
    USE SIGNAL ;
    PORT
      LAYER M5 ;
        RECT  200.976 0 201 0.084 ;
    END
  END w16_data[218]
  PIN w16_data[219]
    DIRECTION INPUT ;
    USE SIGNAL ;
    PORT
      LAYER M5 ;
        RECT  201.072 0 201.096 0.084 ;
    END
  END w16_data[219]
  PIN w16_data[21]
    DIRECTION INPUT ;
    USE SIGNAL ;
    PORT
      LAYER M5 ;
        RECT  66.096 0 66.12 0.084 ;
    END
  END w16_data[21]
  PIN w16_data[220]
    DIRECTION INPUT ;
    USE SIGNAL ;
    PORT
      LAYER M5 ;
        RECT  201.168 0 201.192 0.084 ;
    END
  END w16_data[220]
  PIN w16_data[221]
    DIRECTION INPUT ;
    USE SIGNAL ;
    PORT
      LAYER M5 ;
        RECT  201.264 0 201.288 0.084 ;
    END
  END w16_data[221]
  PIN w16_data[222]
    DIRECTION INPUT ;
    USE SIGNAL ;
    PORT
      LAYER M5 ;
        RECT  201.36 0 201.384 0.084 ;
    END
  END w16_data[222]
  PIN w16_data[223]
    DIRECTION INPUT ;
    USE SIGNAL ;
    PORT
      LAYER M5 ;
        RECT  201.456 0 201.48 0.084 ;
    END
  END w16_data[223]
  PIN w16_data[224]
    DIRECTION INPUT ;
    USE SIGNAL ;
    PORT
      LAYER M5 ;
        RECT  201.552 0 201.576 0.084 ;
    END
  END w16_data[224]
  PIN w16_data[225]
    DIRECTION INPUT ;
    USE SIGNAL ;
    PORT
      LAYER M5 ;
        RECT  201.648 0 201.672 0.084 ;
    END
  END w16_data[225]
  PIN w16_data[226]
    DIRECTION INPUT ;
    USE SIGNAL ;
    PORT
      LAYER M5 ;
        RECT  201.744 0 201.768 0.084 ;
    END
  END w16_data[226]
  PIN w16_data[227]
    DIRECTION INPUT ;
    USE SIGNAL ;
    PORT
      LAYER M5 ;
        RECT  201.84 0 201.864 0.084 ;
    END
  END w16_data[227]
  PIN w16_data[228]
    DIRECTION INPUT ;
    USE SIGNAL ;
    PORT
      LAYER M5 ;
        RECT  195.792 0 195.816 0.084 ;
    END
  END w16_data[228]
  PIN w16_data[229]
    DIRECTION INPUT ;
    USE SIGNAL ;
    PORT
      LAYER M5 ;
        RECT  195.888 0 195.912 0.084 ;
    END
  END w16_data[229]
  PIN w16_data[22]
    DIRECTION INPUT ;
    USE SIGNAL ;
    PORT
      LAYER M5 ;
        RECT  66.192 0 66.216 0.084 ;
    END
  END w16_data[22]
  PIN w16_data[230]
    DIRECTION INPUT ;
    USE SIGNAL ;
    PORT
      LAYER M5 ;
        RECT  195.984 0 196.008 0.084 ;
    END
  END w16_data[230]
  PIN w16_data[231]
    DIRECTION INPUT ;
    USE SIGNAL ;
    PORT
      LAYER M5 ;
        RECT  196.08 0 196.104 0.084 ;
    END
  END w16_data[231]
  PIN w16_data[232]
    DIRECTION INPUT ;
    USE SIGNAL ;
    PORT
      LAYER M5 ;
        RECT  196.176 0 196.2 0.084 ;
    END
  END w16_data[232]
  PIN w16_data[233]
    DIRECTION INPUT ;
    USE SIGNAL ;
    PORT
      LAYER M5 ;
        RECT  196.272 0 196.296 0.084 ;
    END
  END w16_data[233]
  PIN w16_data[234]
    DIRECTION INPUT ;
    USE SIGNAL ;
    PORT
      LAYER M5 ;
        RECT  196.368 0 196.392 0.084 ;
    END
  END w16_data[234]
  PIN w16_data[235]
    DIRECTION INPUT ;
    USE SIGNAL ;
    PORT
      LAYER M5 ;
        RECT  196.464 0 196.488 0.084 ;
    END
  END w16_data[235]
  PIN w16_data[236]
    DIRECTION INPUT ;
    USE SIGNAL ;
    PORT
      LAYER M5 ;
        RECT  196.56 0 196.584 0.084 ;
    END
  END w16_data[236]
  PIN w16_data[237]
    DIRECTION INPUT ;
    USE SIGNAL ;
    PORT
      LAYER M5 ;
        RECT  196.656 0 196.68 0.084 ;
    END
  END w16_data[237]
  PIN w16_data[238]
    DIRECTION INPUT ;
    USE SIGNAL ;
    PORT
      LAYER M5 ;
        RECT  196.752 0 196.776 0.084 ;
    END
  END w16_data[238]
  PIN w16_data[239]
    DIRECTION INPUT ;
    USE SIGNAL ;
    PORT
      LAYER M5 ;
        RECT  196.848 0 196.872 0.084 ;
    END
  END w16_data[239]
  PIN w16_data[23]
    DIRECTION INPUT ;
    USE SIGNAL ;
    PORT
      LAYER M5 ;
        RECT  66.288 0 66.312 0.084 ;
    END
  END w16_data[23]
  PIN w16_data[240]
    DIRECTION INPUT ;
    USE SIGNAL ;
    PORT
      LAYER M5 ;
        RECT  196.944 0 196.968 0.084 ;
    END
  END w16_data[240]
  PIN w16_data[241]
    DIRECTION INPUT ;
    USE SIGNAL ;
    PORT
      LAYER M5 ;
        RECT  197.04 0 197.064 0.084 ;
    END
  END w16_data[241]
  PIN w16_data[242]
    DIRECTION INPUT ;
    USE SIGNAL ;
    PORT
      LAYER M5 ;
        RECT  197.136 0 197.16 0.084 ;
    END
  END w16_data[242]
  PIN w16_data[243]
    DIRECTION INPUT ;
    USE SIGNAL ;
    PORT
      LAYER M5 ;
        RECT  197.232 0 197.256 0.084 ;
    END
  END w16_data[243]
  PIN w16_data[244]
    DIRECTION INPUT ;
    USE SIGNAL ;
    PORT
      LAYER M5 ;
        RECT  197.328 0 197.352 0.084 ;
    END
  END w16_data[244]
  PIN w16_data[245]
    DIRECTION INPUT ;
    USE SIGNAL ;
    PORT
      LAYER M5 ;
        RECT  197.424 0 197.448 0.084 ;
    END
  END w16_data[245]
  PIN w16_data[246]
    DIRECTION INPUT ;
    USE SIGNAL ;
    PORT
      LAYER M5 ;
        RECT  197.52 0 197.544 0.084 ;
    END
  END w16_data[246]
  PIN w16_data[247]
    DIRECTION INPUT ;
    USE SIGNAL ;
    PORT
      LAYER M5 ;
        RECT  197.616 0 197.64 0.084 ;
    END
  END w16_data[247]
  PIN w16_data[248]
    DIRECTION INPUT ;
    USE SIGNAL ;
    PORT
      LAYER M5 ;
        RECT  197.712 0 197.736 0.084 ;
    END
  END w16_data[248]
  PIN w16_data[249]
    DIRECTION INPUT ;
    USE SIGNAL ;
    PORT
      LAYER M5 ;
        RECT  197.808 0 197.832 0.084 ;
    END
  END w16_data[249]
  PIN w16_data[24]
    DIRECTION INPUT ;
    USE SIGNAL ;
    PORT
      LAYER M5 ;
        RECT  66.384 0 66.408 0.084 ;
    END
  END w16_data[24]
  PIN w16_data[250]
    DIRECTION INPUT ;
    USE SIGNAL ;
    PORT
      LAYER M5 ;
        RECT  197.904 0 197.928 0.084 ;
    END
  END w16_data[250]
  PIN w16_data[251]
    DIRECTION INPUT ;
    USE SIGNAL ;
    PORT
      LAYER M5 ;
        RECT  198 0 198.024 0.084 ;
    END
  END w16_data[251]
  PIN w16_data[252]
    DIRECTION INPUT ;
    USE SIGNAL ;
    PORT
      LAYER M5 ;
        RECT  198.096 0 198.12 0.084 ;
    END
  END w16_data[252]
  PIN w16_data[253]
    DIRECTION INPUT ;
    USE SIGNAL ;
    PORT
      LAYER M5 ;
        RECT  198.192 0 198.216 0.084 ;
    END
  END w16_data[253]
  PIN w16_data[254]
    DIRECTION INPUT ;
    USE SIGNAL ;
    PORT
      LAYER M5 ;
        RECT  198.288 0 198.312 0.084 ;
    END
  END w16_data[254]
  PIN w16_data[255]
    DIRECTION INPUT ;
    USE SIGNAL ;
    PORT
      LAYER M5 ;
        RECT  198.384 0 198.408 0.084 ;
    END
  END w16_data[255]
  PIN w16_data[256]
    DIRECTION INPUT ;
    USE SIGNAL ;
    PORT
      LAYER M5 ;
        RECT  198.48 0 198.504 0.084 ;
    END
  END w16_data[256]
  PIN w16_data[257]
    DIRECTION INPUT ;
    USE SIGNAL ;
    PORT
      LAYER M5 ;
        RECT  198.576 0 198.6 0.084 ;
    END
  END w16_data[257]
  PIN w16_data[258]
    DIRECTION INPUT ;
    USE SIGNAL ;
    PORT
      LAYER M5 ;
        RECT  198.672 0 198.696 0.084 ;
    END
  END w16_data[258]
  PIN w16_data[259]
    DIRECTION INPUT ;
    USE SIGNAL ;
    PORT
      LAYER M5 ;
        RECT  198.768 0 198.792 0.084 ;
    END
  END w16_data[259]
  PIN w16_data[25]
    DIRECTION INPUT ;
    USE SIGNAL ;
    PORT
      LAYER M5 ;
        RECT  66.48 0 66.504 0.084 ;
    END
  END w16_data[25]
  PIN w16_data[260]
    DIRECTION INPUT ;
    USE SIGNAL ;
    PORT
      LAYER M5 ;
        RECT  45.264 0 45.288 0.084 ;
    END
  END w16_data[260]
  PIN w16_data[261]
    DIRECTION INPUT ;
    USE SIGNAL ;
    PORT
      LAYER M5 ;
        RECT  45.36 0 45.384 0.084 ;
    END
  END w16_data[261]
  PIN w16_data[262]
    DIRECTION INPUT ;
    USE SIGNAL ;
    PORT
      LAYER M5 ;
        RECT  45.456 0 45.48 0.084 ;
    END
  END w16_data[262]
  PIN w16_data[263]
    DIRECTION INPUT ;
    USE SIGNAL ;
    PORT
      LAYER M5 ;
        RECT  45.552 0 45.576 0.084 ;
    END
  END w16_data[263]
  PIN w16_data[264]
    DIRECTION INPUT ;
    USE SIGNAL ;
    PORT
      LAYER M5 ;
        RECT  45.648 0 45.672 0.084 ;
    END
  END w16_data[264]
  PIN w16_data[265]
    DIRECTION INPUT ;
    USE SIGNAL ;
    PORT
      LAYER M5 ;
        RECT  45.744 0 45.768 0.084 ;
    END
  END w16_data[265]
  PIN w16_data[266]
    DIRECTION INPUT ;
    USE SIGNAL ;
    PORT
      LAYER M5 ;
        RECT  45.84 0 45.864 0.084 ;
    END
  END w16_data[266]
  PIN w16_data[267]
    DIRECTION INPUT ;
    USE SIGNAL ;
    PORT
      LAYER M5 ;
        RECT  45.936 0 45.96 0.084 ;
    END
  END w16_data[267]
  PIN w16_data[268]
    DIRECTION INPUT ;
    USE SIGNAL ;
    PORT
      LAYER M5 ;
        RECT  46.032 0 46.056 0.084 ;
    END
  END w16_data[268]
  PIN w16_data[269]
    DIRECTION INPUT ;
    USE SIGNAL ;
    PORT
      LAYER M5 ;
        RECT  46.128 0 46.152 0.084 ;
    END
  END w16_data[269]
  PIN w16_data[26]
    DIRECTION INPUT ;
    USE SIGNAL ;
    PORT
      LAYER M5 ;
        RECT  66.576 0 66.6 0.084 ;
    END
  END w16_data[26]
  PIN w16_data[270]
    DIRECTION INPUT ;
    USE SIGNAL ;
    PORT
      LAYER M5 ;
        RECT  46.224 0 46.248 0.084 ;
    END
  END w16_data[270]
  PIN w16_data[271]
    DIRECTION INPUT ;
    USE SIGNAL ;
    PORT
      LAYER M5 ;
        RECT  46.32 0 46.344 0.084 ;
    END
  END w16_data[271]
  PIN w16_data[272]
    DIRECTION INPUT ;
    USE SIGNAL ;
    PORT
      LAYER M5 ;
        RECT  46.416 0 46.44 0.084 ;
    END
  END w16_data[272]
  PIN w16_data[273]
    DIRECTION INPUT ;
    USE SIGNAL ;
    PORT
      LAYER M5 ;
        RECT  46.512 0 46.536 0.084 ;
    END
  END w16_data[273]
  PIN w16_data[274]
    DIRECTION INPUT ;
    USE SIGNAL ;
    PORT
      LAYER M5 ;
        RECT  46.608 0 46.632 0.084 ;
    END
  END w16_data[274]
  PIN w16_data[275]
    DIRECTION INPUT ;
    USE SIGNAL ;
    PORT
      LAYER M5 ;
        RECT  46.704 0 46.728 0.084 ;
    END
  END w16_data[275]
  PIN w16_data[276]
    DIRECTION INPUT ;
    USE SIGNAL ;
    PORT
      LAYER M5 ;
        RECT  46.8 0 46.824 0.084 ;
    END
  END w16_data[276]
  PIN w16_data[277]
    DIRECTION INPUT ;
    USE SIGNAL ;
    PORT
      LAYER M5 ;
        RECT  46.896 0 46.92 0.084 ;
    END
  END w16_data[277]
  PIN w16_data[278]
    DIRECTION INPUT ;
    USE SIGNAL ;
    PORT
      LAYER M5 ;
        RECT  46.992 0 47.016 0.084 ;
    END
  END w16_data[278]
  PIN w16_data[279]
    DIRECTION INPUT ;
    USE SIGNAL ;
    PORT
      LAYER M5 ;
        RECT  47.088 0 47.112 0.084 ;
    END
  END w16_data[279]
  PIN w16_data[27]
    DIRECTION INPUT ;
    USE SIGNAL ;
    PORT
      LAYER M5 ;
        RECT  66.672 0 66.696 0.084 ;
    END
  END w16_data[27]
  PIN w16_data[280]
    DIRECTION INPUT ;
    USE SIGNAL ;
    PORT
      LAYER M5 ;
        RECT  47.184 0 47.208 0.084 ;
    END
  END w16_data[280]
  PIN w16_data[281]
    DIRECTION INPUT ;
    USE SIGNAL ;
    PORT
      LAYER M5 ;
        RECT  47.28 0 47.304 0.084 ;
    END
  END w16_data[281]
  PIN w16_data[282]
    DIRECTION INPUT ;
    USE SIGNAL ;
    PORT
      LAYER M5 ;
        RECT  47.376 0 47.4 0.084 ;
    END
  END w16_data[282]
  PIN w16_data[283]
    DIRECTION INPUT ;
    USE SIGNAL ;
    PORT
      LAYER M5 ;
        RECT  47.472 0 47.496 0.084 ;
    END
  END w16_data[283]
  PIN w16_data[284]
    DIRECTION INPUT ;
    USE SIGNAL ;
    PORT
      LAYER M5 ;
        RECT  47.568 0 47.592 0.084 ;
    END
  END w16_data[284]
  PIN w16_data[285]
    DIRECTION INPUT ;
    USE SIGNAL ;
    PORT
      LAYER M5 ;
        RECT  47.664 0 47.688 0.084 ;
    END
  END w16_data[285]
  PIN w16_data[286]
    DIRECTION INPUT ;
    USE SIGNAL ;
    PORT
      LAYER M5 ;
        RECT  47.76 0 47.784 0.084 ;
    END
  END w16_data[286]
  PIN w16_data[287]
    DIRECTION INPUT ;
    USE SIGNAL ;
    PORT
      LAYER M5 ;
        RECT  47.856 0 47.88 0.084 ;
    END
  END w16_data[287]
  PIN w16_data[288]
    DIRECTION INPUT ;
    USE SIGNAL ;
    PORT
      LAYER M5 ;
        RECT  47.952 0 47.976 0.084 ;
    END
  END w16_data[288]
  PIN w16_data[289]
    DIRECTION INPUT ;
    USE SIGNAL ;
    PORT
      LAYER M5 ;
        RECT  48.048 0 48.072 0.084 ;
    END
  END w16_data[289]
  PIN w16_data[28]
    DIRECTION INPUT ;
    USE SIGNAL ;
    PORT
      LAYER M5 ;
        RECT  66.768 0 66.792 0.084 ;
    END
  END w16_data[28]
  PIN w16_data[290]
    DIRECTION INPUT ;
    USE SIGNAL ;
    PORT
      LAYER M5 ;
        RECT  48.144 0 48.168 0.084 ;
    END
  END w16_data[290]
  PIN w16_data[291]
    DIRECTION INPUT ;
    USE SIGNAL ;
    PORT
      LAYER M5 ;
        RECT  48.24 0 48.264 0.084 ;
    END
  END w16_data[291]
  PIN w16_data[292]
    DIRECTION INPUT ;
    USE SIGNAL ;
    PORT
      LAYER M5 ;
        RECT  48.336 0 48.36 0.084 ;
    END
  END w16_data[292]
  PIN w16_data[293]
    DIRECTION INPUT ;
    USE SIGNAL ;
    PORT
      LAYER M5 ;
        RECT  48.432 0 48.456 0.084 ;
    END
  END w16_data[293]
  PIN w16_data[294]
    DIRECTION INPUT ;
    USE SIGNAL ;
    PORT
      LAYER M5 ;
        RECT  48.528 0 48.552 0.084 ;
    END
  END w16_data[294]
  PIN w16_data[295]
    DIRECTION INPUT ;
    USE SIGNAL ;
    PORT
      LAYER M5 ;
        RECT  48.624 0 48.648 0.084 ;
    END
  END w16_data[295]
  PIN w16_data[296]
    DIRECTION INPUT ;
    USE SIGNAL ;
    PORT
      LAYER M5 ;
        RECT  48.72 0 48.744 0.084 ;
    END
  END w16_data[296]
  PIN w16_data[297]
    DIRECTION INPUT ;
    USE SIGNAL ;
    PORT
      LAYER M5 ;
        RECT  48.816 0 48.84 0.084 ;
    END
  END w16_data[297]
  PIN w16_data[298]
    DIRECTION INPUT ;
    USE SIGNAL ;
    PORT
      LAYER M5 ;
        RECT  48.912 0 48.936 0.084 ;
    END
  END w16_data[298]
  PIN w16_data[299]
    DIRECTION INPUT ;
    USE SIGNAL ;
    PORT
      LAYER M5 ;
        RECT  49.008 0 49.032 0.084 ;
    END
  END w16_data[299]
  PIN w16_data[29]
    DIRECTION INPUT ;
    USE SIGNAL ;
    PORT
      LAYER M5 ;
        RECT  66.864 0 66.888 0.084 ;
    END
  END w16_data[29]
  PIN w16_data[2]
    DIRECTION INPUT ;
    USE SIGNAL ;
    PORT
      LAYER M5 ;
        RECT  73.488 0 73.512 0.084 ;
    END
  END w16_data[2]
  PIN w16_data[300]
    DIRECTION INPUT ;
    USE SIGNAL ;
    PORT
      LAYER M5 ;
        RECT  49.104 0 49.128 0.084 ;
    END
  END w16_data[300]
  PIN w16_data[301]
    DIRECTION INPUT ;
    USE SIGNAL ;
    PORT
      LAYER M5 ;
        RECT  49.2 0 49.224 0.084 ;
    END
  END w16_data[301]
  PIN w16_data[302]
    DIRECTION INPUT ;
    USE SIGNAL ;
    PORT
      LAYER M5 ;
        RECT  49.296 0 49.32 0.084 ;
    END
  END w16_data[302]
  PIN w16_data[303]
    DIRECTION INPUT ;
    USE SIGNAL ;
    PORT
      LAYER M5 ;
        RECT  49.392 0 49.416 0.084 ;
    END
  END w16_data[303]
  PIN w16_data[304]
    DIRECTION INPUT ;
    USE SIGNAL ;
    PORT
      LAYER M5 ;
        RECT  49.488 0 49.512 0.084 ;
    END
  END w16_data[304]
  PIN w16_data[305]
    DIRECTION INPUT ;
    USE SIGNAL ;
    PORT
      LAYER M5 ;
        RECT  49.584 0 49.608 0.084 ;
    END
  END w16_data[305]
  PIN w16_data[306]
    DIRECTION INPUT ;
    USE SIGNAL ;
    PORT
      LAYER M5 ;
        RECT  49.68 0 49.704 0.084 ;
    END
  END w16_data[306]
  PIN w16_data[307]
    DIRECTION INPUT ;
    USE SIGNAL ;
    PORT
      LAYER M5 ;
        RECT  49.776 0 49.8 0.084 ;
    END
  END w16_data[307]
  PIN w16_data[308]
    DIRECTION INPUT ;
    USE SIGNAL ;
    PORT
      LAYER M5 ;
        RECT  49.872 0 49.896 0.084 ;
    END
  END w16_data[308]
  PIN w16_data[309]
    DIRECTION INPUT ;
    USE SIGNAL ;
    PORT
      LAYER M5 ;
        RECT  49.968 0 49.992 0.084 ;
    END
  END w16_data[309]
  PIN w16_data[30]
    DIRECTION INPUT ;
    USE SIGNAL ;
    PORT
      LAYER M5 ;
        RECT  66.96 0 66.984 0.084 ;
    END
  END w16_data[30]
  PIN w16_data[310]
    DIRECTION INPUT ;
    USE SIGNAL ;
    PORT
      LAYER M5 ;
        RECT  50.064 0 50.088 0.084 ;
    END
  END w16_data[310]
  PIN w16_data[311]
    DIRECTION INPUT ;
    USE SIGNAL ;
    PORT
      LAYER M5 ;
        RECT  50.16 0 50.184 0.084 ;
    END
  END w16_data[311]
  PIN w16_data[312]
    DIRECTION INPUT ;
    USE SIGNAL ;
    PORT
      LAYER M5 ;
        RECT  50.256 0 50.28 0.084 ;
    END
  END w16_data[312]
  PIN w16_data[313]
    DIRECTION INPUT ;
    USE SIGNAL ;
    PORT
      LAYER M5 ;
        RECT  50.352 0 50.376 0.084 ;
    END
  END w16_data[313]
  PIN w16_data[314]
    DIRECTION INPUT ;
    USE SIGNAL ;
    PORT
      LAYER M5 ;
        RECT  50.448 0 50.472 0.084 ;
    END
  END w16_data[314]
  PIN w16_data[315]
    DIRECTION INPUT ;
    USE SIGNAL ;
    PORT
      LAYER M5 ;
        RECT  50.544 0 50.568 0.084 ;
    END
  END w16_data[315]
  PIN w16_data[316]
    DIRECTION INPUT ;
    USE SIGNAL ;
    PORT
      LAYER M5 ;
        RECT  50.64 0 50.664 0.084 ;
    END
  END w16_data[316]
  PIN w16_data[317]
    DIRECTION INPUT ;
    USE SIGNAL ;
    PORT
      LAYER M5 ;
        RECT  50.736 0 50.76 0.084 ;
    END
  END w16_data[317]
  PIN w16_data[318]
    DIRECTION INPUT ;
    USE SIGNAL ;
    PORT
      LAYER M5 ;
        RECT  50.832 0 50.856 0.084 ;
    END
  END w16_data[318]
  PIN w16_data[319]
    DIRECTION INPUT ;
    USE SIGNAL ;
    PORT
      LAYER M5 ;
        RECT  50.928 0 50.952 0.084 ;
    END
  END w16_data[319]
  PIN w16_data[31]
    DIRECTION INPUT ;
    USE SIGNAL ;
    PORT
      LAYER M5 ;
        RECT  67.056 0 67.08 0.084 ;
    END
  END w16_data[31]
  PIN w16_data[320]
    DIRECTION INPUT ;
    USE SIGNAL ;
    PORT
      LAYER M5 ;
        RECT  51.024 0 51.048 0.084 ;
    END
  END w16_data[320]
  PIN w16_data[321]
    DIRECTION INPUT ;
    USE SIGNAL ;
    PORT
      LAYER M5 ;
        RECT  51.12 0 51.144 0.084 ;
    END
  END w16_data[321]
  PIN w16_data[322]
    DIRECTION INPUT ;
    USE SIGNAL ;
    PORT
      LAYER M5 ;
        RECT  51.216 0 51.24 0.084 ;
    END
  END w16_data[322]
  PIN w16_data[323]
    DIRECTION INPUT ;
    USE SIGNAL ;
    PORT
      LAYER M5 ;
        RECT  51.312 0 51.336 0.084 ;
    END
  END w16_data[323]
  PIN w16_data[324]
    DIRECTION INPUT ;
    USE SIGNAL ;
    PORT
      LAYER M5 ;
        RECT  51.408 0 51.432 0.084 ;
    END
  END w16_data[324]
  PIN w16_data[325]
    DIRECTION INPUT ;
    USE SIGNAL ;
    PORT
      LAYER M5 ;
        RECT  51.504 0 51.528 0.084 ;
    END
  END w16_data[325]
  PIN w16_data[326]
    DIRECTION INPUT ;
    USE SIGNAL ;
    PORT
      LAYER M5 ;
        RECT  51.6 0 51.624 0.084 ;
    END
  END w16_data[326]
  PIN w16_data[327]
    DIRECTION INPUT ;
    USE SIGNAL ;
    PORT
      LAYER M5 ;
        RECT  51.696 0 51.72 0.084 ;
    END
  END w16_data[327]
  PIN w16_data[328]
    DIRECTION INPUT ;
    USE SIGNAL ;
    PORT
      LAYER M5 ;
        RECT  51.792 0 51.816 0.084 ;
    END
  END w16_data[328]
  PIN w16_data[329]
    DIRECTION INPUT ;
    USE SIGNAL ;
    PORT
      LAYER M5 ;
        RECT  51.888 0 51.912 0.084 ;
    END
  END w16_data[329]
  PIN w16_data[32]
    DIRECTION INPUT ;
    USE SIGNAL ;
    PORT
      LAYER M5 ;
        RECT  67.152 0 67.176 0.084 ;
    END
  END w16_data[32]
  PIN w16_data[330]
    DIRECTION INPUT ;
    USE SIGNAL ;
    PORT
      LAYER M5 ;
        RECT  51.984 0 52.008 0.084 ;
    END
  END w16_data[330]
  PIN w16_data[331]
    DIRECTION INPUT ;
    USE SIGNAL ;
    PORT
      LAYER M5 ;
        RECT  52.08 0 52.104 0.084 ;
    END
  END w16_data[331]
  PIN w16_data[332]
    DIRECTION INPUT ;
    USE SIGNAL ;
    PORT
      LAYER M5 ;
        RECT  52.176 0 52.2 0.084 ;
    END
  END w16_data[332]
  PIN w16_data[333]
    DIRECTION INPUT ;
    USE SIGNAL ;
    PORT
      LAYER M5 ;
        RECT  52.272 0 52.296 0.084 ;
    END
  END w16_data[333]
  PIN w16_data[334]
    DIRECTION INPUT ;
    USE SIGNAL ;
    PORT
      LAYER M5 ;
        RECT  52.368 0 52.392 0.084 ;
    END
  END w16_data[334]
  PIN w16_data[335]
    DIRECTION INPUT ;
    USE SIGNAL ;
    PORT
      LAYER M5 ;
        RECT  52.464 0 52.488 0.084 ;
    END
  END w16_data[335]
  PIN w16_data[336]
    DIRECTION INPUT ;
    USE SIGNAL ;
    PORT
      LAYER M5 ;
        RECT  52.56 0 52.584 0.084 ;
    END
  END w16_data[336]
  PIN w16_data[337]
    DIRECTION INPUT ;
    USE SIGNAL ;
    PORT
      LAYER M5 ;
        RECT  52.656 0 52.68 0.084 ;
    END
  END w16_data[337]
  PIN w16_data[338]
    DIRECTION INPUT ;
    USE SIGNAL ;
    PORT
      LAYER M5 ;
        RECT  52.752 0 52.776 0.084 ;
    END
  END w16_data[338]
  PIN w16_data[339]
    DIRECTION INPUT ;
    USE SIGNAL ;
    PORT
      LAYER M5 ;
        RECT  52.848 0 52.872 0.084 ;
    END
  END w16_data[339]
  PIN w16_data[33]
    DIRECTION INPUT ;
    USE SIGNAL ;
    PORT
      LAYER M5 ;
        RECT  67.248 0 67.272 0.084 ;
    END
  END w16_data[33]
  PIN w16_data[340]
    DIRECTION INPUT ;
    USE SIGNAL ;
    PORT
      LAYER M5 ;
        RECT  52.944 0 52.968 0.084 ;
    END
  END w16_data[340]
  PIN w16_data[341]
    DIRECTION INPUT ;
    USE SIGNAL ;
    PORT
      LAYER M5 ;
        RECT  53.04 0 53.064 0.084 ;
    END
  END w16_data[341]
  PIN w16_data[342]
    DIRECTION INPUT ;
    USE SIGNAL ;
    PORT
      LAYER M5 ;
        RECT  53.136 0 53.16 0.084 ;
    END
  END w16_data[342]
  PIN w16_data[343]
    DIRECTION INPUT ;
    USE SIGNAL ;
    PORT
      LAYER M5 ;
        RECT  53.232 0 53.256 0.084 ;
    END
  END w16_data[343]
  PIN w16_data[344]
    DIRECTION INPUT ;
    USE SIGNAL ;
    PORT
      LAYER M5 ;
        RECT  53.328 0 53.352 0.084 ;
    END
  END w16_data[344]
  PIN w16_data[345]
    DIRECTION INPUT ;
    USE SIGNAL ;
    PORT
      LAYER M5 ;
        RECT  53.424 0 53.448 0.084 ;
    END
  END w16_data[345]
  PIN w16_data[346]
    DIRECTION INPUT ;
    USE SIGNAL ;
    PORT
      LAYER M5 ;
        RECT  53.52 0 53.544 0.084 ;
    END
  END w16_data[346]
  PIN w16_data[347]
    DIRECTION INPUT ;
    USE SIGNAL ;
    PORT
      LAYER M5 ;
        RECT  53.616 0 53.64 0.084 ;
    END
  END w16_data[347]
  PIN w16_data[348]
    DIRECTION INPUT ;
    USE SIGNAL ;
    PORT
      LAYER M5 ;
        RECT  53.712 0 53.736 0.084 ;
    END
  END w16_data[348]
  PIN w16_data[349]
    DIRECTION INPUT ;
    USE SIGNAL ;
    PORT
      LAYER M5 ;
        RECT  53.808 0 53.832 0.084 ;
    END
  END w16_data[349]
  PIN w16_data[34]
    DIRECTION INPUT ;
    USE SIGNAL ;
    PORT
      LAYER M5 ;
        RECT  67.344 0 67.368 0.084 ;
    END
  END w16_data[34]
  PIN w16_data[350]
    DIRECTION INPUT ;
    USE SIGNAL ;
    PORT
      LAYER M5 ;
        RECT  53.904 0 53.928 0.084 ;
    END
  END w16_data[350]
  PIN w16_data[351]
    DIRECTION INPUT ;
    USE SIGNAL ;
    PORT
      LAYER M5 ;
        RECT  54 0 54.024 0.084 ;
    END
  END w16_data[351]
  PIN w16_data[352]
    DIRECTION INPUT ;
    USE SIGNAL ;
    PORT
      LAYER M5 ;
        RECT  54.096 0 54.12 0.084 ;
    END
  END w16_data[352]
  PIN w16_data[353]
    DIRECTION INPUT ;
    USE SIGNAL ;
    PORT
      LAYER M5 ;
        RECT  54.192 0 54.216 0.084 ;
    END
  END w16_data[353]
  PIN w16_data[354]
    DIRECTION INPUT ;
    USE SIGNAL ;
    PORT
      LAYER M5 ;
        RECT  54.288 0 54.312 0.084 ;
    END
  END w16_data[354]
  PIN w16_data[355]
    DIRECTION INPUT ;
    USE SIGNAL ;
    PORT
      LAYER M5 ;
        RECT  54.384 0 54.408 0.084 ;
    END
  END w16_data[355]
  PIN w16_data[356]
    DIRECTION INPUT ;
    USE SIGNAL ;
    PORT
      LAYER M5 ;
        RECT  54.48 0 54.504 0.084 ;
    END
  END w16_data[356]
  PIN w16_data[357]
    DIRECTION INPUT ;
    USE SIGNAL ;
    PORT
      LAYER M5 ;
        RECT  54.576 0 54.6 0.084 ;
    END
  END w16_data[357]
  PIN w16_data[358]
    DIRECTION INPUT ;
    USE SIGNAL ;
    PORT
      LAYER M5 ;
        RECT  54.672 0 54.696 0.084 ;
    END
  END w16_data[358]
  PIN w16_data[359]
    DIRECTION INPUT ;
    USE SIGNAL ;
    PORT
      LAYER M5 ;
        RECT  54.768 0 54.792 0.084 ;
    END
  END w16_data[359]
  PIN w16_data[35]
    DIRECTION INPUT ;
    USE SIGNAL ;
    PORT
      LAYER M5 ;
        RECT  67.44 0 67.464 0.084 ;
    END
  END w16_data[35]
  PIN w16_data[360]
    DIRECTION INPUT ;
    USE SIGNAL ;
    PORT
      LAYER M5 ;
        RECT  54.864 0 54.888 0.084 ;
    END
  END w16_data[360]
  PIN w16_data[361]
    DIRECTION INPUT ;
    USE SIGNAL ;
    PORT
      LAYER M5 ;
        RECT  54.96 0 54.984 0.084 ;
    END
  END w16_data[361]
  PIN w16_data[362]
    DIRECTION INPUT ;
    USE SIGNAL ;
    PORT
      LAYER M5 ;
        RECT  55.056 0 55.08 0.084 ;
    END
  END w16_data[362]
  PIN w16_data[363]
    DIRECTION INPUT ;
    USE SIGNAL ;
    PORT
      LAYER M5 ;
        RECT  55.152 0 55.176 0.084 ;
    END
  END w16_data[363]
  PIN w16_data[364]
    DIRECTION INPUT ;
    USE SIGNAL ;
    PORT
      LAYER M5 ;
        RECT  55.248 0 55.272 0.084 ;
    END
  END w16_data[364]
  PIN w16_data[365]
    DIRECTION INPUT ;
    USE SIGNAL ;
    PORT
      LAYER M5 ;
        RECT  55.344 0 55.368 0.084 ;
    END
  END w16_data[365]
  PIN w16_data[366]
    DIRECTION INPUT ;
    USE SIGNAL ;
    PORT
      LAYER M5 ;
        RECT  55.44 0 55.464 0.084 ;
    END
  END w16_data[366]
  PIN w16_data[367]
    DIRECTION INPUT ;
    USE SIGNAL ;
    PORT
      LAYER M5 ;
        RECT  55.536 0 55.56 0.084 ;
    END
  END w16_data[367]
  PIN w16_data[368]
    DIRECTION INPUT ;
    USE SIGNAL ;
    PORT
      LAYER M5 ;
        RECT  55.632 0 55.656 0.084 ;
    END
  END w16_data[368]
  PIN w16_data[369]
    DIRECTION INPUT ;
    USE SIGNAL ;
    PORT
      LAYER M5 ;
        RECT  55.728 0 55.752 0.084 ;
    END
  END w16_data[369]
  PIN w16_data[36]
    DIRECTION INPUT ;
    USE SIGNAL ;
    PORT
      LAYER M5 ;
        RECT  61.392 0 61.416 0.084 ;
    END
  END w16_data[36]
  PIN w16_data[370]
    DIRECTION INPUT ;
    USE SIGNAL ;
    PORT
      LAYER M5 ;
        RECT  55.824 0 55.848 0.084 ;
    END
  END w16_data[370]
  PIN w16_data[371]
    DIRECTION INPUT ;
    USE SIGNAL ;
    PORT
      LAYER M5 ;
        RECT  55.92 0 55.944 0.084 ;
    END
  END w16_data[371]
  PIN w16_data[372]
    DIRECTION INPUT ;
    USE SIGNAL ;
    PORT
      LAYER M5 ;
        RECT  56.016 0 56.04 0.084 ;
    END
  END w16_data[372]
  PIN w16_data[373]
    DIRECTION INPUT ;
    USE SIGNAL ;
    PORT
      LAYER M5 ;
        RECT  56.112 0 56.136 0.084 ;
    END
  END w16_data[373]
  PIN w16_data[374]
    DIRECTION INPUT ;
    USE SIGNAL ;
    PORT
      LAYER M5 ;
        RECT  56.208 0 56.232 0.084 ;
    END
  END w16_data[374]
  PIN w16_data[375]
    DIRECTION INPUT ;
    USE SIGNAL ;
    PORT
      LAYER M5 ;
        RECT  56.304 0 56.328 0.084 ;
    END
  END w16_data[375]
  PIN w16_data[376]
    DIRECTION INPUT ;
    USE SIGNAL ;
    PORT
      LAYER M5 ;
        RECT  56.4 0 56.424 0.084 ;
    END
  END w16_data[376]
  PIN w16_data[377]
    DIRECTION INPUT ;
    USE SIGNAL ;
    PORT
      LAYER M5 ;
        RECT  56.496 0 56.52 0.084 ;
    END
  END w16_data[377]
  PIN w16_data[378]
    DIRECTION INPUT ;
    USE SIGNAL ;
    PORT
      LAYER M5 ;
        RECT  56.592 0 56.616 0.084 ;
    END
  END w16_data[378]
  PIN w16_data[379]
    DIRECTION INPUT ;
    USE SIGNAL ;
    PORT
      LAYER M5 ;
        RECT  56.688 0 56.712 0.084 ;
    END
  END w16_data[379]
  PIN w16_data[37]
    DIRECTION INPUT ;
    USE SIGNAL ;
    PORT
      LAYER M5 ;
        RECT  61.488 0 61.512 0.084 ;
    END
  END w16_data[37]
  PIN w16_data[380]
    DIRECTION INPUT ;
    USE SIGNAL ;
    PORT
      LAYER M5 ;
        RECT  56.784 0 56.808 0.084 ;
    END
  END w16_data[380]
  PIN w16_data[381]
    DIRECTION INPUT ;
    USE SIGNAL ;
    PORT
      LAYER M5 ;
        RECT  56.88 0 56.904 0.084 ;
    END
  END w16_data[381]
  PIN w16_data[382]
    DIRECTION INPUT ;
    USE SIGNAL ;
    PORT
      LAYER M5 ;
        RECT  56.976 0 57 0.084 ;
    END
  END w16_data[382]
  PIN w16_data[383]
    DIRECTION INPUT ;
    USE SIGNAL ;
    PORT
      LAYER M5 ;
        RECT  57.072 0 57.096 0.084 ;
    END
  END w16_data[383]
  PIN w16_data[384]
    DIRECTION INPUT ;
    USE SIGNAL ;
    PORT
      LAYER M5 ;
        RECT  57.168 0 57.192 0.084 ;
    END
  END w16_data[384]
  PIN w16_data[385]
    DIRECTION INPUT ;
    USE SIGNAL ;
    PORT
      LAYER M5 ;
        RECT  57.264 0 57.288 0.084 ;
    END
  END w16_data[385]
  PIN w16_data[386]
    DIRECTION INPUT ;
    USE SIGNAL ;
    PORT
      LAYER M5 ;
        RECT  57.36 0 57.384 0.084 ;
    END
  END w16_data[386]
  PIN w16_data[387]
    DIRECTION INPUT ;
    USE SIGNAL ;
    PORT
      LAYER M5 ;
        RECT  57.456 0 57.48 0.084 ;
    END
  END w16_data[387]
  PIN w16_data[388]
    DIRECTION INPUT ;
    USE SIGNAL ;
    PORT
      LAYER M5 ;
        RECT  176.592 0 176.616 0.084 ;
    END
  END w16_data[388]
  PIN w16_data[389]
    DIRECTION INPUT ;
    USE SIGNAL ;
    PORT
      LAYER M5 ;
        RECT  176.688 0 176.712 0.084 ;
    END
  END w16_data[389]
  PIN w16_data[38]
    DIRECTION INPUT ;
    USE SIGNAL ;
    PORT
      LAYER M5 ;
        RECT  61.584 0 61.608 0.084 ;
    END
  END w16_data[38]
  PIN w16_data[390]
    DIRECTION INPUT ;
    USE SIGNAL ;
    PORT
      LAYER M5 ;
        RECT  176.784 0 176.808 0.084 ;
    END
  END w16_data[390]
  PIN w16_data[391]
    DIRECTION INPUT ;
    USE SIGNAL ;
    PORT
      LAYER M5 ;
        RECT  176.88 0 176.904 0.084 ;
    END
  END w16_data[391]
  PIN w16_data[392]
    DIRECTION INPUT ;
    USE SIGNAL ;
    PORT
      LAYER M5 ;
        RECT  176.976 0 177 0.084 ;
    END
  END w16_data[392]
  PIN w16_data[393]
    DIRECTION INPUT ;
    USE SIGNAL ;
    PORT
      LAYER M5 ;
        RECT  177.072 0 177.096 0.084 ;
    END
  END w16_data[393]
  PIN w16_data[394]
    DIRECTION INPUT ;
    USE SIGNAL ;
    PORT
      LAYER M5 ;
        RECT  177.168 0 177.192 0.084 ;
    END
  END w16_data[394]
  PIN w16_data[395]
    DIRECTION INPUT ;
    USE SIGNAL ;
    PORT
      LAYER M5 ;
        RECT  177.264 0 177.288 0.084 ;
    END
  END w16_data[395]
  PIN w16_data[396]
    DIRECTION INPUT ;
    USE SIGNAL ;
    PORT
      LAYER M5 ;
        RECT  177.36 0 177.384 0.084 ;
    END
  END w16_data[396]
  PIN w16_data[397]
    DIRECTION INPUT ;
    USE SIGNAL ;
    PORT
      LAYER M5 ;
        RECT  177.456 0 177.48 0.084 ;
    END
  END w16_data[397]
  PIN w16_data[398]
    DIRECTION INPUT ;
    USE SIGNAL ;
    PORT
      LAYER M5 ;
        RECT  177.552 0 177.576 0.084 ;
    END
  END w16_data[398]
  PIN w16_data[399]
    DIRECTION INPUT ;
    USE SIGNAL ;
    PORT
      LAYER M5 ;
        RECT  177.648 0 177.672 0.084 ;
    END
  END w16_data[399]
  PIN w16_data[39]
    DIRECTION INPUT ;
    USE SIGNAL ;
    PORT
      LAYER M5 ;
        RECT  61.68 0 61.704 0.084 ;
    END
  END w16_data[39]
  PIN w16_data[3]
    DIRECTION INPUT ;
    USE SIGNAL ;
    PORT
      LAYER M5 ;
        RECT  73.584 0 73.608 0.084 ;
    END
  END w16_data[3]
  PIN w16_data[400]
    DIRECTION INPUT ;
    USE SIGNAL ;
    PORT
      LAYER M5 ;
        RECT  177.744 0 177.768 0.084 ;
    END
  END w16_data[400]
  PIN w16_data[401]
    DIRECTION INPUT ;
    USE SIGNAL ;
    PORT
      LAYER M5 ;
        RECT  177.84 0 177.864 0.084 ;
    END
  END w16_data[401]
  PIN w16_data[402]
    DIRECTION INPUT ;
    USE SIGNAL ;
    PORT
      LAYER M5 ;
        RECT  177.936 0 177.96 0.084 ;
    END
  END w16_data[402]
  PIN w16_data[403]
    DIRECTION INPUT ;
    USE SIGNAL ;
    PORT
      LAYER M5 ;
        RECT  178.032 0 178.056 0.084 ;
    END
  END w16_data[403]
  PIN w16_data[404]
    DIRECTION INPUT ;
    USE SIGNAL ;
    PORT
      LAYER M5 ;
        RECT  178.128 0 178.152 0.084 ;
    END
  END w16_data[404]
  PIN w16_data[405]
    DIRECTION INPUT ;
    USE SIGNAL ;
    PORT
      LAYER M5 ;
        RECT  178.224 0 178.248 0.084 ;
    END
  END w16_data[405]
  PIN w16_data[406]
    DIRECTION INPUT ;
    USE SIGNAL ;
    PORT
      LAYER M5 ;
        RECT  178.32 0 178.344 0.084 ;
    END
  END w16_data[406]
  PIN w16_data[407]
    DIRECTION INPUT ;
    USE SIGNAL ;
    PORT
      LAYER M5 ;
        RECT  178.416 0 178.44 0.084 ;
    END
  END w16_data[407]
  PIN w16_data[408]
    DIRECTION INPUT ;
    USE SIGNAL ;
    PORT
      LAYER M5 ;
        RECT  178.512 0 178.536 0.084 ;
    END
  END w16_data[408]
  PIN w16_data[409]
    DIRECTION INPUT ;
    USE SIGNAL ;
    PORT
      LAYER M5 ;
        RECT  178.608 0 178.632 0.084 ;
    END
  END w16_data[409]
  PIN w16_data[40]
    DIRECTION INPUT ;
    USE SIGNAL ;
    PORT
      LAYER M5 ;
        RECT  61.776 0 61.8 0.084 ;
    END
  END w16_data[40]
  PIN w16_data[410]
    DIRECTION INPUT ;
    USE SIGNAL ;
    PORT
      LAYER M5 ;
        RECT  178.704 0 178.728 0.084 ;
    END
  END w16_data[410]
  PIN w16_data[411]
    DIRECTION INPUT ;
    USE SIGNAL ;
    PORT
      LAYER M5 ;
        RECT  178.8 0 178.824 0.084 ;
    END
  END w16_data[411]
  PIN w16_data[412]
    DIRECTION INPUT ;
    USE SIGNAL ;
    PORT
      LAYER M5 ;
        RECT  178.896 0 178.92 0.084 ;
    END
  END w16_data[412]
  PIN w16_data[413]
    DIRECTION INPUT ;
    USE SIGNAL ;
    PORT
      LAYER M5 ;
        RECT  178.992 0 179.016 0.084 ;
    END
  END w16_data[413]
  PIN w16_data[414]
    DIRECTION INPUT ;
    USE SIGNAL ;
    PORT
      LAYER M5 ;
        RECT  179.088 0 179.112 0.084 ;
    END
  END w16_data[414]
  PIN w16_data[415]
    DIRECTION INPUT ;
    USE SIGNAL ;
    PORT
      LAYER M5 ;
        RECT  179.184 0 179.208 0.084 ;
    END
  END w16_data[415]
  PIN w16_data[416]
    DIRECTION INPUT ;
    USE SIGNAL ;
    PORT
      LAYER M5 ;
        RECT  179.28 0 179.304 0.084 ;
    END
  END w16_data[416]
  PIN w16_data[417]
    DIRECTION INPUT ;
    USE SIGNAL ;
    PORT
      LAYER M5 ;
        RECT  179.376 0 179.4 0.084 ;
    END
  END w16_data[417]
  PIN w16_data[418]
    DIRECTION INPUT ;
    USE SIGNAL ;
    PORT
      LAYER M5 ;
        RECT  179.472 0 179.496 0.084 ;
    END
  END w16_data[418]
  PIN w16_data[419]
    DIRECTION INPUT ;
    USE SIGNAL ;
    PORT
      LAYER M5 ;
        RECT  179.568 0 179.592 0.084 ;
    END
  END w16_data[419]
  PIN w16_data[41]
    DIRECTION INPUT ;
    USE SIGNAL ;
    PORT
      LAYER M5 ;
        RECT  61.872 0 61.896 0.084 ;
    END
  END w16_data[41]
  PIN w16_data[420]
    DIRECTION INPUT ;
    USE SIGNAL ;
    PORT
      LAYER M5 ;
        RECT  182.736 0 182.76 0.084 ;
    END
  END w16_data[420]
  PIN w16_data[421]
    DIRECTION INPUT ;
    USE SIGNAL ;
    PORT
      LAYER M5 ;
        RECT  182.832 0 182.856 0.084 ;
    END
  END w16_data[421]
  PIN w16_data[422]
    DIRECTION INPUT ;
    USE SIGNAL ;
    PORT
      LAYER M5 ;
        RECT  182.928 0 182.952 0.084 ;
    END
  END w16_data[422]
  PIN w16_data[423]
    DIRECTION INPUT ;
    USE SIGNAL ;
    PORT
      LAYER M5 ;
        RECT  183.024 0 183.048 0.084 ;
    END
  END w16_data[423]
  PIN w16_data[424]
    DIRECTION INPUT ;
    USE SIGNAL ;
    PORT
      LAYER M5 ;
        RECT  183.12 0 183.144 0.084 ;
    END
  END w16_data[424]
  PIN w16_data[425]
    DIRECTION INPUT ;
    USE SIGNAL ;
    PORT
      LAYER M5 ;
        RECT  183.216 0 183.24 0.084 ;
    END
  END w16_data[425]
  PIN w16_data[426]
    DIRECTION INPUT ;
    USE SIGNAL ;
    PORT
      LAYER M5 ;
        RECT  183.312 0 183.336 0.084 ;
    END
  END w16_data[426]
  PIN w16_data[427]
    DIRECTION INPUT ;
    USE SIGNAL ;
    PORT
      LAYER M5 ;
        RECT  183.408 0 183.432 0.084 ;
    END
  END w16_data[427]
  PIN w16_data[428]
    DIRECTION INPUT ;
    USE SIGNAL ;
    PORT
      LAYER M5 ;
        RECT  183.504 0 183.528 0.084 ;
    END
  END w16_data[428]
  PIN w16_data[429]
    DIRECTION INPUT ;
    USE SIGNAL ;
    PORT
      LAYER M5 ;
        RECT  183.6 0 183.624 0.084 ;
    END
  END w16_data[429]
  PIN w16_data[42]
    DIRECTION INPUT ;
    USE SIGNAL ;
    PORT
      LAYER M5 ;
        RECT  61.968 0 61.992 0.084 ;
    END
  END w16_data[42]
  PIN w16_data[430]
    DIRECTION INPUT ;
    USE SIGNAL ;
    PORT
      LAYER M5 ;
        RECT  183.696 0 183.72 0.084 ;
    END
  END w16_data[430]
  PIN w16_data[431]
    DIRECTION INPUT ;
    USE SIGNAL ;
    PORT
      LAYER M5 ;
        RECT  183.792 0 183.816 0.084 ;
    END
  END w16_data[431]
  PIN w16_data[432]
    DIRECTION INPUT ;
    USE SIGNAL ;
    PORT
      LAYER M5 ;
        RECT  183.888 0 183.912 0.084 ;
    END
  END w16_data[432]
  PIN w16_data[433]
    DIRECTION INPUT ;
    USE SIGNAL ;
    PORT
      LAYER M5 ;
        RECT  183.984 0 184.008 0.084 ;
    END
  END w16_data[433]
  PIN w16_data[434]
    DIRECTION INPUT ;
    USE SIGNAL ;
    PORT
      LAYER M5 ;
        RECT  184.08 0 184.104 0.084 ;
    END
  END w16_data[434]
  PIN w16_data[435]
    DIRECTION INPUT ;
    USE SIGNAL ;
    PORT
      LAYER M5 ;
        RECT  184.176 0 184.2 0.084 ;
    END
  END w16_data[435]
  PIN w16_data[436]
    DIRECTION INPUT ;
    USE SIGNAL ;
    PORT
      LAYER M5 ;
        RECT  184.272 0 184.296 0.084 ;
    END
  END w16_data[436]
  PIN w16_data[437]
    DIRECTION INPUT ;
    USE SIGNAL ;
    PORT
      LAYER M5 ;
        RECT  184.368 0 184.392 0.084 ;
    END
  END w16_data[437]
  PIN w16_data[438]
    DIRECTION INPUT ;
    USE SIGNAL ;
    PORT
      LAYER M5 ;
        RECT  184.464 0 184.488 0.084 ;
    END
  END w16_data[438]
  PIN w16_data[439]
    DIRECTION INPUT ;
    USE SIGNAL ;
    PORT
      LAYER M5 ;
        RECT  184.56 0 184.584 0.084 ;
    END
  END w16_data[439]
  PIN w16_data[43]
    DIRECTION INPUT ;
    USE SIGNAL ;
    PORT
      LAYER M5 ;
        RECT  62.064 0 62.088 0.084 ;
    END
  END w16_data[43]
  PIN w16_data[440]
    DIRECTION INPUT ;
    USE SIGNAL ;
    PORT
      LAYER M5 ;
        RECT  184.656 0 184.68 0.084 ;
    END
  END w16_data[440]
  PIN w16_data[441]
    DIRECTION INPUT ;
    USE SIGNAL ;
    PORT
      LAYER M5 ;
        RECT  184.752 0 184.776 0.084 ;
    END
  END w16_data[441]
  PIN w16_data[442]
    DIRECTION INPUT ;
    USE SIGNAL ;
    PORT
      LAYER M5 ;
        RECT  184.848 0 184.872 0.084 ;
    END
  END w16_data[442]
  PIN w16_data[443]
    DIRECTION INPUT ;
    USE SIGNAL ;
    PORT
      LAYER M5 ;
        RECT  184.944 0 184.968 0.084 ;
    END
  END w16_data[443]
  PIN w16_data[444]
    DIRECTION INPUT ;
    USE SIGNAL ;
    PORT
      LAYER M5 ;
        RECT  185.04 0 185.064 0.084 ;
    END
  END w16_data[444]
  PIN w16_data[445]
    DIRECTION INPUT ;
    USE SIGNAL ;
    PORT
      LAYER M5 ;
        RECT  185.136 0 185.16 0.084 ;
    END
  END w16_data[445]
  PIN w16_data[446]
    DIRECTION INPUT ;
    USE SIGNAL ;
    PORT
      LAYER M5 ;
        RECT  185.232 0 185.256 0.084 ;
    END
  END w16_data[446]
  PIN w16_data[447]
    DIRECTION INPUT ;
    USE SIGNAL ;
    PORT
      LAYER M5 ;
        RECT  185.328 0 185.352 0.084 ;
    END
  END w16_data[447]
  PIN w16_data[448]
    DIRECTION INPUT ;
    USE SIGNAL ;
    PORT
      LAYER M5 ;
        RECT  185.424 0 185.448 0.084 ;
    END
  END w16_data[448]
  PIN w16_data[449]
    DIRECTION INPUT ;
    USE SIGNAL ;
    PORT
      LAYER M5 ;
        RECT  185.52 0 185.544 0.084 ;
    END
  END w16_data[449]
  PIN w16_data[44]
    DIRECTION INPUT ;
    USE SIGNAL ;
    PORT
      LAYER M5 ;
        RECT  62.16 0 62.184 0.084 ;
    END
  END w16_data[44]
  PIN w16_data[450]
    DIRECTION INPUT ;
    USE SIGNAL ;
    PORT
      LAYER M5 ;
        RECT  185.616 0 185.64 0.084 ;
    END
  END w16_data[450]
  PIN w16_data[451]
    DIRECTION INPUT ;
    USE SIGNAL ;
    PORT
      LAYER M5 ;
        RECT  185.712 0 185.736 0.084 ;
    END
  END w16_data[451]
  PIN w16_data[452]
    DIRECTION INPUT ;
    USE SIGNAL ;
    PORT
      LAYER M5 ;
        RECT  201.936 0 201.96 0.084 ;
    END
  END w16_data[452]
  PIN w16_data[453]
    DIRECTION INPUT ;
    USE SIGNAL ;
    PORT
      LAYER M5 ;
        RECT  202.032 0 202.056 0.084 ;
    END
  END w16_data[453]
  PIN w16_data[454]
    DIRECTION INPUT ;
    USE SIGNAL ;
    PORT
      LAYER M5 ;
        RECT  202.128 0 202.152 0.084 ;
    END
  END w16_data[454]
  PIN w16_data[455]
    DIRECTION INPUT ;
    USE SIGNAL ;
    PORT
      LAYER M5 ;
        RECT  202.224 0 202.248 0.084 ;
    END
  END w16_data[455]
  PIN w16_data[456]
    DIRECTION INPUT ;
    USE SIGNAL ;
    PORT
      LAYER M5 ;
        RECT  202.32 0 202.344 0.084 ;
    END
  END w16_data[456]
  PIN w16_data[457]
    DIRECTION INPUT ;
    USE SIGNAL ;
    PORT
      LAYER M5 ;
        RECT  202.416 0 202.44 0.084 ;
    END
  END w16_data[457]
  PIN w16_data[458]
    DIRECTION INPUT ;
    USE SIGNAL ;
    PORT
      LAYER M5 ;
        RECT  202.512 0 202.536 0.084 ;
    END
  END w16_data[458]
  PIN w16_data[459]
    DIRECTION INPUT ;
    USE SIGNAL ;
    PORT
      LAYER M5 ;
        RECT  202.608 0 202.632 0.084 ;
    END
  END w16_data[459]
  PIN w16_data[45]
    DIRECTION INPUT ;
    USE SIGNAL ;
    PORT
      LAYER M5 ;
        RECT  62.256 0 62.28 0.084 ;
    END
  END w16_data[45]
  PIN w16_data[460]
    DIRECTION INPUT ;
    USE SIGNAL ;
    PORT
      LAYER M5 ;
        RECT  202.704 0 202.728 0.084 ;
    END
  END w16_data[460]
  PIN w16_data[461]
    DIRECTION INPUT ;
    USE SIGNAL ;
    PORT
      LAYER M5 ;
        RECT  202.8 0 202.824 0.084 ;
    END
  END w16_data[461]
  PIN w16_data[462]
    DIRECTION INPUT ;
    USE SIGNAL ;
    PORT
      LAYER M5 ;
        RECT  202.896 0 202.92 0.084 ;
    END
  END w16_data[462]
  PIN w16_data[463]
    DIRECTION INPUT ;
    USE SIGNAL ;
    PORT
      LAYER M5 ;
        RECT  202.992 0 203.016 0.084 ;
    END
  END w16_data[463]
  PIN w16_data[464]
    DIRECTION INPUT ;
    USE SIGNAL ;
    PORT
      LAYER M5 ;
        RECT  203.088 0 203.112 0.084 ;
    END
  END w16_data[464]
  PIN w16_data[465]
    DIRECTION INPUT ;
    USE SIGNAL ;
    PORT
      LAYER M5 ;
        RECT  203.184 0 203.208 0.084 ;
    END
  END w16_data[465]
  PIN w16_data[466]
    DIRECTION INPUT ;
    USE SIGNAL ;
    PORT
      LAYER M5 ;
        RECT  203.28 0 203.304 0.084 ;
    END
  END w16_data[466]
  PIN w16_data[467]
    DIRECTION INPUT ;
    USE SIGNAL ;
    PORT
      LAYER M5 ;
        RECT  203.376 0 203.4 0.084 ;
    END
  END w16_data[467]
  PIN w16_data[468]
    DIRECTION INPUT ;
    USE SIGNAL ;
    PORT
      LAYER M5 ;
        RECT  203.472 0 203.496 0.084 ;
    END
  END w16_data[468]
  PIN w16_data[469]
    DIRECTION INPUT ;
    USE SIGNAL ;
    PORT
      LAYER M5 ;
        RECT  203.568 0 203.592 0.084 ;
    END
  END w16_data[469]
  PIN w16_data[46]
    DIRECTION INPUT ;
    USE SIGNAL ;
    PORT
      LAYER M5 ;
        RECT  62.352 0 62.376 0.084 ;
    END
  END w16_data[46]
  PIN w16_data[470]
    DIRECTION INPUT ;
    USE SIGNAL ;
    PORT
      LAYER M5 ;
        RECT  203.664 0 203.688 0.084 ;
    END
  END w16_data[470]
  PIN w16_data[471]
    DIRECTION INPUT ;
    USE SIGNAL ;
    PORT
      LAYER M5 ;
        RECT  203.76 0 203.784 0.084 ;
    END
  END w16_data[471]
  PIN w16_data[472]
    DIRECTION INPUT ;
    USE SIGNAL ;
    PORT
      LAYER M5 ;
        RECT  203.856 0 203.88 0.084 ;
    END
  END w16_data[472]
  PIN w16_data[473]
    DIRECTION INPUT ;
    USE SIGNAL ;
    PORT
      LAYER M5 ;
        RECT  203.952 0 203.976 0.084 ;
    END
  END w16_data[473]
  PIN w16_data[474]
    DIRECTION INPUT ;
    USE SIGNAL ;
    PORT
      LAYER M5 ;
        RECT  204.048 0 204.072 0.084 ;
    END
  END w16_data[474]
  PIN w16_data[475]
    DIRECTION INPUT ;
    USE SIGNAL ;
    PORT
      LAYER M5 ;
        RECT  204.144 0 204.168 0.084 ;
    END
  END w16_data[475]
  PIN w16_data[476]
    DIRECTION INPUT ;
    USE SIGNAL ;
    PORT
      LAYER M5 ;
        RECT  204.24 0 204.264 0.084 ;
    END
  END w16_data[476]
  PIN w16_data[477]
    DIRECTION INPUT ;
    USE SIGNAL ;
    PORT
      LAYER M5 ;
        RECT  204.336 0 204.36 0.084 ;
    END
  END w16_data[477]
  PIN w16_data[478]
    DIRECTION INPUT ;
    USE SIGNAL ;
    PORT
      LAYER M5 ;
        RECT  204.432 0 204.456 0.084 ;
    END
  END w16_data[478]
  PIN w16_data[479]
    DIRECTION INPUT ;
    USE SIGNAL ;
    PORT
      LAYER M5 ;
        RECT  204.528 0 204.552 0.084 ;
    END
  END w16_data[479]
  PIN w16_data[47]
    DIRECTION INPUT ;
    USE SIGNAL ;
    PORT
      LAYER M5 ;
        RECT  62.448 0 62.472 0.084 ;
    END
  END w16_data[47]
  PIN w16_data[480]
    DIRECTION INPUT ;
    USE SIGNAL ;
    PORT
      LAYER M5 ;
        RECT  204.624 0 204.648 0.084 ;
    END
  END w16_data[480]
  PIN w16_data[481]
    DIRECTION INPUT ;
    USE SIGNAL ;
    PORT
      LAYER M5 ;
        RECT  204.72 0 204.744 0.084 ;
    END
  END w16_data[481]
  PIN w16_data[482]
    DIRECTION INPUT ;
    USE SIGNAL ;
    PORT
      LAYER M5 ;
        RECT  204.816 0 204.84 0.084 ;
    END
  END w16_data[482]
  PIN w16_data[483]
    DIRECTION INPUT ;
    USE SIGNAL ;
    PORT
      LAYER M5 ;
        RECT  204.912 0 204.936 0.084 ;
    END
  END w16_data[483]
  PIN w16_data[484]
    DIRECTION INPUT ;
    USE SIGNAL ;
    PORT
      LAYER M5 ;
        RECT  205.008 0 205.032 0.084 ;
    END
  END w16_data[484]
  PIN w16_data[485]
    DIRECTION INPUT ;
    USE SIGNAL ;
    PORT
      LAYER M5 ;
        RECT  205.104 0 205.128 0.084 ;
    END
  END w16_data[485]
  PIN w16_data[486]
    DIRECTION INPUT ;
    USE SIGNAL ;
    PORT
      LAYER M5 ;
        RECT  205.2 0 205.224 0.084 ;
    END
  END w16_data[486]
  PIN w16_data[487]
    DIRECTION INPUT ;
    USE SIGNAL ;
    PORT
      LAYER M5 ;
        RECT  205.296 0 205.32 0.084 ;
    END
  END w16_data[487]
  PIN w16_data[488]
    DIRECTION INPUT ;
    USE SIGNAL ;
    PORT
      LAYER M5 ;
        RECT  205.392 0 205.416 0.084 ;
    END
  END w16_data[488]
  PIN w16_data[489]
    DIRECTION INPUT ;
    USE SIGNAL ;
    PORT
      LAYER M5 ;
        RECT  205.488 0 205.512 0.084 ;
    END
  END w16_data[489]
  PIN w16_data[48]
    DIRECTION INPUT ;
    USE SIGNAL ;
    PORT
      LAYER M5 ;
        RECT  62.544 0 62.568 0.084 ;
    END
  END w16_data[48]
  PIN w16_data[490]
    DIRECTION INPUT ;
    USE SIGNAL ;
    PORT
      LAYER M5 ;
        RECT  205.584 0 205.608 0.084 ;
    END
  END w16_data[490]
  PIN w16_data[491]
    DIRECTION INPUT ;
    USE SIGNAL ;
    PORT
      LAYER M5 ;
        RECT  205.68 0 205.704 0.084 ;
    END
  END w16_data[491]
  PIN w16_data[492]
    DIRECTION INPUT ;
    USE SIGNAL ;
    PORT
      LAYER M5 ;
        RECT  205.776 0 205.8 0.084 ;
    END
  END w16_data[492]
  PIN w16_data[493]
    DIRECTION INPUT ;
    USE SIGNAL ;
    PORT
      LAYER M5 ;
        RECT  205.872 0 205.896 0.084 ;
    END
  END w16_data[493]
  PIN w16_data[494]
    DIRECTION INPUT ;
    USE SIGNAL ;
    PORT
      LAYER M5 ;
        RECT  205.968 0 205.992 0.084 ;
    END
  END w16_data[494]
  PIN w16_data[495]
    DIRECTION INPUT ;
    USE SIGNAL ;
    PORT
      LAYER M5 ;
        RECT  206.064 0 206.088 0.084 ;
    END
  END w16_data[495]
  PIN w16_data[496]
    DIRECTION INPUT ;
    USE SIGNAL ;
    PORT
      LAYER M5 ;
        RECT  206.16 0 206.184 0.084 ;
    END
  END w16_data[496]
  PIN w16_data[497]
    DIRECTION INPUT ;
    USE SIGNAL ;
    PORT
      LAYER M5 ;
        RECT  206.256 0 206.28 0.084 ;
    END
  END w16_data[497]
  PIN w16_data[498]
    DIRECTION INPUT ;
    USE SIGNAL ;
    PORT
      LAYER M5 ;
        RECT  206.352 0 206.376 0.084 ;
    END
  END w16_data[498]
  PIN w16_data[499]
    DIRECTION INPUT ;
    USE SIGNAL ;
    PORT
      LAYER M5 ;
        RECT  206.448 0 206.472 0.084 ;
    END
  END w16_data[499]
  PIN w16_data[49]
    DIRECTION INPUT ;
    USE SIGNAL ;
    PORT
      LAYER M5 ;
        RECT  62.64 0 62.664 0.084 ;
    END
  END w16_data[49]
  PIN w16_data[4]
    DIRECTION INPUT ;
    USE SIGNAL ;
    PORT
      LAYER M5 ;
        RECT  64.464 0 64.488 0.084 ;
    END
  END w16_data[4]
  PIN w16_data[500]
    DIRECTION INPUT ;
    USE SIGNAL ;
    PORT
      LAYER M5 ;
        RECT  206.544 0 206.568 0.084 ;
    END
  END w16_data[500]
  PIN w16_data[501]
    DIRECTION INPUT ;
    USE SIGNAL ;
    PORT
      LAYER M5 ;
        RECT  206.64 0 206.664 0.084 ;
    END
  END w16_data[501]
  PIN w16_data[502]
    DIRECTION INPUT ;
    USE SIGNAL ;
    PORT
      LAYER M5 ;
        RECT  206.736 0 206.76 0.084 ;
    END
  END w16_data[502]
  PIN w16_data[503]
    DIRECTION INPUT ;
    USE SIGNAL ;
    PORT
      LAYER M5 ;
        RECT  206.832 0 206.856 0.084 ;
    END
  END w16_data[503]
  PIN w16_data[504]
    DIRECTION INPUT ;
    USE SIGNAL ;
    PORT
      LAYER M5 ;
        RECT  206.928 0 206.952 0.084 ;
    END
  END w16_data[504]
  PIN w16_data[505]
    DIRECTION INPUT ;
    USE SIGNAL ;
    PORT
      LAYER M5 ;
        RECT  207.024 0 207.048 0.084 ;
    END
  END w16_data[505]
  PIN w16_data[506]
    DIRECTION INPUT ;
    USE SIGNAL ;
    PORT
      LAYER M5 ;
        RECT  207.12 0 207.144 0.084 ;
    END
  END w16_data[506]
  PIN w16_data[507]
    DIRECTION INPUT ;
    USE SIGNAL ;
    PORT
      LAYER M5 ;
        RECT  207.216 0 207.24 0.084 ;
    END
  END w16_data[507]
  PIN w16_data[508]
    DIRECTION INPUT ;
    USE SIGNAL ;
    PORT
      LAYER M5 ;
        RECT  207.312 0 207.336 0.084 ;
    END
  END w16_data[508]
  PIN w16_data[509]
    DIRECTION INPUT ;
    USE SIGNAL ;
    PORT
      LAYER M5 ;
        RECT  207.408 0 207.432 0.084 ;
    END
  END w16_data[509]
  PIN w16_data[50]
    DIRECTION INPUT ;
    USE SIGNAL ;
    PORT
      LAYER M5 ;
        RECT  62.736 0 62.76 0.084 ;
    END
  END w16_data[50]
  PIN w16_data[510]
    DIRECTION INPUT ;
    USE SIGNAL ;
    PORT
      LAYER M5 ;
        RECT  207.504 0 207.528 0.084 ;
    END
  END w16_data[510]
  PIN w16_data[511]
    DIRECTION INPUT ;
    USE SIGNAL ;
    PORT
      LAYER M5 ;
        RECT  207.6 0 207.624 0.084 ;
    END
  END w16_data[511]
  PIN w16_data[51]
    DIRECTION INPUT ;
    USE SIGNAL ;
    PORT
      LAYER M5 ;
        RECT  62.832 0 62.856 0.084 ;
    END
  END w16_data[51]
  PIN w16_data[52]
    DIRECTION INPUT ;
    USE SIGNAL ;
    PORT
      LAYER M5 ;
        RECT  62.928 0 62.952 0.084 ;
    END
  END w16_data[52]
  PIN w16_data[53]
    DIRECTION INPUT ;
    USE SIGNAL ;
    PORT
      LAYER M5 ;
        RECT  63.024 0 63.048 0.084 ;
    END
  END w16_data[53]
  PIN w16_data[54]
    DIRECTION INPUT ;
    USE SIGNAL ;
    PORT
      LAYER M5 ;
        RECT  63.12 0 63.144 0.084 ;
    END
  END w16_data[54]
  PIN w16_data[55]
    DIRECTION INPUT ;
    USE SIGNAL ;
    PORT
      LAYER M5 ;
        RECT  63.216 0 63.24 0.084 ;
    END
  END w16_data[55]
  PIN w16_data[56]
    DIRECTION INPUT ;
    USE SIGNAL ;
    PORT
      LAYER M5 ;
        RECT  63.312 0 63.336 0.084 ;
    END
  END w16_data[56]
  PIN w16_data[57]
    DIRECTION INPUT ;
    USE SIGNAL ;
    PORT
      LAYER M5 ;
        RECT  63.408 0 63.432 0.084 ;
    END
  END w16_data[57]
  PIN w16_data[58]
    DIRECTION INPUT ;
    USE SIGNAL ;
    PORT
      LAYER M5 ;
        RECT  63.504 0 63.528 0.084 ;
    END
  END w16_data[58]
  PIN w16_data[59]
    DIRECTION INPUT ;
    USE SIGNAL ;
    PORT
      LAYER M5 ;
        RECT  63.6 0 63.624 0.084 ;
    END
  END w16_data[59]
  PIN w16_data[5]
    DIRECTION INPUT ;
    USE SIGNAL ;
    PORT
      LAYER M5 ;
        RECT  64.56 0 64.584 0.084 ;
    END
  END w16_data[5]
  PIN w16_data[60]
    DIRECTION INPUT ;
    USE SIGNAL ;
    PORT
      LAYER M5 ;
        RECT  63.696 0 63.72 0.084 ;
    END
  END w16_data[60]
  PIN w16_data[61]
    DIRECTION INPUT ;
    USE SIGNAL ;
    PORT
      LAYER M5 ;
        RECT  63.792 0 63.816 0.084 ;
    END
  END w16_data[61]
  PIN w16_data[62]
    DIRECTION INPUT ;
    USE SIGNAL ;
    PORT
      LAYER M5 ;
        RECT  63.888 0 63.912 0.084 ;
    END
  END w16_data[62]
  PIN w16_data[63]
    DIRECTION INPUT ;
    USE SIGNAL ;
    PORT
      LAYER M5 ;
        RECT  63.984 0 64.008 0.084 ;
    END
  END w16_data[63]
  PIN w16_data[64]
    DIRECTION INPUT ;
    USE SIGNAL ;
    PORT
      LAYER M5 ;
        RECT  64.08 0 64.104 0.084 ;
    END
  END w16_data[64]
  PIN w16_data[65]
    DIRECTION INPUT ;
    USE SIGNAL ;
    PORT
      LAYER M5 ;
        RECT  64.176 0 64.2 0.084 ;
    END
  END w16_data[65]
  PIN w16_data[66]
    DIRECTION INPUT ;
    USE SIGNAL ;
    PORT
      LAYER M5 ;
        RECT  64.272 0 64.296 0.084 ;
    END
  END w16_data[66]
  PIN w16_data[67]
    DIRECTION INPUT ;
    USE SIGNAL ;
    PORT
      LAYER M5 ;
        RECT  64.368 0 64.392 0.084 ;
    END
  END w16_data[67]
  PIN w16_data[68]
    DIRECTION INPUT ;
    USE SIGNAL ;
    PORT
      LAYER M5 ;
        RECT  58.32 0 58.344 0.084 ;
    END
  END w16_data[68]
  PIN w16_data[69]
    DIRECTION INPUT ;
    USE SIGNAL ;
    PORT
      LAYER M5 ;
        RECT  58.416 0 58.44 0.084 ;
    END
  END w16_data[69]
  PIN w16_data[6]
    DIRECTION INPUT ;
    USE SIGNAL ;
    PORT
      LAYER M5 ;
        RECT  64.656 0 64.68 0.084 ;
    END
  END w16_data[6]
  PIN w16_data[70]
    DIRECTION INPUT ;
    USE SIGNAL ;
    PORT
      LAYER M5 ;
        RECT  58.512 0 58.536 0.084 ;
    END
  END w16_data[70]
  PIN w16_data[71]
    DIRECTION INPUT ;
    USE SIGNAL ;
    PORT
      LAYER M5 ;
        RECT  58.608 0 58.632 0.084 ;
    END
  END w16_data[71]
  PIN w16_data[72]
    DIRECTION INPUT ;
    USE SIGNAL ;
    PORT
      LAYER M5 ;
        RECT  58.704 0 58.728 0.084 ;
    END
  END w16_data[72]
  PIN w16_data[73]
    DIRECTION INPUT ;
    USE SIGNAL ;
    PORT
      LAYER M5 ;
        RECT  58.8 0 58.824 0.084 ;
    END
  END w16_data[73]
  PIN w16_data[74]
    DIRECTION INPUT ;
    USE SIGNAL ;
    PORT
      LAYER M5 ;
        RECT  58.896 0 58.92 0.084 ;
    END
  END w16_data[74]
  PIN w16_data[75]
    DIRECTION INPUT ;
    USE SIGNAL ;
    PORT
      LAYER M5 ;
        RECT  58.992 0 59.016 0.084 ;
    END
  END w16_data[75]
  PIN w16_data[76]
    DIRECTION INPUT ;
    USE SIGNAL ;
    PORT
      LAYER M5 ;
        RECT  59.088 0 59.112 0.084 ;
    END
  END w16_data[76]
  PIN w16_data[77]
    DIRECTION INPUT ;
    USE SIGNAL ;
    PORT
      LAYER M5 ;
        RECT  59.184 0 59.208 0.084 ;
    END
  END w16_data[77]
  PIN w16_data[78]
    DIRECTION INPUT ;
    USE SIGNAL ;
    PORT
      LAYER M5 ;
        RECT  59.28 0 59.304 0.084 ;
    END
  END w16_data[78]
  PIN w16_data[79]
    DIRECTION INPUT ;
    USE SIGNAL ;
    PORT
      LAYER M5 ;
        RECT  59.376 0 59.4 0.084 ;
    END
  END w16_data[79]
  PIN w16_data[7]
    DIRECTION INPUT ;
    USE SIGNAL ;
    PORT
      LAYER M5 ;
        RECT  64.752 0 64.776 0.084 ;
    END
  END w16_data[7]
  PIN w16_data[80]
    DIRECTION INPUT ;
    USE SIGNAL ;
    PORT
      LAYER M5 ;
        RECT  59.472 0 59.496 0.084 ;
    END
  END w16_data[80]
  PIN w16_data[81]
    DIRECTION INPUT ;
    USE SIGNAL ;
    PORT
      LAYER M5 ;
        RECT  59.568 0 59.592 0.084 ;
    END
  END w16_data[81]
  PIN w16_data[82]
    DIRECTION INPUT ;
    USE SIGNAL ;
    PORT
      LAYER M5 ;
        RECT  59.664 0 59.688 0.084 ;
    END
  END w16_data[82]
  PIN w16_data[83]
    DIRECTION INPUT ;
    USE SIGNAL ;
    PORT
      LAYER M5 ;
        RECT  59.76 0 59.784 0.084 ;
    END
  END w16_data[83]
  PIN w16_data[84]
    DIRECTION INPUT ;
    USE SIGNAL ;
    PORT
      LAYER M5 ;
        RECT  59.856 0 59.88 0.084 ;
    END
  END w16_data[84]
  PIN w16_data[85]
    DIRECTION INPUT ;
    USE SIGNAL ;
    PORT
      LAYER M5 ;
        RECT  59.952 0 59.976 0.084 ;
    END
  END w16_data[85]
  PIN w16_data[86]
    DIRECTION INPUT ;
    USE SIGNAL ;
    PORT
      LAYER M5 ;
        RECT  60.048 0 60.072 0.084 ;
    END
  END w16_data[86]
  PIN w16_data[87]
    DIRECTION INPUT ;
    USE SIGNAL ;
    PORT
      LAYER M5 ;
        RECT  60.144 0 60.168 0.084 ;
    END
  END w16_data[87]
  PIN w16_data[88]
    DIRECTION INPUT ;
    USE SIGNAL ;
    PORT
      LAYER M5 ;
        RECT  60.24 0 60.264 0.084 ;
    END
  END w16_data[88]
  PIN w16_data[89]
    DIRECTION INPUT ;
    USE SIGNAL ;
    PORT
      LAYER M5 ;
        RECT  60.336 0 60.36 0.084 ;
    END
  END w16_data[89]
  PIN w16_data[8]
    DIRECTION INPUT ;
    USE SIGNAL ;
    PORT
      LAYER M5 ;
        RECT  64.848 0 64.872 0.084 ;
    END
  END w16_data[8]
  PIN w16_data[90]
    DIRECTION INPUT ;
    USE SIGNAL ;
    PORT
      LAYER M5 ;
        RECT  60.432 0 60.456 0.084 ;
    END
  END w16_data[90]
  PIN w16_data[91]
    DIRECTION INPUT ;
    USE SIGNAL ;
    PORT
      LAYER M5 ;
        RECT  60.528 0 60.552 0.084 ;
    END
  END w16_data[91]
  PIN w16_data[92]
    DIRECTION INPUT ;
    USE SIGNAL ;
    PORT
      LAYER M5 ;
        RECT  60.624 0 60.648 0.084 ;
    END
  END w16_data[92]
  PIN w16_data[93]
    DIRECTION INPUT ;
    USE SIGNAL ;
    PORT
      LAYER M5 ;
        RECT  60.72 0 60.744 0.084 ;
    END
  END w16_data[93]
  PIN w16_data[94]
    DIRECTION INPUT ;
    USE SIGNAL ;
    PORT
      LAYER M5 ;
        RECT  60.816 0 60.84 0.084 ;
    END
  END w16_data[94]
  PIN w16_data[95]
    DIRECTION INPUT ;
    USE SIGNAL ;
    PORT
      LAYER M5 ;
        RECT  60.912 0 60.936 0.084 ;
    END
  END w16_data[95]
  PIN w16_data[96]
    DIRECTION INPUT ;
    USE SIGNAL ;
    PORT
      LAYER M5 ;
        RECT  61.008 0 61.032 0.084 ;
    END
  END w16_data[96]
  PIN w16_data[97]
    DIRECTION INPUT ;
    USE SIGNAL ;
    PORT
      LAYER M5 ;
        RECT  61.104 0 61.128 0.084 ;
    END
  END w16_data[97]
  PIN w16_data[98]
    DIRECTION INPUT ;
    USE SIGNAL ;
    PORT
      LAYER M5 ;
        RECT  61.2 0 61.224 0.084 ;
    END
  END w16_data[98]
  PIN w16_data[99]
    DIRECTION INPUT ;
    USE SIGNAL ;
    PORT
      LAYER M5 ;
        RECT  61.296 0 61.32 0.084 ;
    END
  END w16_data[99]
  PIN w16_data[9]
    DIRECTION INPUT ;
    USE SIGNAL ;
    PORT
      LAYER M5 ;
        RECT  64.944 0 64.968 0.084 ;
    END
  END w16_data[9]
  PIN w16_we
    DIRECTION INPUT ;
    USE SIGNAL ;
    PORT
      LAYER M5 ;
        RECT  207.696 0 207.72 0.084 ;
    END
  END w16_we
  PIN w1_addr[0]
    DIRECTION INPUT ;
    USE SIGNAL ;
    PORT
      LAYER M5 ;
        RECT  74.736 0 74.76 0.084 ;
    END
  END w1_addr[0]
  PIN w1_addr[10]
    DIRECTION INPUT ;
    USE SIGNAL ;
    PORT
      LAYER M5 ;
        RECT  75.696 0 75.72 0.084 ;
    END
  END w1_addr[10]
  PIN w1_addr[11]
    DIRECTION INPUT ;
    USE SIGNAL ;
    PORT
      LAYER M5 ;
        RECT  75.792 0 75.816 0.084 ;
    END
  END w1_addr[11]
  PIN w1_addr[12]
    DIRECTION INPUT ;
    USE SIGNAL ;
    PORT
      LAYER M5 ;
        RECT  75.888 0 75.912 0.084 ;
    END
  END w1_addr[12]
  PIN w1_addr[13]
    DIRECTION INPUT ;
    USE SIGNAL ;
    PORT
      LAYER M5 ;
        RECT  75.984 0 76.008 0.084 ;
    END
  END w1_addr[13]
  PIN w1_addr[14]
    DIRECTION INPUT ;
    USE SIGNAL ;
    PORT
      LAYER M5 ;
        RECT  76.08 0 76.104 0.084 ;
    END
  END w1_addr[14]
  PIN w1_addr[15]
    DIRECTION INPUT ;
    USE SIGNAL ;
    PORT
      LAYER M5 ;
        RECT  76.176 0 76.2 0.084 ;
    END
  END w1_addr[15]
  PIN w1_addr[16]
    DIRECTION INPUT ;
    USE SIGNAL ;
    PORT
      LAYER M5 ;
        RECT  76.272 0 76.296 0.084 ;
    END
  END w1_addr[16]
  PIN w1_addr[17]
    DIRECTION INPUT ;
    USE SIGNAL ;
    PORT
      LAYER M5 ;
        RECT  76.368 0 76.392 0.084 ;
    END
  END w1_addr[17]
  PIN w1_addr[18]
    DIRECTION INPUT ;
    USE SIGNAL ;
    PORT
      LAYER M5 ;
        RECT  76.464 0 76.488 0.084 ;
    END
  END w1_addr[18]
  PIN w1_addr[19]
    DIRECTION INPUT ;
    USE SIGNAL ;
    PORT
      LAYER M5 ;
        RECT  76.56 0 76.584 0.084 ;
    END
  END w1_addr[19]
  PIN w1_addr[1]
    DIRECTION INPUT ;
    USE SIGNAL ;
    PORT
      LAYER M5 ;
        RECT  74.832 0 74.856 0.084 ;
    END
  END w1_addr[1]
  PIN w1_addr[20]
    DIRECTION INPUT ;
    USE SIGNAL ;
    PORT
      LAYER M5 ;
        RECT  76.656 0 76.68 0.084 ;
    END
  END w1_addr[20]
  PIN w1_addr[21]
    DIRECTION INPUT ;
    USE SIGNAL ;
    PORT
      LAYER M5 ;
        RECT  96.72 0 96.744 0.084 ;
    END
  END w1_addr[21]
  PIN w1_addr[22]
    DIRECTION INPUT ;
    USE SIGNAL ;
    PORT
      LAYER M5 ;
        RECT  96.816 0 96.84 0.084 ;
    END
  END w1_addr[22]
  PIN w1_addr[23]
    DIRECTION INPUT ;
    USE SIGNAL ;
    PORT
      LAYER M5 ;
        RECT  96.912 0 96.936 0.084 ;
    END
  END w1_addr[23]
  PIN w1_addr[2]
    DIRECTION INPUT ;
    USE SIGNAL ;
    PORT
      LAYER M5 ;
        RECT  74.928 0 74.952 0.084 ;
    END
  END w1_addr[2]
  PIN w1_addr[3]
    DIRECTION INPUT ;
    USE SIGNAL ;
    PORT
      LAYER M5 ;
        RECT  75.024 0 75.048 0.084 ;
    END
  END w1_addr[3]
  PIN w1_addr[4]
    DIRECTION INPUT ;
    USE SIGNAL ;
    PORT
      LAYER M5 ;
        RECT  75.12 0 75.144 0.084 ;
    END
  END w1_addr[4]
  PIN w1_addr[5]
    DIRECTION INPUT ;
    USE SIGNAL ;
    PORT
      LAYER M5 ;
        RECT  75.216 0 75.24 0.084 ;
    END
  END w1_addr[5]
  PIN w1_addr[6]
    DIRECTION INPUT ;
    USE SIGNAL ;
    PORT
      LAYER M5 ;
        RECT  75.312 0 75.336 0.084 ;
    END
  END w1_addr[6]
  PIN w1_addr[7]
    DIRECTION INPUT ;
    USE SIGNAL ;
    PORT
      LAYER M5 ;
        RECT  75.408 0 75.432 0.084 ;
    END
  END w1_addr[7]
  PIN w1_addr[8]
    DIRECTION INPUT ;
    USE SIGNAL ;
    PORT
      LAYER M5 ;
        RECT  75.504 0 75.528 0.084 ;
    END
  END w1_addr[8]
  PIN w1_addr[9]
    DIRECTION INPUT ;
    USE SIGNAL ;
    PORT
      LAYER M5 ;
        RECT  75.6 0 75.624 0.084 ;
    END
  END w1_addr[9]
  PIN w1_data[0]
    DIRECTION INPUT ;
    USE SIGNAL ;
    PORT
      LAYER M5 ;
        RECT  97.008 0 97.032 0.084 ;
    END
  END w1_data[0]
  PIN w1_data[10]
    DIRECTION INPUT ;
    USE SIGNAL ;
    PORT
      LAYER M5 ;
        RECT  97.968 0 97.992 0.084 ;
    END
  END w1_data[10]
  PIN w1_data[11]
    DIRECTION INPUT ;
    USE SIGNAL ;
    PORT
      LAYER M5 ;
        RECT  98.064 0 98.088 0.084 ;
    END
  END w1_data[11]
  PIN w1_data[12]
    DIRECTION INPUT ;
    USE SIGNAL ;
    PORT
      LAYER M5 ;
        RECT  98.16 0 98.184 0.084 ;
    END
  END w1_data[12]
  PIN w1_data[13]
    DIRECTION INPUT ;
    USE SIGNAL ;
    PORT
      LAYER M5 ;
        RECT  98.256 0 98.28 0.084 ;
    END
  END w1_data[13]
  PIN w1_data[14]
    DIRECTION INPUT ;
    USE SIGNAL ;
    PORT
      LAYER M5 ;
        RECT  98.352 0 98.376 0.084 ;
    END
  END w1_data[14]
  PIN w1_data[15]
    DIRECTION INPUT ;
    USE SIGNAL ;
    PORT
      LAYER M5 ;
        RECT  98.448 0 98.472 0.084 ;
    END
  END w1_data[15]
  PIN w1_data[16]
    DIRECTION INPUT ;
    USE SIGNAL ;
    PORT
      LAYER M5 ;
        RECT  98.544 0 98.568 0.084 ;
    END
  END w1_data[16]
  PIN w1_data[17]
    DIRECTION INPUT ;
    USE SIGNAL ;
    PORT
      LAYER M5 ;
        RECT  98.64 0 98.664 0.084 ;
    END
  END w1_data[17]
  PIN w1_data[18]
    DIRECTION INPUT ;
    USE SIGNAL ;
    PORT
      LAYER M5 ;
        RECT  98.736 0 98.76 0.084 ;
    END
  END w1_data[18]
  PIN w1_data[19]
    DIRECTION INPUT ;
    USE SIGNAL ;
    PORT
      LAYER M5 ;
        RECT  98.832 0 98.856 0.084 ;
    END
  END w1_data[19]
  PIN w1_data[1]
    DIRECTION INPUT ;
    USE SIGNAL ;
    PORT
      LAYER M5 ;
        RECT  97.104 0 97.128 0.084 ;
    END
  END w1_data[1]
  PIN w1_data[20]
    DIRECTION INPUT ;
    USE SIGNAL ;
    PORT
      LAYER M5 ;
        RECT  98.928 0 98.952 0.084 ;
    END
  END w1_data[20]
  PIN w1_data[21]
    DIRECTION INPUT ;
    USE SIGNAL ;
    PORT
      LAYER M5 ;
        RECT  99.024 0 99.048 0.084 ;
    END
  END w1_data[21]
  PIN w1_data[22]
    DIRECTION INPUT ;
    USE SIGNAL ;
    PORT
      LAYER M5 ;
        RECT  99.12 0 99.144 0.084 ;
    END
  END w1_data[22]
  PIN w1_data[23]
    DIRECTION INPUT ;
    USE SIGNAL ;
    PORT
      LAYER M5 ;
        RECT  99.216 0 99.24 0.084 ;
    END
  END w1_data[23]
  PIN w1_data[24]
    DIRECTION INPUT ;
    USE SIGNAL ;
    PORT
      LAYER M5 ;
        RECT  99.312 0 99.336 0.084 ;
    END
  END w1_data[24]
  PIN w1_data[25]
    DIRECTION INPUT ;
    USE SIGNAL ;
    PORT
      LAYER M5 ;
        RECT  99.408 0 99.432 0.084 ;
    END
  END w1_data[25]
  PIN w1_data[26]
    DIRECTION INPUT ;
    USE SIGNAL ;
    PORT
      LAYER M5 ;
        RECT  99.504 0 99.528 0.084 ;
    END
  END w1_data[26]
  PIN w1_data[27]
    DIRECTION INPUT ;
    USE SIGNAL ;
    PORT
      LAYER M5 ;
        RECT  99.6 0 99.624 0.084 ;
    END
  END w1_data[27]
  PIN w1_data[28]
    DIRECTION INPUT ;
    USE SIGNAL ;
    PORT
      LAYER M5 ;
        RECT  99.696 0 99.72 0.084 ;
    END
  END w1_data[28]
  PIN w1_data[29]
    DIRECTION INPUT ;
    USE SIGNAL ;
    PORT
      LAYER M5 ;
        RECT  70.608 0 70.632 0.084 ;
    END
  END w1_data[29]
  PIN w1_data[2]
    DIRECTION INPUT ;
    USE SIGNAL ;
    PORT
      LAYER M5 ;
        RECT  97.2 0 97.224 0.084 ;
    END
  END w1_data[2]
  PIN w1_data[30]
    DIRECTION INPUT ;
    USE SIGNAL ;
    PORT
      LAYER M5 ;
        RECT  70.704 0 70.728 0.084 ;
    END
  END w1_data[30]
  PIN w1_data[31]
    DIRECTION INPUT ;
    USE SIGNAL ;
    PORT
      LAYER M5 ;
        RECT  70.8 0 70.824 0.084 ;
    END
  END w1_data[31]
  PIN w1_data[3]
    DIRECTION INPUT ;
    USE SIGNAL ;
    PORT
      LAYER M5 ;
        RECT  97.296 0 97.32 0.084 ;
    END
  END w1_data[3]
  PIN w1_data[4]
    DIRECTION INPUT ;
    USE SIGNAL ;
    PORT
      LAYER M5 ;
        RECT  97.392 0 97.416 0.084 ;
    END
  END w1_data[4]
  PIN w1_data[5]
    DIRECTION INPUT ;
    USE SIGNAL ;
    PORT
      LAYER M5 ;
        RECT  97.488 0 97.512 0.084 ;
    END
  END w1_data[5]
  PIN w1_data[6]
    DIRECTION INPUT ;
    USE SIGNAL ;
    PORT
      LAYER M5 ;
        RECT  97.584 0 97.608 0.084 ;
    END
  END w1_data[6]
  PIN w1_data[7]
    DIRECTION INPUT ;
    USE SIGNAL ;
    PORT
      LAYER M5 ;
        RECT  97.68 0 97.704 0.084 ;
    END
  END w1_data[7]
  PIN w1_data[8]
    DIRECTION INPUT ;
    USE SIGNAL ;
    PORT
      LAYER M5 ;
        RECT  97.776 0 97.8 0.084 ;
    END
  END w1_data[8]
  PIN w1_data[9]
    DIRECTION INPUT ;
    USE SIGNAL ;
    PORT
      LAYER M5 ;
        RECT  97.872 0 97.896 0.084 ;
    END
  END w1_data[9]
  PIN w1_we
    DIRECTION INPUT ;
    USE SIGNAL ;
    PORT
      LAYER M5 ;
        RECT  70.896 0 70.92 0.084 ;
    END
  END w1_we
  PIN VDD
    DIRECTION INOUT ;
    USE POWER ;
    PORT
      LAYER M5 ;
        RECT  244.116 4.311 244.236 211.689 ;
        RECT  239.796 4.311 239.916 211.689 ;
        RECT  235.476 4.311 235.596 211.689 ;
        RECT  231.156 4.311 231.276 211.689 ;
        RECT  226.836 4.311 226.956 211.689 ;
        RECT  222.516 4.311 222.636 211.689 ;
        RECT  218.196 4.311 218.316 211.689 ;
        RECT  213.876 4.311 213.996 211.689 ;
        RECT  209.556 4.311 209.676 211.689 ;
        RECT  205.236 4.311 205.356 211.689 ;
        RECT  200.916 4.311 201.036 211.689 ;
        RECT  196.596 4.311 196.716 211.689 ;
        RECT  192.276 4.311 192.396 211.689 ;
        RECT  187.956 4.311 188.076 211.689 ;
        RECT  183.636 4.311 183.756 211.689 ;
        RECT  179.316 4.311 179.436 211.689 ;
        RECT  174.996 181.4 175.116 211.689 ;
        RECT  174.996 4.311 175.116 36.784 ;
        RECT  170.676 181.4 170.796 211.689 ;
        RECT  170.676 4.311 170.796 36.784 ;
        RECT  166.356 181.4 166.476 211.689 ;
        RECT  166.356 4.311 166.476 36.784 ;
        RECT  162.036 181.4 162.156 211.689 ;
        RECT  162.036 4.311 162.156 36.784 ;
        RECT  157.716 181.4 157.836 211.689 ;
        RECT  157.716 4.311 157.836 36.784 ;
        RECT  153.396 181.4 153.516 211.689 ;
        RECT  153.396 4.311 153.516 36.784 ;
        RECT  149.076 181.4 149.196 211.689 ;
        RECT  149.076 4.311 149.196 36.784 ;
        RECT  144.756 181.4 144.876 211.689 ;
        RECT  144.756 4.311 144.876 36.784 ;
        RECT  140.436 181.4 140.556 211.689 ;
        RECT  140.436 4.311 140.556 36.784 ;
        RECT  136.116 4.311 136.236 211.689 ;
        RECT  131.796 4.311 131.916 211.689 ;
        RECT  127.476 4.311 127.596 211.689 ;
        RECT  123.156 4.311 123.276 211.689 ;
        RECT  118.836 4.311 118.956 211.689 ;
        RECT  114.516 4.311 114.636 211.689 ;
        RECT  110.196 181.4 110.316 211.689 ;
        RECT  110.196 4.311 110.316 36.784 ;
        RECT  105.876 181.4 105.996 211.689 ;
        RECT  105.876 4.311 105.996 36.784 ;
        RECT  101.556 181.4 101.676 211.689 ;
        RECT  101.556 4.311 101.676 36.784 ;
        RECT  97.236 181.4 97.356 211.689 ;
        RECT  97.236 4.311 97.356 36.784 ;
        RECT  92.916 181.4 93.036 211.689 ;
        RECT  92.916 4.311 93.036 36.784 ;
        RECT  88.596 181.4 88.716 211.689 ;
        RECT  88.596 4.311 88.716 36.784 ;
        RECT  84.276 181.4 84.396 211.689 ;
        RECT  84.276 4.311 84.396 36.784 ;
        RECT  79.956 181.4 80.076 211.689 ;
        RECT  79.956 4.311 80.076 36.784 ;
        RECT  75.636 181.4 75.756 211.689 ;
        RECT  75.636 4.311 75.756 36.784 ;
        RECT  71.316 4.311 71.436 211.689 ;
        RECT  66.996 4.311 67.116 211.689 ;
        RECT  62.676 4.311 62.796 211.689 ;
        RECT  58.356 4.311 58.476 211.689 ;
        RECT  54.036 4.311 54.156 211.689 ;
        RECT  49.716 4.311 49.836 211.689 ;
        RECT  45.396 4.311 45.516 211.689 ;
        RECT  41.076 4.311 41.196 211.689 ;
        RECT  36.756 4.311 36.876 211.689 ;
        RECT  32.436 4.311 32.556 211.689 ;
        RECT  28.116 4.311 28.236 211.689 ;
        RECT  23.796 4.311 23.916 211.689 ;
        RECT  19.476 4.311 19.596 211.689 ;
        RECT  15.156 4.311 15.276 211.689 ;
        RECT  10.836 4.311 10.956 211.689 ;
        RECT  6.516 4.311 6.636 211.689 ;
    END
  END VDD
  PIN VSS
    DIRECTION INOUT ;
    USE GROUND ;
    PORT
      LAYER M5 ;
        RECT  243.924 4.297 244.044 211.703 ;
        RECT  239.604 4.297 239.724 211.703 ;
        RECT  235.284 4.297 235.404 211.703 ;
        RECT  230.964 4.297 231.084 211.703 ;
        RECT  226.644 4.297 226.764 211.703 ;
        RECT  222.324 4.297 222.444 211.703 ;
        RECT  218.004 4.297 218.124 211.703 ;
        RECT  213.684 4.297 213.804 211.703 ;
        RECT  209.364 4.297 209.484 211.703 ;
        RECT  205.044 4.297 205.164 211.703 ;
        RECT  200.724 4.297 200.844 211.703 ;
        RECT  196.404 4.297 196.524 211.703 ;
        RECT  192.084 4.297 192.204 211.703 ;
        RECT  187.764 4.297 187.884 211.703 ;
        RECT  183.444 4.297 183.564 211.703 ;
        RECT  179.124 4.297 179.244 211.703 ;
        RECT  174.804 181.4 174.924 211.703 ;
        RECT  174.804 4.297 174.924 36.784 ;
        RECT  170.484 181.4 170.604 211.703 ;
        RECT  170.484 4.297 170.604 36.784 ;
        RECT  166.164 181.4 166.284 211.703 ;
        RECT  166.164 4.297 166.284 36.784 ;
        RECT  161.844 181.4 161.964 211.703 ;
        RECT  161.844 4.297 161.964 36.784 ;
        RECT  157.524 181.4 157.644 211.703 ;
        RECT  157.524 4.297 157.644 36.784 ;
        RECT  153.204 181.4 153.324 211.703 ;
        RECT  153.204 4.297 153.324 36.784 ;
        RECT  148.884 181.4 149.004 211.703 ;
        RECT  148.884 4.297 149.004 36.784 ;
        RECT  144.564 181.4 144.684 211.703 ;
        RECT  144.564 4.297 144.684 36.784 ;
        RECT  140.244 181.4 140.364 211.703 ;
        RECT  140.244 4.297 140.364 36.784 ;
        RECT  135.924 4.297 136.044 211.703 ;
        RECT  131.604 4.297 131.724 211.703 ;
        RECT  127.284 4.297 127.404 211.703 ;
        RECT  122.964 4.297 123.084 211.703 ;
        RECT  118.644 4.297 118.764 211.703 ;
        RECT  114.324 4.297 114.444 211.703 ;
        RECT  110.004 181.4 110.124 211.703 ;
        RECT  110.004 4.297 110.124 36.784 ;
        RECT  105.684 181.4 105.804 211.703 ;
        RECT  105.684 4.297 105.804 36.784 ;
        RECT  101.364 181.4 101.484 211.703 ;
        RECT  101.364 4.297 101.484 36.784 ;
        RECT  97.044 181.4 97.164 211.703 ;
        RECT  97.044 4.297 97.164 36.784 ;
        RECT  92.724 181.4 92.844 211.703 ;
        RECT  92.724 4.297 92.844 36.784 ;
        RECT  88.404 181.4 88.524 211.703 ;
        RECT  88.404 4.297 88.524 36.784 ;
        RECT  84.084 181.4 84.204 211.703 ;
        RECT  84.084 4.297 84.204 36.784 ;
        RECT  79.764 181.4 79.884 211.703 ;
        RECT  79.764 4.297 79.884 36.784 ;
        RECT  75.444 181.4 75.564 211.703 ;
        RECT  75.444 4.297 75.564 36.784 ;
        RECT  71.124 4.297 71.244 211.703 ;
        RECT  66.804 4.297 66.924 211.703 ;
        RECT  62.484 4.297 62.604 211.703 ;
        RECT  58.164 4.297 58.284 211.703 ;
        RECT  53.844 4.297 53.964 211.703 ;
        RECT  49.524 4.297 49.644 211.703 ;
        RECT  45.204 4.297 45.324 211.703 ;
        RECT  40.884 4.297 41.004 211.703 ;
        RECT  36.564 4.297 36.684 211.703 ;
        RECT  32.244 4.297 32.364 211.703 ;
        RECT  27.924 4.297 28.044 211.703 ;
        RECT  23.604 4.297 23.724 211.703 ;
        RECT  19.284 4.297 19.404 211.703 ;
        RECT  14.964 4.297 15.084 211.703 ;
        RECT  10.644 4.297 10.764 211.703 ;
        RECT  6.324 4.297 6.444 211.703 ;
    END
  END VSS
  PIN ft_ck_i
    DIRECTION INPUT ;
    USE SIGNAL ;
    PORT
      LAYER M5 ;
        RECT  122.688 109.968 122.712 110.352 ;
    END
  END ft_ck_i
  PIN ft_ck_o
    DIRECTION OUTPUT ;
    USE SIGNAL ;
    PORT
      LAYER M5 ;
        RECT  127.872 109.968 127.896 110.352 ;
    END
  END ft_ck_o
  PIN ft_rst_i
    DIRECTION INPUT ;
    USE SIGNAL ;
    PORT
      LAYER M5 ;
        RECT  122.688 105.648 122.712 106.032 ;
    END
  END ft_rst_i
  PIN ft_rst_o
    DIRECTION OUTPUT ;
    USE SIGNAL ;
    PORT
      LAYER M5 ;
        RECT  127.872 105.648 127.896 106.032 ;
    END
  END ft_rst_o
  OBS
      LAYER RVTN ;
     RECT  0 0 246.24 211.739 ;
      LAYER RVTP ;
     RECT  0 0 246.24 211.739 ;
      LAYER M1 ;
     RECT  0 0 246.24 211.739 ;
      LAYER M2 ;
     RECT  0 0 246.24 211.739 ;
      LAYER M3 ;
     RECT  0 0 246.24 211.739 ;
      LAYER M4 ;
     RECT  0 0 246.24 211.739 ;
      LAYER M5 ;
     RECT  0 0 246.24 211.739 ;
      LAYER M6 ;
     RECT  6.805 165.248 7.379 165.28 ;
     RECT  6.757 177.28 7.379 177.312 ;
     RECT  6.853 169.024 9.395 169.056 ;
     RECT  9.349 184.128 9.971 184.16 ;
     RECT  9.925 197.696 9.973 197.728 ;
     RECT  9.061 189.184 10.019 189.216 ;
     RECT  9.973 196.608 12.035 197.728 ;
     RECT  12.035 197.248 12.563 197.728 ;
     RECT  12.563 197.248 13.283 197.28 ;
     RECT  9.637 190.912 14.531 190.944 ;
     RECT  29.029 195.264 35.075 195.296 ;
     RECT  35.029 186.24 49.909 186.272 ;
     RECT  49.909 185.984 49.957 186.272 ;
     RECT  46.069 12.48 50.101 12.512 ;
     RECT  50.101 12.032 51.061 12.512 ;
     RECT  51.061 12.032 51.443 13.664 ;
     RECT  51.443 13.632 52.163 13.664 ;
     RECT  52.117 15.744 56.483 15.776 ;
     RECT  51.443 12.032 59.221 12.064 ;
     RECT  59.221 12.032 60.661 12.256 ;
     RECT  60.661 12.032 60.707 12.448 ;
     RECT  60.707 12.224 62.915 12.448 ;
     RECT  59.797 14.912 63.061 14.944 ;
     RECT  63.061 14.912 63.107 15.136 ;
     RECT  63.107 15.104 64.115 15.136 ;
     RECT  63.205 19.968 64.115 20 ;
     RECT  64.069 17.472 65.123 17.504 ;
     RECT  49.957 185.984 67.811 186.4 ;
     RECT  62.915 12.224 70.069 12.256 ;
     RECT  74.053 15.424 75.253 15.456 ;
     RECT  73.477 17.088 75.253 17.12 ;
     RECT  75.253 15.424 75.299 17.12 ;
     RECT  70.069 12.224 75.347 12.768 ;
     RECT  75.347 12.224 76.115 12.256 ;
     RECT  75.299 15.424 80.435 16.544 ;
     RECT  14.485 200.064 81.445 200.096 ;
     RECT  67.811 186.368 81.637 186.4 ;
     RECT  81.637 186.112 81.683 186.4 ;
     RECT  80.435 15.424 82.645 15.456 ;
     RECT  82.645 15.424 83.317 15.648 ;
     RECT  83.317 15.36 83.363 15.648 ;
     RECT  81.683 186.112 84.709 186.144 ;
     RECT  83.363 15.36 88.789 15.392 ;
     RECT  88.789 15.36 88.835 16.032 ;
     RECT  84.709 185.792 88.979 186.144 ;
     RECT  88.835 16 90.707 16.032 ;
     RECT  85.477 10.048 91.475 10.08 ;
     RECT  88.933 184.192 94.115 184.224 ;
     RECT  91.429 12.224 94.691 12.256 ;
     RECT  88.979 185.792 101.795 185.824 ;
     RECT  99.877 22.208 101.939 22.24 ;
     RECT  76.069 29.056 102.565 29.088 ;
     RECT  101.989 24.896 107.459 24.928 ;
     RECT  107.413 12.864 107.557 12.896 ;
     RECT  107.557 12.736 107.603 12.896 ;
     RECT  82.021 7.872 107.701 7.904 ;
     RECT  107.077 11.328 107.701 11.36 ;
     RECT  107.603 12.736 107.701 12.768 ;
     RECT  107.701 11.328 107.747 12.768 ;
     RECT  102.565 29.056 110.435 30.048 ;
     RECT  107.747 12.544 112.355 12.768 ;
     RECT  106.069 185.792 114.227 185.824 ;
     RECT  81.445 198.784 114.227 200.096 ;
     RECT  112.355 12.544 114.755 12.576 ;
     RECT  114.227 198.784 114.851 198.816 ;
     RECT  114.709 18.304 116.963 18.336 ;
     RECT  107.701 7.872 117.155 8.736 ;
     RECT  113.365 194.432 124.835 194.464 ;
     RECT  117.109 26.496 124.883 26.528 ;
     RECT  114.805 193.088 124.883 193.12 ;
     RECT  110.435 29.056 125.075 29.088 ;
     RECT  117.155 7.872 125.267 7.904 ;
     RECT  121.381 14.4 125.413 14.432 ;
     RECT  125.413 13.312 125.459 14.432 ;
     RECT  124.693 109.312 126.611 109.344 ;
     RECT  124.933 26.688 126.803 26.72 ;
     RECT  125.459 13.312 128.867 13.344 ;
     RECT  126.757 58.176 129.251 58.208 ;
     RECT  114.181 178.816 130.019 178.848 ;
     RECT  129.445 20.48 130.259 20.512 ;
     RECT  130.213 13.312 133.427 13.344 ;
     RECT  125.701 6.528 134.003 6.56 ;
     RECT  125.557 8.448 134.243 8.48 ;
     RECT  137.317 17.6 138.517 17.632 ;
     RECT  134.197 22.72 138.517 22.752 ;
     RECT  138.517 17.408 138.755 17.632 ;
     RECT  138.755 17.6 138.803 17.632 ;
     RECT  138.517 22.528 140.675 22.752 ;
     RECT  140.675 22.72 142.163 22.752 ;
     RECT  139.045 31.36 146.003 31.392 ;
     RECT  130.069 185.28 151.667 185.312 ;
     RECT  125.029 198.784 154.499 198.816 ;
     RECT  129.349 186.624 155.077 186.656 ;
     RECT  155.077 186.496 155.123 186.656 ;
     RECT  155.123 186.496 155.557 186.528 ;
     RECT  155.557 186.368 155.603 186.528 ;
     RECT  155.603 186.368 157.285 186.4 ;
     RECT  157.285 185.28 162.275 186.4 ;
     RECT  162.275 186.176 166.067 186.4 ;
     RECT  167.557 10.88 167.797 10.912 ;
     RECT  156.133 18.944 167.843 18.976 ;
     RECT  166.067 186.368 168.229 186.4 ;
     RECT  168.229 186.112 168.275 186.4 ;
     RECT  167.797 10.88 172.213 12 ;
     RECT  172.213 10.88 172.259 12.256 ;
     RECT  168.275 186.112 172.739 186.144 ;
     RECT  172.259 12.224 180.469 12.256 ;
     RECT  180.469 12.224 180.515 13.024 ;
     RECT  180.515 12.992 184.739 13.024 ;
     RECT  125.365 25.088 186.179 25.12 ;
     RECT  172.259 10.88 187.619 10.912 ;
     RECT  187.573 14.656 196.885 14.688 ;
     RECT  193.765 7.616 196.931 7.648 ;
     RECT  196.885 13.376 198.995 14.688 ;
     RECT  198.995 13.376 199.139 13.664 ;
     RECT  199.139 13.632 201.109 13.664 ;
     RECT  201.109 13.632 201.155 14.112 ;
     RECT  201.155 14.08 207.779 14.112 ;
     RECT  207.733 7.936 209.267 7.968 ;
  END
END qfd_dv_s8x_vmr
END LIBRARY
